VERSION 5.8 ;
BUSBITCHARS "[]" ;
DIVIDERCHAR "/" ;
UNITS
    DATABASE MICRONS 1000 ;
END UNITS

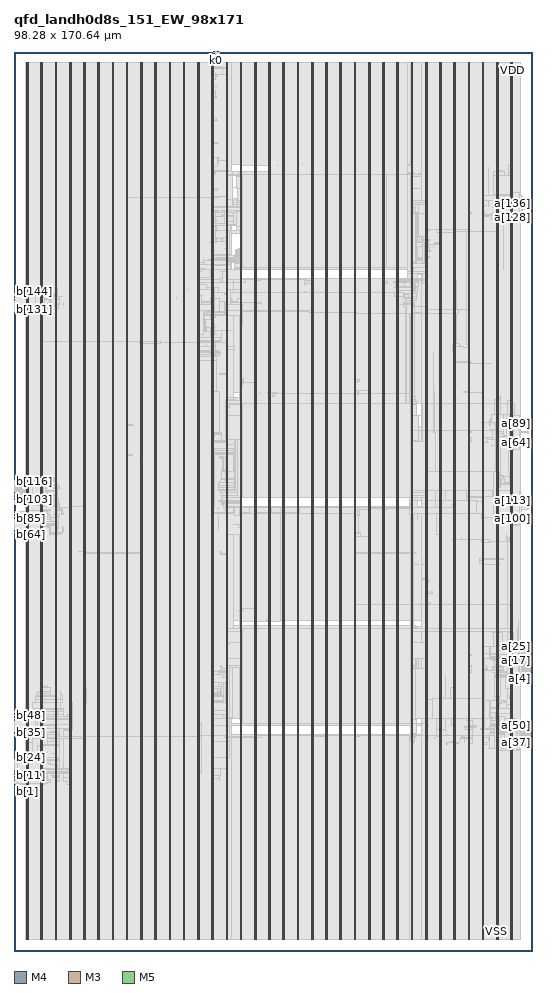
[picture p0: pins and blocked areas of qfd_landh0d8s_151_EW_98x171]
MACRO qfd_landh0d8s_151_EW_98x171
  FOREIGN qfd_landh0d8s_151_EW_98x171 0 0 ;
  CLASS BLOCK ;
  SIZE 98.28 BY 170.64 ;
  PIN a[0]
    DIRECTION INPUT ;
    USE SIGNAL ;
    PORT
      LAYER M4 ;
        RECT  98.196 52.56 98.28 52.584 ;
    END
  END a[0]
  PIN a[100]
    DIRECTION INPUT ;
    USE SIGNAL ;
    PORT
      LAYER M4 ;
        RECT  98.196 81.936 98.28 81.96 ;
    END
  END a[100]
  PIN a[101]
    DIRECTION INPUT ;
    USE SIGNAL ;
    PORT
      LAYER M4 ;
        RECT  98.196 82.08 98.28 82.104 ;
    END
  END a[101]
  PIN a[102]
    DIRECTION INPUT ;
    USE SIGNAL ;
    PORT
      LAYER M4 ;
        RECT  98.196 82.224 98.28 82.248 ;
    END
  END a[102]
  PIN a[103]
    DIRECTION INPUT ;
    USE SIGNAL ;
    PORT
      LAYER M4 ;
        RECT  98.196 82.368 98.28 82.392 ;
    END
  END a[103]
  PIN a[104]
    DIRECTION INPUT ;
    USE SIGNAL ;
    PORT
      LAYER M4 ;
        RECT  98.196 82.512 98.28 82.536 ;
    END
  END a[104]
  PIN a[105]
    DIRECTION INPUT ;
    USE SIGNAL ;
    PORT
      LAYER M4 ;
        RECT  98.196 82.656 98.28 82.68 ;
    END
  END a[105]
  PIN a[106]
    DIRECTION INPUT ;
    USE SIGNAL ;
    PORT
      LAYER M4 ;
        RECT  98.196 82.8 98.28 82.824 ;
    END
  END a[106]
  PIN a[107]
    DIRECTION INPUT ;
    USE SIGNAL ;
    PORT
      LAYER M4 ;
        RECT  98.196 82.944 98.28 82.968 ;
    END
  END a[107]
  PIN a[108]
    DIRECTION INPUT ;
    USE SIGNAL ;
    PORT
      LAYER M4 ;
        RECT  98.196 83.088 98.28 83.112 ;
    END
  END a[108]
  PIN a[109]
    DIRECTION INPUT ;
    USE SIGNAL ;
    PORT
      LAYER M4 ;
        RECT  98.196 83.232 98.28 83.256 ;
    END
  END a[109]
  PIN a[10]
    DIRECTION INPUT ;
    USE SIGNAL ;
    PORT
      LAYER M4 ;
        RECT  98.196 54 98.28 54.024 ;
    END
  END a[10]
  PIN a[110]
    DIRECTION INPUT ;
    USE SIGNAL ;
    PORT
      LAYER M4 ;
        RECT  98.196 83.376 98.28 83.4 ;
    END
  END a[110]
  PIN a[111]
    DIRECTION INPUT ;
    USE SIGNAL ;
    PORT
      LAYER M4 ;
        RECT  98.196 83.52 98.28 83.544 ;
    END
  END a[111]
  PIN a[112]
    DIRECTION INPUT ;
    USE SIGNAL ;
    PORT
      LAYER M4 ;
        RECT  98.196 83.664 98.28 83.688 ;
    END
  END a[112]
  PIN a[113]
    DIRECTION INPUT ;
    USE SIGNAL ;
    PORT
      LAYER M4 ;
        RECT  98.196 83.808 98.28 83.832 ;
    END
  END a[113]
  PIN a[114]
    DIRECTION INPUT ;
    USE SIGNAL ;
    PORT
      LAYER M4 ;
        RECT  98.196 83.952 98.28 83.976 ;
    END
  END a[114]
  PIN a[115]
    DIRECTION INPUT ;
    USE SIGNAL ;
    PORT
      LAYER M4 ;
        RECT  98.196 84.096 98.28 84.12 ;
    END
  END a[115]
  PIN a[116]
    DIRECTION INPUT ;
    USE SIGNAL ;
    PORT
      LAYER M4 ;
        RECT  98.196 84.24 98.28 84.264 ;
    END
  END a[116]
  PIN a[117]
    DIRECTION INPUT ;
    USE SIGNAL ;
    PORT
      LAYER M4 ;
        RECT  98.196 84.384 98.28 84.408 ;
    END
  END a[117]
  PIN a[118]
    DIRECTION INPUT ;
    USE SIGNAL ;
    PORT
      LAYER M4 ;
        RECT  98.196 84.528 98.28 84.552 ;
    END
  END a[118]
  PIN a[119]
    DIRECTION INPUT ;
    USE SIGNAL ;
    PORT
      LAYER M4 ;
        RECT  98.196 84.672 98.28 84.696 ;
    END
  END a[119]
  PIN a[11]
    DIRECTION INPUT ;
    USE SIGNAL ;
    PORT
      LAYER M4 ;
        RECT  98.196 54.144 98.28 54.168 ;
    END
  END a[11]
  PIN a[120]
    DIRECTION INPUT ;
    USE SIGNAL ;
    PORT
      LAYER M4 ;
        RECT  98.196 84.816 98.28 84.84 ;
    END
  END a[120]
  PIN a[121]
    DIRECTION INPUT ;
    USE SIGNAL ;
    PORT
      LAYER M4 ;
        RECT  98.196 84.96 98.28 84.984 ;
    END
  END a[121]
  PIN a[122]
    DIRECTION INPUT ;
    USE SIGNAL ;
    PORT
      LAYER M4 ;
        RECT  98.196 85.104 98.28 85.128 ;
    END
  END a[122]
  PIN a[123]
    DIRECTION INPUT ;
    USE SIGNAL ;
    PORT
      LAYER M4 ;
        RECT  98.196 85.248 98.28 85.272 ;
    END
  END a[123]
  PIN a[124]
    DIRECTION INPUT ;
    USE SIGNAL ;
    PORT
      LAYER M4 ;
        RECT  98.196 85.392 98.28 85.416 ;
    END
  END a[124]
  PIN a[125]
    DIRECTION INPUT ;
    USE SIGNAL ;
    PORT
      LAYER M4 ;
        RECT  98.196 85.536 98.28 85.56 ;
    END
  END a[125]
  PIN a[126]
    DIRECTION INPUT ;
    USE SIGNAL ;
    PORT
      LAYER M4 ;
        RECT  98.196 85.68 98.28 85.704 ;
    END
  END a[126]
  PIN a[127]
    DIRECTION INPUT ;
    USE SIGNAL ;
    PORT
      LAYER M4 ;
        RECT  98.196 85.824 98.28 85.848 ;
    END
  END a[127]
  PIN a[128]
    DIRECTION INPUT ;
    USE SIGNAL ;
    PORT
      LAYER M4 ;
        RECT  98.196 139.104 98.28 139.128 ;
    END
  END a[128]
  PIN a[129]
    DIRECTION INPUT ;
    USE SIGNAL ;
    PORT
      LAYER M4 ;
        RECT  98.196 139.248 98.28 139.272 ;
    END
  END a[129]
  PIN a[12]
    DIRECTION INPUT ;
    USE SIGNAL ;
    PORT
      LAYER M4 ;
        RECT  98.196 54.288 98.28 54.312 ;
    END
  END a[12]
  PIN a[130]
    DIRECTION INPUT ;
    USE SIGNAL ;
    PORT
      LAYER M4 ;
        RECT  98.196 139.392 98.28 139.416 ;
    END
  END a[130]
  PIN a[131]
    DIRECTION INPUT ;
    USE SIGNAL ;
    PORT
      LAYER M4 ;
        RECT  98.196 139.536 98.28 139.56 ;
    END
  END a[131]
  PIN a[132]
    DIRECTION INPUT ;
    USE SIGNAL ;
    PORT
      LAYER M4 ;
        RECT  98.196 139.68 98.28 139.704 ;
    END
  END a[132]
  PIN a[133]
    DIRECTION INPUT ;
    USE SIGNAL ;
    PORT
      LAYER M4 ;
        RECT  98.196 139.824 98.28 139.848 ;
    END
  END a[133]
  PIN a[134]
    DIRECTION INPUT ;
    USE SIGNAL ;
    PORT
      LAYER M4 ;
        RECT  98.196 139.968 98.28 139.992 ;
    END
  END a[134]
  PIN a[135]
    DIRECTION INPUT ;
    USE SIGNAL ;
    PORT
      LAYER M4 ;
        RECT  98.196 140.112 98.28 140.136 ;
    END
  END a[135]
  PIN a[136]
    DIRECTION INPUT ;
    USE SIGNAL ;
    PORT
      LAYER M4 ;
        RECT  98.196 140.256 98.28 140.28 ;
    END
  END a[136]
  PIN a[137]
    DIRECTION INPUT ;
    USE SIGNAL ;
    PORT
      LAYER M4 ;
        RECT  98.196 140.4 98.28 140.424 ;
    END
  END a[137]
  PIN a[138]
    DIRECTION INPUT ;
    USE SIGNAL ;
    PORT
      LAYER M4 ;
        RECT  98.196 140.544 98.28 140.568 ;
    END
  END a[138]
  PIN a[139]
    DIRECTION INPUT ;
    USE SIGNAL ;
    PORT
      LAYER M4 ;
        RECT  98.196 140.688 98.28 140.712 ;
    END
  END a[139]
  PIN a[13]
    DIRECTION INPUT ;
    USE SIGNAL ;
    PORT
      LAYER M4 ;
        RECT  98.196 54.432 98.28 54.456 ;
    END
  END a[13]
  PIN a[140]
    DIRECTION INPUT ;
    USE SIGNAL ;
    PORT
      LAYER M4 ;
        RECT  98.196 140.832 98.28 140.856 ;
    END
  END a[140]
  PIN a[141]
    DIRECTION INPUT ;
    USE SIGNAL ;
    PORT
      LAYER M4 ;
        RECT  98.196 140.976 98.28 141 ;
    END
  END a[141]
  PIN a[142]
    DIRECTION INPUT ;
    USE SIGNAL ;
    PORT
      LAYER M4 ;
        RECT  98.196 141.12 98.28 141.144 ;
    END
  END a[142]
  PIN a[143]
    DIRECTION INPUT ;
    USE SIGNAL ;
    PORT
      LAYER M4 ;
        RECT  98.196 141.264 98.28 141.288 ;
    END
  END a[143]
  PIN a[144]
    DIRECTION INPUT ;
    USE SIGNAL ;
    PORT
      LAYER M4 ;
        RECT  98.196 141.408 98.28 141.432 ;
    END
  END a[144]
  PIN a[145]
    DIRECTION INPUT ;
    USE SIGNAL ;
    PORT
      LAYER M4 ;
        RECT  98.196 141.552 98.28 141.576 ;
    END
  END a[145]
  PIN a[146]
    DIRECTION INPUT ;
    USE SIGNAL ;
    PORT
      LAYER M4 ;
        RECT  98.196 141.696 98.28 141.72 ;
    END
  END a[146]
  PIN a[147]
    DIRECTION INPUT ;
    USE SIGNAL ;
    PORT
      LAYER M4 ;
        RECT  98.196 141.84 98.28 141.864 ;
    END
  END a[147]
  PIN a[148]
    DIRECTION INPUT ;
    USE SIGNAL ;
    PORT
      LAYER M4 ;
        RECT  98.196 141.984 98.28 142.008 ;
    END
  END a[148]
  PIN a[149]
    DIRECTION INPUT ;
    USE SIGNAL ;
    PORT
      LAYER M4 ;
        RECT  98.196 142.128 98.28 142.152 ;
    END
  END a[149]
  PIN a[14]
    DIRECTION INPUT ;
    USE SIGNAL ;
    PORT
      LAYER M4 ;
        RECT  98.196 54.576 98.28 54.6 ;
    END
  END a[14]
  PIN a[150]
    DIRECTION INPUT ;
    USE SIGNAL ;
    PORT
      LAYER M4 ;
        RECT  98.196 142.272 98.28 142.296 ;
    END
  END a[150]
  PIN a[15]
    DIRECTION INPUT ;
    USE SIGNAL ;
    PORT
      LAYER M4 ;
        RECT  98.196 54.72 98.28 54.744 ;
    END
  END a[15]
  PIN a[16]
    DIRECTION INPUT ;
    USE SIGNAL ;
    PORT
      LAYER M4 ;
        RECT  98.196 54.864 98.28 54.888 ;
    END
  END a[16]
  PIN a[17]
    DIRECTION INPUT ;
    USE SIGNAL ;
    PORT
      LAYER M4 ;
        RECT  98.196 55.008 98.28 55.032 ;
    END
  END a[17]
  PIN a[18]
    DIRECTION INPUT ;
    USE SIGNAL ;
    PORT
      LAYER M4 ;
        RECT  98.196 55.152 98.28 55.176 ;
    END
  END a[18]
  PIN a[19]
    DIRECTION INPUT ;
    USE SIGNAL ;
    PORT
      LAYER M4 ;
        RECT  98.196 55.296 98.28 55.32 ;
    END
  END a[19]
  PIN a[1]
    DIRECTION INPUT ;
    USE SIGNAL ;
    PORT
      LAYER M4 ;
        RECT  98.196 52.704 98.28 52.728 ;
    END
  END a[1]
  PIN a[20]
    DIRECTION INPUT ;
    USE SIGNAL ;
    PORT
      LAYER M4 ;
        RECT  98.196 55.44 98.28 55.464 ;
    END
  END a[20]
  PIN a[21]
    DIRECTION INPUT ;
    USE SIGNAL ;
    PORT
      LAYER M4 ;
        RECT  98.196 55.584 98.28 55.608 ;
    END
  END a[21]
  PIN a[22]
    DIRECTION INPUT ;
    USE SIGNAL ;
    PORT
      LAYER M4 ;
        RECT  98.196 55.728 98.28 55.752 ;
    END
  END a[22]
  PIN a[23]
    DIRECTION INPUT ;
    USE SIGNAL ;
    PORT
      LAYER M4 ;
        RECT  98.196 55.872 98.28 55.896 ;
    END
  END a[23]
  PIN a[24]
    DIRECTION INPUT ;
    USE SIGNAL ;
    PORT
      LAYER M4 ;
        RECT  98.196 56.016 98.28 56.04 ;
    END
  END a[24]
  PIN a[25]
    DIRECTION INPUT ;
    USE SIGNAL ;
    PORT
      LAYER M4 ;
        RECT  98.196 56.16 98.28 56.184 ;
    END
  END a[25]
  PIN a[26]
    DIRECTION INPUT ;
    USE SIGNAL ;
    PORT
      LAYER M4 ;
        RECT  98.196 56.304 98.28 56.328 ;
    END
  END a[26]
  PIN a[27]
    DIRECTION INPUT ;
    USE SIGNAL ;
    PORT
      LAYER M4 ;
        RECT  98.196 56.448 98.28 56.472 ;
    END
  END a[27]
  PIN a[28]
    DIRECTION INPUT ;
    USE SIGNAL ;
    PORT
      LAYER M4 ;
        RECT  98.196 56.592 98.28 56.616 ;
    END
  END a[28]
  PIN a[29]
    DIRECTION INPUT ;
    USE SIGNAL ;
    PORT
      LAYER M4 ;
        RECT  98.196 56.736 98.28 56.76 ;
    END
  END a[29]
  PIN a[2]
    DIRECTION INPUT ;
    USE SIGNAL ;
    PORT
      LAYER M4 ;
        RECT  98.196 52.848 98.28 52.872 ;
    END
  END a[2]
  PIN a[30]
    DIRECTION INPUT ;
    USE SIGNAL ;
    PORT
      LAYER M4 ;
        RECT  98.196 56.88 98.28 56.904 ;
    END
  END a[30]
  PIN a[31]
    DIRECTION INPUT ;
    USE SIGNAL ;
    PORT
      LAYER M4 ;
        RECT  98.196 57.024 98.28 57.048 ;
    END
  END a[31]
  PIN a[32]
    DIRECTION INPUT ;
    USE SIGNAL ;
    PORT
      LAYER M4 ;
        RECT  98.196 38.736 98.28 38.76 ;
    END
  END a[32]
  PIN a[33]
    DIRECTION INPUT ;
    USE SIGNAL ;
    PORT
      LAYER M4 ;
        RECT  98.196 38.88 98.28 38.904 ;
    END
  END a[33]
  PIN a[34]
    DIRECTION INPUT ;
    USE SIGNAL ;
    PORT
      LAYER M4 ;
        RECT  98.196 39.024 98.28 39.048 ;
    END
  END a[34]
  PIN a[35]
    DIRECTION INPUT ;
    USE SIGNAL ;
    PORT
      LAYER M4 ;
        RECT  98.196 39.168 98.28 39.192 ;
    END
  END a[35]
  PIN a[36]
    DIRECTION INPUT ;
    USE SIGNAL ;
    PORT
      LAYER M4 ;
        RECT  98.196 39.312 98.28 39.336 ;
    END
  END a[36]
  PIN a[37]
    DIRECTION INPUT ;
    USE SIGNAL ;
    PORT
      LAYER M4 ;
        RECT  98.196 39.456 98.28 39.48 ;
    END
  END a[37]
  PIN a[38]
    DIRECTION INPUT ;
    USE SIGNAL ;
    PORT
      LAYER M4 ;
        RECT  98.196 39.6 98.28 39.624 ;
    END
  END a[38]
  PIN a[39]
    DIRECTION INPUT ;
    USE SIGNAL ;
    PORT
      LAYER M4 ;
        RECT  98.196 39.744 98.28 39.768 ;
    END
  END a[39]
  PIN a[3]
    DIRECTION INPUT ;
    USE SIGNAL ;
    PORT
      LAYER M4 ;
        RECT  98.196 52.992 98.28 53.016 ;
    END
  END a[3]
  PIN a[40]
    DIRECTION INPUT ;
    USE SIGNAL ;
    PORT
      LAYER M4 ;
        RECT  98.196 39.888 98.28 39.912 ;
    END
  END a[40]
  PIN a[41]
    DIRECTION INPUT ;
    USE SIGNAL ;
    PORT
      LAYER M4 ;
        RECT  98.196 40.032 98.28 40.056 ;
    END
  END a[41]
  PIN a[42]
    DIRECTION INPUT ;
    USE SIGNAL ;
    PORT
      LAYER M4 ;
        RECT  98.196 40.176 98.28 40.2 ;
    END
  END a[42]
  PIN a[43]
    DIRECTION INPUT ;
    USE SIGNAL ;
    PORT
      LAYER M4 ;
        RECT  98.196 40.32 98.28 40.344 ;
    END
  END a[43]
  PIN a[44]
    DIRECTION INPUT ;
    USE SIGNAL ;
    PORT
      LAYER M4 ;
        RECT  98.196 40.464 98.28 40.488 ;
    END
  END a[44]
  PIN a[45]
    DIRECTION INPUT ;
    USE SIGNAL ;
    PORT
      LAYER M4 ;
        RECT  98.196 40.608 98.28 40.632 ;
    END
  END a[45]
  PIN a[46]
    DIRECTION INPUT ;
    USE SIGNAL ;
    PORT
      LAYER M4 ;
        RECT  98.196 40.752 98.28 40.776 ;
    END
  END a[46]
  PIN a[47]
    DIRECTION INPUT ;
    USE SIGNAL ;
    PORT
      LAYER M4 ;
        RECT  98.196 40.896 98.28 40.92 ;
    END
  END a[47]
  PIN a[48]
    DIRECTION INPUT ;
    USE SIGNAL ;
    PORT
      LAYER M4 ;
        RECT  98.196 41.04 98.28 41.064 ;
    END
  END a[48]
  PIN a[49]
    DIRECTION INPUT ;
    USE SIGNAL ;
    PORT
      LAYER M4 ;
        RECT  98.196 41.184 98.28 41.208 ;
    END
  END a[49]
  PIN a[4]
    DIRECTION INPUT ;
    USE SIGNAL ;
    PORT
      LAYER M4 ;
        RECT  98.196 53.136 98.28 53.16 ;
    END
  END a[4]
  PIN a[50]
    DIRECTION INPUT ;
    USE SIGNAL ;
    PORT
      LAYER M4 ;
        RECT  98.196 41.328 98.28 41.352 ;
    END
  END a[50]
  PIN a[51]
    DIRECTION INPUT ;
    USE SIGNAL ;
    PORT
      LAYER M4 ;
        RECT  98.196 41.472 98.28 41.496 ;
    END
  END a[51]
  PIN a[52]
    DIRECTION INPUT ;
    USE SIGNAL ;
    PORT
      LAYER M4 ;
        RECT  98.196 41.616 98.28 41.64 ;
    END
  END a[52]
  PIN a[53]
    DIRECTION INPUT ;
    USE SIGNAL ;
    PORT
      LAYER M4 ;
        RECT  98.196 41.76 98.28 41.784 ;
    END
  END a[53]
  PIN a[54]
    DIRECTION INPUT ;
    USE SIGNAL ;
    PORT
      LAYER M4 ;
        RECT  98.196 41.904 98.28 41.928 ;
    END
  END a[54]
  PIN a[55]
    DIRECTION INPUT ;
    USE SIGNAL ;
    PORT
      LAYER M4 ;
        RECT  98.196 42.048 98.28 42.072 ;
    END
  END a[55]
  PIN a[56]
    DIRECTION INPUT ;
    USE SIGNAL ;
    PORT
      LAYER M4 ;
        RECT  98.196 42.192 98.28 42.216 ;
    END
  END a[56]
  PIN a[57]
    DIRECTION INPUT ;
    USE SIGNAL ;
    PORT
      LAYER M4 ;
        RECT  98.196 42.336 98.28 42.36 ;
    END
  END a[57]
  PIN a[58]
    DIRECTION INPUT ;
    USE SIGNAL ;
    PORT
      LAYER M4 ;
        RECT  98.196 42.48 98.28 42.504 ;
    END
  END a[58]
  PIN a[59]
    DIRECTION INPUT ;
    USE SIGNAL ;
    PORT
      LAYER M4 ;
        RECT  98.196 42.624 98.28 42.648 ;
    END
  END a[59]
  PIN a[5]
    DIRECTION INPUT ;
    USE SIGNAL ;
    PORT
      LAYER M4 ;
        RECT  98.196 53.28 98.28 53.304 ;
    END
  END a[5]
  PIN a[60]
    DIRECTION INPUT ;
    USE SIGNAL ;
    PORT
      LAYER M4 ;
        RECT  98.196 42.768 98.28 42.792 ;
    END
  END a[60]
  PIN a[61]
    DIRECTION INPUT ;
    USE SIGNAL ;
    PORT
      LAYER M4 ;
        RECT  98.196 42.912 98.28 42.936 ;
    END
  END a[61]
  PIN a[62]
    DIRECTION INPUT ;
    USE SIGNAL ;
    PORT
      LAYER M4 ;
        RECT  98.196 43.056 98.28 43.08 ;
    END
  END a[62]
  PIN a[63]
    DIRECTION INPUT ;
    USE SIGNAL ;
    PORT
      LAYER M4 ;
        RECT  98.196 43.2 98.28 43.224 ;
    END
  END a[63]
  PIN a[64]
    DIRECTION INPUT ;
    USE SIGNAL ;
    PORT
      LAYER M4 ;
        RECT  98.196 96.336 98.28 96.36 ;
    END
  END a[64]
  PIN a[65]
    DIRECTION INPUT ;
    USE SIGNAL ;
    PORT
      LAYER M4 ;
        RECT  98.196 96.48 98.28 96.504 ;
    END
  END a[65]
  PIN a[66]
    DIRECTION INPUT ;
    USE SIGNAL ;
    PORT
      LAYER M4 ;
        RECT  98.196 96.624 98.28 96.648 ;
    END
  END a[66]
  PIN a[67]
    DIRECTION INPUT ;
    USE SIGNAL ;
    PORT
      LAYER M4 ;
        RECT  98.196 96.768 98.28 96.792 ;
    END
  END a[67]
  PIN a[68]
    DIRECTION INPUT ;
    USE SIGNAL ;
    PORT
      LAYER M4 ;
        RECT  98.196 96.912 98.28 96.936 ;
    END
  END a[68]
  PIN a[69]
    DIRECTION INPUT ;
    USE SIGNAL ;
    PORT
      LAYER M4 ;
        RECT  98.196 97.056 98.28 97.08 ;
    END
  END a[69]
  PIN a[6]
    DIRECTION INPUT ;
    USE SIGNAL ;
    PORT
      LAYER M4 ;
        RECT  98.196 53.424 98.28 53.448 ;
    END
  END a[6]
  PIN a[70]
    DIRECTION INPUT ;
    USE SIGNAL ;
    PORT
      LAYER M4 ;
        RECT  98.196 97.2 98.28 97.224 ;
    END
  END a[70]
  PIN a[71]
    DIRECTION INPUT ;
    USE SIGNAL ;
    PORT
      LAYER M4 ;
        RECT  98.196 97.344 98.28 97.368 ;
    END
  END a[71]
  PIN a[72]
    DIRECTION INPUT ;
    USE SIGNAL ;
    PORT
      LAYER M4 ;
        RECT  98.196 97.488 98.28 97.512 ;
    END
  END a[72]
  PIN a[73]
    DIRECTION INPUT ;
    USE SIGNAL ;
    PORT
      LAYER M4 ;
        RECT  98.196 97.632 98.28 97.656 ;
    END
  END a[73]
  PIN a[74]
    DIRECTION INPUT ;
    USE SIGNAL ;
    PORT
      LAYER M4 ;
        RECT  98.196 97.776 98.28 97.8 ;
    END
  END a[74]
  PIN a[75]
    DIRECTION INPUT ;
    USE SIGNAL ;
    PORT
      LAYER M4 ;
        RECT  98.196 97.92 98.28 97.944 ;
    END
  END a[75]
  PIN a[76]
    DIRECTION INPUT ;
    USE SIGNAL ;
    PORT
      LAYER M4 ;
        RECT  98.196 98.064 98.28 98.088 ;
    END
  END a[76]
  PIN a[77]
    DIRECTION INPUT ;
    USE SIGNAL ;
    PORT
      LAYER M4 ;
        RECT  98.196 98.208 98.28 98.232 ;
    END
  END a[77]
  PIN a[78]
    DIRECTION INPUT ;
    USE SIGNAL ;
    PORT
      LAYER M4 ;
        RECT  98.196 98.352 98.28 98.376 ;
    END
  END a[78]
  PIN a[79]
    DIRECTION INPUT ;
    USE SIGNAL ;
    PORT
      LAYER M4 ;
        RECT  98.196 98.496 98.28 98.52 ;
    END
  END a[79]
  PIN a[7]
    DIRECTION INPUT ;
    USE SIGNAL ;
    PORT
      LAYER M4 ;
        RECT  98.196 53.568 98.28 53.592 ;
    END
  END a[7]
  PIN a[80]
    DIRECTION INPUT ;
    USE SIGNAL ;
    PORT
      LAYER M4 ;
        RECT  98.196 98.64 98.28 98.664 ;
    END
  END a[80]
  PIN a[81]
    DIRECTION INPUT ;
    USE SIGNAL ;
    PORT
      LAYER M4 ;
        RECT  98.196 98.784 98.28 98.808 ;
    END
  END a[81]
  PIN a[82]
    DIRECTION INPUT ;
    USE SIGNAL ;
    PORT
      LAYER M4 ;
        RECT  98.196 98.928 98.28 98.952 ;
    END
  END a[82]
  PIN a[83]
    DIRECTION INPUT ;
    USE SIGNAL ;
    PORT
      LAYER M4 ;
        RECT  98.196 99.072 98.28 99.096 ;
    END
  END a[83]
  PIN a[84]
    DIRECTION INPUT ;
    USE SIGNAL ;
    PORT
      LAYER M4 ;
        RECT  98.196 99.216 98.28 99.24 ;
    END
  END a[84]
  PIN a[85]
    DIRECTION INPUT ;
    USE SIGNAL ;
    PORT
      LAYER M4 ;
        RECT  98.196 99.36 98.28 99.384 ;
    END
  END a[85]
  PIN a[86]
    DIRECTION INPUT ;
    USE SIGNAL ;
    PORT
      LAYER M4 ;
        RECT  98.196 99.504 98.28 99.528 ;
    END
  END a[86]
  PIN a[87]
    DIRECTION INPUT ;
    USE SIGNAL ;
    PORT
      LAYER M4 ;
        RECT  98.196 99.648 98.28 99.672 ;
    END
  END a[87]
  PIN a[88]
    DIRECTION INPUT ;
    USE SIGNAL ;
    PORT
      LAYER M4 ;
        RECT  98.196 99.792 98.28 99.816 ;
    END
  END a[88]
  PIN a[89]
    DIRECTION INPUT ;
    USE SIGNAL ;
    PORT
      LAYER M4 ;
        RECT  98.196 99.936 98.28 99.96 ;
    END
  END a[89]
  PIN a[8]
    DIRECTION INPUT ;
    USE SIGNAL ;
    PORT
      LAYER M4 ;
        RECT  98.196 53.712 98.28 53.736 ;
    END
  END a[8]
  PIN a[90]
    DIRECTION INPUT ;
    USE SIGNAL ;
    PORT
      LAYER M4 ;
        RECT  98.196 100.08 98.28 100.104 ;
    END
  END a[90]
  PIN a[91]
    DIRECTION INPUT ;
    USE SIGNAL ;
    PORT
      LAYER M4 ;
        RECT  98.196 100.224 98.28 100.248 ;
    END
  END a[91]
  PIN a[92]
    DIRECTION INPUT ;
    USE SIGNAL ;
    PORT
      LAYER M4 ;
        RECT  98.196 100.368 98.28 100.392 ;
    END
  END a[92]
  PIN a[93]
    DIRECTION INPUT ;
    USE SIGNAL ;
    PORT
      LAYER M4 ;
        RECT  98.196 100.512 98.28 100.536 ;
    END
  END a[93]
  PIN a[94]
    DIRECTION INPUT ;
    USE SIGNAL ;
    PORT
      LAYER M4 ;
        RECT  98.196 100.656 98.28 100.68 ;
    END
  END a[94]
  PIN a[95]
    DIRECTION INPUT ;
    USE SIGNAL ;
    PORT
      LAYER M4 ;
        RECT  98.196 100.8 98.28 100.824 ;
    END
  END a[95]
  PIN a[96]
    DIRECTION INPUT ;
    USE SIGNAL ;
    PORT
      LAYER M4 ;
        RECT  98.196 81.36 98.28 81.384 ;
    END
  END a[96]
  PIN a[97]
    DIRECTION INPUT ;
    USE SIGNAL ;
    PORT
      LAYER M4 ;
        RECT  98.196 81.504 98.28 81.528 ;
    END
  END a[97]
  PIN a[98]
    DIRECTION INPUT ;
    USE SIGNAL ;
    PORT
      LAYER M4 ;
        RECT  98.196 81.648 98.28 81.672 ;
    END
  END a[98]
  PIN a[99]
    DIRECTION INPUT ;
    USE SIGNAL ;
    PORT
      LAYER M4 ;
        RECT  98.196 81.792 98.28 81.816 ;
    END
  END a[99]
  PIN a[9]
    DIRECTION INPUT ;
    USE SIGNAL ;
    PORT
      LAYER M4 ;
        RECT  98.196 53.856 98.28 53.88 ;
    END
  END a[9]
  PIN b[0]
    DIRECTION OUTPUT ;
    USE SIGNAL ;
    PORT
      LAYER M4 ;
        RECT  0 31.68 0.084 31.704 ;
    END
  END b[0]
  PIN b[100]
    DIRECTION OUTPUT ;
    USE SIGNAL ;
    PORT
      LAYER M4 ;
        RECT  0 85.248 0.084 85.272 ;
    END
  END b[100]
  PIN b[101]
    DIRECTION OUTPUT ;
    USE SIGNAL ;
    PORT
      LAYER M4 ;
        RECT  0 85.392 0.084 85.416 ;
    END
  END b[101]
  PIN b[102]
    DIRECTION OUTPUT ;
    USE SIGNAL ;
    PORT
      LAYER M4 ;
        RECT  0 85.536 0.084 85.56 ;
    END
  END b[102]
  PIN b[103]
    DIRECTION OUTPUT ;
    USE SIGNAL ;
    PORT
      LAYER M4 ;
        RECT  0 85.68 0.084 85.704 ;
    END
  END b[103]
  PIN b[104]
    DIRECTION OUTPUT ;
    USE SIGNAL ;
    PORT
      LAYER M4 ;
        RECT  0 85.824 0.084 85.848 ;
    END
  END b[104]
  PIN b[105]
    DIRECTION OUTPUT ;
    USE SIGNAL ;
    PORT
      LAYER M4 ;
        RECT  0 85.968 0.084 85.992 ;
    END
  END b[105]
  PIN b[106]
    DIRECTION OUTPUT ;
    USE SIGNAL ;
    PORT
      LAYER M4 ;
        RECT  0 86.112 0.084 86.136 ;
    END
  END b[106]
  PIN b[107]
    DIRECTION OUTPUT ;
    USE SIGNAL ;
    PORT
      LAYER M4 ;
        RECT  0 86.256 0.084 86.28 ;
    END
  END b[107]
  PIN b[108]
    DIRECTION OUTPUT ;
    USE SIGNAL ;
    PORT
      LAYER M4 ;
        RECT  0 86.4 0.084 86.424 ;
    END
  END b[108]
  PIN b[109]
    DIRECTION OUTPUT ;
    USE SIGNAL ;
    PORT
      LAYER M4 ;
        RECT  0 86.544 0.084 86.568 ;
    END
  END b[109]
  PIN b[10]
    DIRECTION OUTPUT ;
    USE SIGNAL ;
    PORT
      LAYER M4 ;
        RECT  0 33.12 0.084 33.144 ;
    END
  END b[10]
  PIN b[110]
    DIRECTION OUTPUT ;
    USE SIGNAL ;
    PORT
      LAYER M4 ;
        RECT  0 86.688 0.084 86.712 ;
    END
  END b[110]
  PIN b[111]
    DIRECTION OUTPUT ;
    USE SIGNAL ;
    PORT
      LAYER M4 ;
        RECT  0 86.832 0.084 86.856 ;
    END
  END b[111]
  PIN b[112]
    DIRECTION OUTPUT ;
    USE SIGNAL ;
    PORT
      LAYER M4 ;
        RECT  0 86.976 0.084 87 ;
    END
  END b[112]
  PIN b[113]
    DIRECTION OUTPUT ;
    USE SIGNAL ;
    PORT
      LAYER M4 ;
        RECT  0 87.12 0.084 87.144 ;
    END
  END b[113]
  PIN b[114]
    DIRECTION OUTPUT ;
    USE SIGNAL ;
    PORT
      LAYER M4 ;
        RECT  0 87.264 0.084 87.288 ;
    END
  END b[114]
  PIN b[115]
    DIRECTION OUTPUT ;
    USE SIGNAL ;
    PORT
      LAYER M4 ;
        RECT  0 87.408 0.084 87.432 ;
    END
  END b[115]
  PIN b[116]
    DIRECTION OUTPUT ;
    USE SIGNAL ;
    PORT
      LAYER M4 ;
        RECT  0 87.552 0.084 87.576 ;
    END
  END b[116]
  PIN b[117]
    DIRECTION OUTPUT ;
    USE SIGNAL ;
    PORT
      LAYER M4 ;
        RECT  0 87.696 0.084 87.72 ;
    END
  END b[117]
  PIN b[118]
    DIRECTION OUTPUT ;
    USE SIGNAL ;
    PORT
      LAYER M4 ;
        RECT  0 87.84 0.084 87.864 ;
    END
  END b[118]
  PIN b[119]
    DIRECTION OUTPUT ;
    USE SIGNAL ;
    PORT
      LAYER M4 ;
        RECT  0 87.984 0.084 88.008 ;
    END
  END b[119]
  PIN b[11]
    DIRECTION OUTPUT ;
    USE SIGNAL ;
    PORT
      LAYER M4 ;
        RECT  0 33.264 0.084 33.288 ;
    END
  END b[11]
  PIN b[120]
    DIRECTION OUTPUT ;
    USE SIGNAL ;
    PORT
      LAYER M4 ;
        RECT  0 88.128 0.084 88.152 ;
    END
  END b[120]
  PIN b[121]
    DIRECTION OUTPUT ;
    USE SIGNAL ;
    PORT
      LAYER M4 ;
        RECT  0 88.272 0.084 88.296 ;
    END
  END b[121]
  PIN b[122]
    DIRECTION OUTPUT ;
    USE SIGNAL ;
    PORT
      LAYER M4 ;
        RECT  0 88.416 0.084 88.44 ;
    END
  END b[122]
  PIN b[123]
    DIRECTION OUTPUT ;
    USE SIGNAL ;
    PORT
      LAYER M4 ;
        RECT  0 88.56 0.084 88.584 ;
    END
  END b[123]
  PIN b[124]
    DIRECTION OUTPUT ;
    USE SIGNAL ;
    PORT
      LAYER M4 ;
        RECT  0 88.704 0.084 88.728 ;
    END
  END b[124]
  PIN b[125]
    DIRECTION OUTPUT ;
    USE SIGNAL ;
    PORT
      LAYER M4 ;
        RECT  0 88.848 0.084 88.872 ;
    END
  END b[125]
  PIN b[126]
    DIRECTION OUTPUT ;
    USE SIGNAL ;
    PORT
      LAYER M4 ;
        RECT  0 88.992 0.084 89.016 ;
    END
  END b[126]
  PIN b[127]
    DIRECTION OUTPUT ;
    USE SIGNAL ;
    PORT
      LAYER M4 ;
        RECT  0 89.136 0.084 89.16 ;
    END
  END b[127]
  PIN b[128]
    DIRECTION OUTPUT ;
    USE SIGNAL ;
    PORT
      LAYER M4 ;
        RECT  0 121.248 0.084 121.272 ;
    END
  END b[128]
  PIN b[129]
    DIRECTION OUTPUT ;
    USE SIGNAL ;
    PORT
      LAYER M4 ;
        RECT  0 121.392 0.084 121.416 ;
    END
  END b[129]
  PIN b[12]
    DIRECTION OUTPUT ;
    USE SIGNAL ;
    PORT
      LAYER M4 ;
        RECT  0 33.408 0.084 33.432 ;
    END
  END b[12]
  PIN b[130]
    DIRECTION OUTPUT ;
    USE SIGNAL ;
    PORT
      LAYER M4 ;
        RECT  0 121.536 0.084 121.56 ;
    END
  END b[130]
  PIN b[131]
    DIRECTION OUTPUT ;
    USE SIGNAL ;
    PORT
      LAYER M4 ;
        RECT  0 121.68 0.084 121.704 ;
    END
  END b[131]
  PIN b[132]
    DIRECTION OUTPUT ;
    USE SIGNAL ;
    PORT
      LAYER M4 ;
        RECT  0 121.824 0.084 121.848 ;
    END
  END b[132]
  PIN b[133]
    DIRECTION OUTPUT ;
    USE SIGNAL ;
    PORT
      LAYER M4 ;
        RECT  0 121.968 0.084 121.992 ;
    END
  END b[133]
  PIN b[134]
    DIRECTION OUTPUT ;
    USE SIGNAL ;
    PORT
      LAYER M4 ;
        RECT  0 122.112 0.084 122.136 ;
    END
  END b[134]
  PIN b[135]
    DIRECTION OUTPUT ;
    USE SIGNAL ;
    PORT
      LAYER M4 ;
        RECT  0 122.256 0.084 122.28 ;
    END
  END b[135]
  PIN b[136]
    DIRECTION OUTPUT ;
    USE SIGNAL ;
    PORT
      LAYER M4 ;
        RECT  0 122.4 0.084 122.424 ;
    END
  END b[136]
  PIN b[137]
    DIRECTION OUTPUT ;
    USE SIGNAL ;
    PORT
      LAYER M4 ;
        RECT  0 122.544 0.084 122.568 ;
    END
  END b[137]
  PIN b[138]
    DIRECTION OUTPUT ;
    USE SIGNAL ;
    PORT
      LAYER M4 ;
        RECT  0 122.688 0.084 122.712 ;
    END
  END b[138]
  PIN b[139]
    DIRECTION OUTPUT ;
    USE SIGNAL ;
    PORT
      LAYER M4 ;
        RECT  0 122.832 0.084 122.856 ;
    END
  END b[139]
  PIN b[13]
    DIRECTION OUTPUT ;
    USE SIGNAL ;
    PORT
      LAYER M4 ;
        RECT  0 33.552 0.084 33.576 ;
    END
  END b[13]
  PIN b[140]
    DIRECTION OUTPUT ;
    USE SIGNAL ;
    PORT
      LAYER M4 ;
        RECT  0 122.976 0.084 123 ;
    END
  END b[140]
  PIN b[141]
    DIRECTION OUTPUT ;
    USE SIGNAL ;
    PORT
      LAYER M4 ;
        RECT  0 123.12 0.084 123.144 ;
    END
  END b[141]
  PIN b[142]
    DIRECTION OUTPUT ;
    USE SIGNAL ;
    PORT
      LAYER M4 ;
        RECT  0 123.264 0.084 123.288 ;
    END
  END b[142]
  PIN b[143]
    DIRECTION OUTPUT ;
    USE SIGNAL ;
    PORT
      LAYER M4 ;
        RECT  0 123.408 0.084 123.432 ;
    END
  END b[143]
  PIN b[144]
    DIRECTION OUTPUT ;
    USE SIGNAL ;
    PORT
      LAYER M4 ;
        RECT  0 123.552 0.084 123.576 ;
    END
  END b[144]
  PIN b[145]
    DIRECTION OUTPUT ;
    USE SIGNAL ;
    PORT
      LAYER M4 ;
        RECT  0 123.696 0.084 123.72 ;
    END
  END b[145]
  PIN b[146]
    DIRECTION OUTPUT ;
    USE SIGNAL ;
    PORT
      LAYER M4 ;
        RECT  0 123.84 0.084 123.864 ;
    END
  END b[146]
  PIN b[147]
    DIRECTION OUTPUT ;
    USE SIGNAL ;
    PORT
      LAYER M4 ;
        RECT  0 123.984 0.084 124.008 ;
    END
  END b[147]
  PIN b[148]
    DIRECTION OUTPUT ;
    USE SIGNAL ;
    PORT
      LAYER M4 ;
        RECT  0 124.128 0.084 124.152 ;
    END
  END b[148]
  PIN b[149]
    DIRECTION OUTPUT ;
    USE SIGNAL ;
    PORT
      LAYER M4 ;
        RECT  0 124.272 0.084 124.296 ;
    END
  END b[149]
  PIN b[14]
    DIRECTION OUTPUT ;
    USE SIGNAL ;
    PORT
      LAYER M4 ;
        RECT  0 33.696 0.084 33.72 ;
    END
  END b[14]
  PIN b[150]
    DIRECTION OUTPUT ;
    USE SIGNAL ;
    PORT
      LAYER M4 ;
        RECT  0 124.416 0.084 124.44 ;
    END
  END b[150]
  PIN b[15]
    DIRECTION OUTPUT ;
    USE SIGNAL ;
    PORT
      LAYER M4 ;
        RECT  0 33.84 0.084 33.864 ;
    END
  END b[15]
  PIN b[16]
    DIRECTION OUTPUT ;
    USE SIGNAL ;
    PORT
      LAYER M4 ;
        RECT  0 33.984 0.084 34.008 ;
    END
  END b[16]
  PIN b[17]
    DIRECTION OUTPUT ;
    USE SIGNAL ;
    PORT
      LAYER M4 ;
        RECT  0 34.128 0.084 34.152 ;
    END
  END b[17]
  PIN b[18]
    DIRECTION OUTPUT ;
    USE SIGNAL ;
    PORT
      LAYER M4 ;
        RECT  0 34.272 0.084 34.296 ;
    END
  END b[18]
  PIN b[19]
    DIRECTION OUTPUT ;
    USE SIGNAL ;
    PORT
      LAYER M4 ;
        RECT  0 34.416 0.084 34.44 ;
    END
  END b[19]
  PIN b[1]
    DIRECTION OUTPUT ;
    USE SIGNAL ;
    PORT
      LAYER M4 ;
        RECT  0 31.824 0.084 31.848 ;
    END
  END b[1]
  PIN b[20]
    DIRECTION OUTPUT ;
    USE SIGNAL ;
    PORT
      LAYER M4 ;
        RECT  0 34.56 0.084 34.584 ;
    END
  END b[20]
  PIN b[21]
    DIRECTION OUTPUT ;
    USE SIGNAL ;
    PORT
      LAYER M4 ;
        RECT  0 34.704 0.084 34.728 ;
    END
  END b[21]
  PIN b[22]
    DIRECTION OUTPUT ;
    USE SIGNAL ;
    PORT
      LAYER M4 ;
        RECT  0 34.848 0.084 34.872 ;
    END
  END b[22]
  PIN b[23]
    DIRECTION OUTPUT ;
    USE SIGNAL ;
    PORT
      LAYER M4 ;
        RECT  0 34.992 0.084 35.016 ;
    END
  END b[23]
  PIN b[24]
    DIRECTION OUTPUT ;
    USE SIGNAL ;
    PORT
      LAYER M4 ;
        RECT  0 35.136 0.084 35.16 ;
    END
  END b[24]
  PIN b[25]
    DIRECTION OUTPUT ;
    USE SIGNAL ;
    PORT
      LAYER M4 ;
        RECT  0 35.28 0.084 35.304 ;
    END
  END b[25]
  PIN b[26]
    DIRECTION OUTPUT ;
    USE SIGNAL ;
    PORT
      LAYER M4 ;
        RECT  0 35.424 0.084 35.448 ;
    END
  END b[26]
  PIN b[27]
    DIRECTION OUTPUT ;
    USE SIGNAL ;
    PORT
      LAYER M4 ;
        RECT  0 35.568 0.084 35.592 ;
    END
  END b[27]
  PIN b[28]
    DIRECTION OUTPUT ;
    USE SIGNAL ;
    PORT
      LAYER M4 ;
        RECT  0 35.712 0.084 35.736 ;
    END
  END b[28]
  PIN b[29]
    DIRECTION OUTPUT ;
    USE SIGNAL ;
    PORT
      LAYER M4 ;
        RECT  0 35.856 0.084 35.88 ;
    END
  END b[29]
  PIN b[2]
    DIRECTION OUTPUT ;
    USE SIGNAL ;
    PORT
      LAYER M4 ;
        RECT  0 31.968 0.084 31.992 ;
    END
  END b[2]
  PIN b[30]
    DIRECTION OUTPUT ;
    USE SIGNAL ;
    PORT
      LAYER M4 ;
        RECT  0 36 0.084 36.024 ;
    END
  END b[30]
  PIN b[31]
    DIRECTION OUTPUT ;
    USE SIGNAL ;
    PORT
      LAYER M4 ;
        RECT  0 36.144 0.084 36.168 ;
    END
  END b[31]
  PIN b[32]
    DIRECTION OUTPUT ;
    USE SIGNAL ;
    PORT
      LAYER M4 ;
        RECT  0 40.896 0.084 40.92 ;
    END
  END b[32]
  PIN b[33]
    DIRECTION OUTPUT ;
    USE SIGNAL ;
    PORT
      LAYER M4 ;
        RECT  0 41.04 0.084 41.064 ;
    END
  END b[33]
  PIN b[34]
    DIRECTION OUTPUT ;
    USE SIGNAL ;
    PORT
      LAYER M4 ;
        RECT  0 41.184 0.084 41.208 ;
    END
  END b[34]
  PIN b[35]
    DIRECTION OUTPUT ;
    USE SIGNAL ;
    PORT
      LAYER M4 ;
        RECT  0 41.328 0.084 41.352 ;
    END
  END b[35]
  PIN b[36]
    DIRECTION OUTPUT ;
    USE SIGNAL ;
    PORT
      LAYER M4 ;
        RECT  0 41.472 0.084 41.496 ;
    END
  END b[36]
  PIN b[37]
    DIRECTION OUTPUT ;
    USE SIGNAL ;
    PORT
      LAYER M4 ;
        RECT  0 41.616 0.084 41.64 ;
    END
  END b[37]
  PIN b[38]
    DIRECTION OUTPUT ;
    USE SIGNAL ;
    PORT
      LAYER M4 ;
        RECT  0 41.76 0.084 41.784 ;
    END
  END b[38]
  PIN b[39]
    DIRECTION OUTPUT ;
    USE SIGNAL ;
    PORT
      LAYER M4 ;
        RECT  0 41.904 0.084 41.928 ;
    END
  END b[39]
  PIN b[3]
    DIRECTION OUTPUT ;
    USE SIGNAL ;
    PORT
      LAYER M4 ;
        RECT  0 32.112 0.084 32.136 ;
    END
  END b[3]
  PIN b[40]
    DIRECTION OUTPUT ;
    USE SIGNAL ;
    PORT
      LAYER M4 ;
        RECT  0 42.048 0.084 42.072 ;
    END
  END b[40]
  PIN b[41]
    DIRECTION OUTPUT ;
    USE SIGNAL ;
    PORT
      LAYER M4 ;
        RECT  0 42.192 0.084 42.216 ;
    END
  END b[41]
  PIN b[42]
    DIRECTION OUTPUT ;
    USE SIGNAL ;
    PORT
      LAYER M4 ;
        RECT  0 42.336 0.084 42.36 ;
    END
  END b[42]
  PIN b[43]
    DIRECTION OUTPUT ;
    USE SIGNAL ;
    PORT
      LAYER M4 ;
        RECT  0 42.48 0.084 42.504 ;
    END
  END b[43]
  PIN b[44]
    DIRECTION OUTPUT ;
    USE SIGNAL ;
    PORT
      LAYER M4 ;
        RECT  0 42.624 0.084 42.648 ;
    END
  END b[44]
  PIN b[45]
    DIRECTION OUTPUT ;
    USE SIGNAL ;
    PORT
      LAYER M4 ;
        RECT  0 42.768 0.084 42.792 ;
    END
  END b[45]
  PIN b[46]
    DIRECTION OUTPUT ;
    USE SIGNAL ;
    PORT
      LAYER M4 ;
        RECT  0 42.912 0.084 42.936 ;
    END
  END b[46]
  PIN b[47]
    DIRECTION OUTPUT ;
    USE SIGNAL ;
    PORT
      LAYER M4 ;
        RECT  0 43.056 0.084 43.08 ;
    END
  END b[47]
  PIN b[48]
    DIRECTION OUTPUT ;
    USE SIGNAL ;
    PORT
      LAYER M4 ;
        RECT  0 43.2 0.084 43.224 ;
    END
  END b[48]
  PIN b[49]
    DIRECTION OUTPUT ;
    USE SIGNAL ;
    PORT
      LAYER M4 ;
        RECT  0 43.344 0.084 43.368 ;
    END
  END b[49]
  PIN b[4]
    DIRECTION OUTPUT ;
    USE SIGNAL ;
    PORT
      LAYER M4 ;
        RECT  0 32.256 0.084 32.28 ;
    END
  END b[4]
  PIN b[50]
    DIRECTION OUTPUT ;
    USE SIGNAL ;
    PORT
      LAYER M4 ;
        RECT  0 43.488 0.084 43.512 ;
    END
  END b[50]
  PIN b[51]
    DIRECTION OUTPUT ;
    USE SIGNAL ;
    PORT
      LAYER M4 ;
        RECT  0 43.632 0.084 43.656 ;
    END
  END b[51]
  PIN b[52]
    DIRECTION OUTPUT ;
    USE SIGNAL ;
    PORT
      LAYER M4 ;
        RECT  0 43.776 0.084 43.8 ;
    END
  END b[52]
  PIN b[53]
    DIRECTION OUTPUT ;
    USE SIGNAL ;
    PORT
      LAYER M4 ;
        RECT  0 43.92 0.084 43.944 ;
    END
  END b[53]
  PIN b[54]
    DIRECTION OUTPUT ;
    USE SIGNAL ;
    PORT
      LAYER M4 ;
        RECT  0 44.064 0.084 44.088 ;
    END
  END b[54]
  PIN b[55]
    DIRECTION OUTPUT ;
    USE SIGNAL ;
    PORT
      LAYER M4 ;
        RECT  0 44.208 0.084 44.232 ;
    END
  END b[55]
  PIN b[56]
    DIRECTION OUTPUT ;
    USE SIGNAL ;
    PORT
      LAYER M4 ;
        RECT  0 44.352 0.084 44.376 ;
    END
  END b[56]
  PIN b[57]
    DIRECTION OUTPUT ;
    USE SIGNAL ;
    PORT
      LAYER M4 ;
        RECT  0 44.496 0.084 44.52 ;
    END
  END b[57]
  PIN b[58]
    DIRECTION OUTPUT ;
    USE SIGNAL ;
    PORT
      LAYER M4 ;
        RECT  0 44.64 0.084 44.664 ;
    END
  END b[58]
  PIN b[59]
    DIRECTION OUTPUT ;
    USE SIGNAL ;
    PORT
      LAYER M4 ;
        RECT  0 44.784 0.084 44.808 ;
    END
  END b[59]
  PIN b[5]
    DIRECTION OUTPUT ;
    USE SIGNAL ;
    PORT
      LAYER M4 ;
        RECT  0 32.4 0.084 32.424 ;
    END
  END b[5]
  PIN b[60]
    DIRECTION OUTPUT ;
    USE SIGNAL ;
    PORT
      LAYER M4 ;
        RECT  0 44.928 0.084 44.952 ;
    END
  END b[60]
  PIN b[61]
    DIRECTION OUTPUT ;
    USE SIGNAL ;
    PORT
      LAYER M4 ;
        RECT  0 45.072 0.084 45.096 ;
    END
  END b[61]
  PIN b[62]
    DIRECTION OUTPUT ;
    USE SIGNAL ;
    PORT
      LAYER M4 ;
        RECT  0 45.216 0.084 45.24 ;
    END
  END b[62]
  PIN b[63]
    DIRECTION OUTPUT ;
    USE SIGNAL ;
    PORT
      LAYER M4 ;
        RECT  0 45.36 0.084 45.384 ;
    END
  END b[63]
  PIN b[64]
    DIRECTION OUTPUT ;
    USE SIGNAL ;
    PORT
      LAYER M4 ;
        RECT  0 78.912 0.084 78.936 ;
    END
  END b[64]
  PIN b[65]
    DIRECTION OUTPUT ;
    USE SIGNAL ;
    PORT
      LAYER M4 ;
        RECT  0 79.056 0.084 79.08 ;
    END
  END b[65]
  PIN b[66]
    DIRECTION OUTPUT ;
    USE SIGNAL ;
    PORT
      LAYER M4 ;
        RECT  0 79.2 0.084 79.224 ;
    END
  END b[66]
  PIN b[67]
    DIRECTION OUTPUT ;
    USE SIGNAL ;
    PORT
      LAYER M4 ;
        RECT  0 79.344 0.084 79.368 ;
    END
  END b[67]
  PIN b[68]
    DIRECTION OUTPUT ;
    USE SIGNAL ;
    PORT
      LAYER M4 ;
        RECT  0 79.488 0.084 79.512 ;
    END
  END b[68]
  PIN b[69]
    DIRECTION OUTPUT ;
    USE SIGNAL ;
    PORT
      LAYER M4 ;
        RECT  0 79.632 0.084 79.656 ;
    END
  END b[69]
  PIN b[6]
    DIRECTION OUTPUT ;
    USE SIGNAL ;
    PORT
      LAYER M4 ;
        RECT  0 32.544 0.084 32.568 ;
    END
  END b[6]
  PIN b[70]
    DIRECTION OUTPUT ;
    USE SIGNAL ;
    PORT
      LAYER M4 ;
        RECT  0 79.776 0.084 79.8 ;
    END
  END b[70]
  PIN b[71]
    DIRECTION OUTPUT ;
    USE SIGNAL ;
    PORT
      LAYER M4 ;
        RECT  0 79.92 0.084 79.944 ;
    END
  END b[71]
  PIN b[72]
    DIRECTION OUTPUT ;
    USE SIGNAL ;
    PORT
      LAYER M4 ;
        RECT  0 80.064 0.084 80.088 ;
    END
  END b[72]
  PIN b[73]
    DIRECTION OUTPUT ;
    USE SIGNAL ;
    PORT
      LAYER M4 ;
        RECT  0 80.208 0.084 80.232 ;
    END
  END b[73]
  PIN b[74]
    DIRECTION OUTPUT ;
    USE SIGNAL ;
    PORT
      LAYER M4 ;
        RECT  0 80.352 0.084 80.376 ;
    END
  END b[74]
  PIN b[75]
    DIRECTION OUTPUT ;
    USE SIGNAL ;
    PORT
      LAYER M4 ;
        RECT  0 80.496 0.084 80.52 ;
    END
  END b[75]
  PIN b[76]
    DIRECTION OUTPUT ;
    USE SIGNAL ;
    PORT
      LAYER M4 ;
        RECT  0 80.64 0.084 80.664 ;
    END
  END b[76]
  PIN b[77]
    DIRECTION OUTPUT ;
    USE SIGNAL ;
    PORT
      LAYER M4 ;
        RECT  0 80.784 0.084 80.808 ;
    END
  END b[77]
  PIN b[78]
    DIRECTION OUTPUT ;
    USE SIGNAL ;
    PORT
      LAYER M4 ;
        RECT  0 80.928 0.084 80.952 ;
    END
  END b[78]
  PIN b[79]
    DIRECTION OUTPUT ;
    USE SIGNAL ;
    PORT
      LAYER M4 ;
        RECT  0 81.072 0.084 81.096 ;
    END
  END b[79]
  PIN b[7]
    DIRECTION OUTPUT ;
    USE SIGNAL ;
    PORT
      LAYER M4 ;
        RECT  0 32.688 0.084 32.712 ;
    END
  END b[7]
  PIN b[80]
    DIRECTION OUTPUT ;
    USE SIGNAL ;
    PORT
      LAYER M4 ;
        RECT  0 81.216 0.084 81.24 ;
    END
  END b[80]
  PIN b[81]
    DIRECTION OUTPUT ;
    USE SIGNAL ;
    PORT
      LAYER M4 ;
        RECT  0 81.36 0.084 81.384 ;
    END
  END b[81]
  PIN b[82]
    DIRECTION OUTPUT ;
    USE SIGNAL ;
    PORT
      LAYER M4 ;
        RECT  0 81.504 0.084 81.528 ;
    END
  END b[82]
  PIN b[83]
    DIRECTION OUTPUT ;
    USE SIGNAL ;
    PORT
      LAYER M4 ;
        RECT  0 81.648 0.084 81.672 ;
    END
  END b[83]
  PIN b[84]
    DIRECTION OUTPUT ;
    USE SIGNAL ;
    PORT
      LAYER M4 ;
        RECT  0 81.792 0.084 81.816 ;
    END
  END b[84]
  PIN b[85]
    DIRECTION OUTPUT ;
    USE SIGNAL ;
    PORT
      LAYER M4 ;
        RECT  0 81.936 0.084 81.96 ;
    END
  END b[85]
  PIN b[86]
    DIRECTION OUTPUT ;
    USE SIGNAL ;
    PORT
      LAYER M4 ;
        RECT  0 82.08 0.084 82.104 ;
    END
  END b[86]
  PIN b[87]
    DIRECTION OUTPUT ;
    USE SIGNAL ;
    PORT
      LAYER M4 ;
        RECT  0 82.224 0.084 82.248 ;
    END
  END b[87]
  PIN b[88]
    DIRECTION OUTPUT ;
    USE SIGNAL ;
    PORT
      LAYER M4 ;
        RECT  0 82.368 0.084 82.392 ;
    END
  END b[88]
  PIN b[89]
    DIRECTION OUTPUT ;
    USE SIGNAL ;
    PORT
      LAYER M4 ;
        RECT  0 82.512 0.084 82.536 ;
    END
  END b[89]
  PIN b[8]
    DIRECTION OUTPUT ;
    USE SIGNAL ;
    PORT
      LAYER M4 ;
        RECT  0 32.832 0.084 32.856 ;
    END
  END b[8]
  PIN b[90]
    DIRECTION OUTPUT ;
    USE SIGNAL ;
    PORT
      LAYER M4 ;
        RECT  0 82.656 0.084 82.68 ;
    END
  END b[90]
  PIN b[91]
    DIRECTION OUTPUT ;
    USE SIGNAL ;
    PORT
      LAYER M4 ;
        RECT  0 82.8 0.084 82.824 ;
    END
  END b[91]
  PIN b[92]
    DIRECTION OUTPUT ;
    USE SIGNAL ;
    PORT
      LAYER M4 ;
        RECT  0 82.944 0.084 82.968 ;
    END
  END b[92]
  PIN b[93]
    DIRECTION OUTPUT ;
    USE SIGNAL ;
    PORT
      LAYER M4 ;
        RECT  0 83.088 0.084 83.112 ;
    END
  END b[93]
  PIN b[94]
    DIRECTION OUTPUT ;
    USE SIGNAL ;
    PORT
      LAYER M4 ;
        RECT  0 83.232 0.084 83.256 ;
    END
  END b[94]
  PIN b[95]
    DIRECTION OUTPUT ;
    USE SIGNAL ;
    PORT
      LAYER M4 ;
        RECT  0 83.376 0.084 83.4 ;
    END
  END b[95]
  PIN b[96]
    DIRECTION OUTPUT ;
    USE SIGNAL ;
    PORT
      LAYER M4 ;
        RECT  0 84.672 0.084 84.696 ;
    END
  END b[96]
  PIN b[97]
    DIRECTION OUTPUT ;
    USE SIGNAL ;
    PORT
      LAYER M4 ;
        RECT  0 84.816 0.084 84.84 ;
    END
  END b[97]
  PIN b[98]
    DIRECTION OUTPUT ;
    USE SIGNAL ;
    PORT
      LAYER M4 ;
        RECT  0 84.96 0.084 84.984 ;
    END
  END b[98]
  PIN b[99]
    DIRECTION OUTPUT ;
    USE SIGNAL ;
    PORT
      LAYER M4 ;
        RECT  0 85.104 0.084 85.128 ;
    END
  END b[99]
  PIN b[9]
    DIRECTION OUTPUT ;
    USE SIGNAL ;
    PORT
      LAYER M4 ;
        RECT  0 32.976 0.084 33 ;
    END
  END b[9]
  PIN ck
    DIRECTION INPUT ;
    USE SIGNAL ;
    PORT
      LAYER M3 ;
        RECT  37.908 170.603 37.926 170.64 ;
    END
  END ck
  PIN ck_s
    DIRECTION INPUT ;
    USE SIGNAL ;
    PORT
      LAYER M3 ;
        RECT  38.016 170.603 38.034 170.64 ;
    END
  END ck_s
  PIN en
    DIRECTION INPUT ;
    USE SIGNAL ;
    PORT
      LAYER M3 ;
        RECT  38.124 170.603 38.142 170.64 ;
    END
  END en
  PIN fault
    DIRECTION OUTPUT ;
    USE SIGNAL ;
    PORT
      LAYER M3 ;
        RECT  38.232 170.603 38.25 170.64 ;
    END
  END fault
  PIN k0
    DIRECTION INPUT ;
    USE SIGNAL ;
    PORT
      LAYER M3 ;
        RECT  38.34 170.603 38.358 170.64 ;
    END
  END k0
  PIN k1
    DIRECTION INPUT ;
    USE SIGNAL ;
    PORT
      LAYER M3 ;
        RECT  38.448 170.603 38.466 170.64 ;
    END
  END k1
  PIN k2
    DIRECTION INPUT ;
    USE SIGNAL ;
    PORT
      LAYER M3 ;
        RECT  38.556 170.603 38.574 170.64 ;
    END
  END k2
  PIN k3
    DIRECTION INPUT ;
    USE SIGNAL ;
    PORT
      LAYER M3 ;
        RECT  38.664 170.603 38.682 170.64 ;
    END
  END k3
  PIN rs
    DIRECTION INPUT ;
    USE SIGNAL ;
    PORT
      LAYER M3 ;
        RECT  38.772 170.603 38.79 170.64 ;
    END
  END rs
  PIN tie_hi
    DIRECTION OUTPUT ;
    USE SIGNAL ;
    PORT
      LAYER M3 ;
        RECT  38.88 170.603 38.898 170.64 ;
    END
  END tie_hi
  PIN tie_lo
    DIRECTION OUTPUT ;
    USE SIGNAL ;
    PORT
      LAYER M3 ;
        RECT  38.988 170.603 39.006 170.64 ;
    END
  END tie_lo
  PIN VDD
    DIRECTION INOUT ;
    USE POWER ;
    PORT
      LAYER M5 ;
        RECT  94.392 2.151 94.512 168.489 ;
        RECT  91.692 2.151 91.812 168.489 ;
        RECT  88.992 2.151 89.112 168.489 ;
        RECT  86.292 2.151 86.412 168.489 ;
        RECT  83.592 2.151 83.712 168.489 ;
        RECT  80.892 2.151 81.012 168.489 ;
        RECT  78.192 2.151 78.312 168.489 ;
        RECT  75.492 2.151 75.612 168.489 ;
        RECT  72.792 2.151 72.912 168.489 ;
        RECT  70.092 2.151 70.212 168.489 ;
        RECT  67.392 2.151 67.512 168.489 ;
        RECT  64.692 2.151 64.812 168.489 ;
        RECT  61.992 2.151 62.112 168.489 ;
        RECT  59.292 2.151 59.412 168.489 ;
        RECT  56.592 2.151 56.712 168.489 ;
        RECT  53.892 2.151 54.012 168.489 ;
        RECT  51.192 2.151 51.312 168.489 ;
        RECT  48.492 2.151 48.612 168.489 ;
        RECT  45.792 2.151 45.912 168.489 ;
        RECT  43.092 2.151 43.212 168.489 ;
        RECT  40.392 2.151 40.512 168.489 ;
        RECT  37.692 2.151 37.812 168.489 ;
        RECT  34.992 2.151 35.112 168.489 ;
        RECT  32.292 2.151 32.412 168.489 ;
        RECT  29.592 2.151 29.712 168.489 ;
        RECT  26.892 2.151 27.012 168.489 ;
        RECT  24.192 2.151 24.312 168.489 ;
        RECT  21.492 2.151 21.612 168.489 ;
        RECT  18.792 2.151 18.912 168.489 ;
        RECT  16.092 2.151 16.212 168.489 ;
        RECT  13.392 2.151 13.512 168.489 ;
        RECT  10.692 2.151 10.812 168.489 ;
        RECT  7.992 2.151 8.112 168.489 ;
        RECT  5.292 2.151 5.412 168.489 ;
        RECT  2.592 2.151 2.712 168.489 ;
    END
  END VDD
  PIN VSS
    DIRECTION INOUT ;
    USE GROUND ;
    PORT
      LAYER M5 ;
        RECT  94.2 2.137 94.32 168.503 ;
        RECT  91.5 2.137 91.62 168.503 ;
        RECT  88.8 2.137 88.92 168.503 ;
        RECT  86.1 2.137 86.22 168.503 ;
        RECT  83.4 2.137 83.52 168.503 ;
        RECT  80.7 2.137 80.82 168.503 ;
        RECT  78 2.137 78.12 168.503 ;
        RECT  75.3 2.137 75.42 168.503 ;
        RECT  72.6 2.137 72.72 168.503 ;
        RECT  69.9 2.137 70.02 168.503 ;
        RECT  67.2 2.137 67.32 168.503 ;
        RECT  64.5 2.137 64.62 168.503 ;
        RECT  61.8 2.137 61.92 168.503 ;
        RECT  59.1 2.137 59.22 168.503 ;
        RECT  56.4 2.137 56.52 168.503 ;
        RECT  53.7 2.137 53.82 168.503 ;
        RECT  51 2.137 51.12 168.503 ;
        RECT  48.3 2.137 48.42 168.503 ;
        RECT  45.6 2.137 45.72 168.503 ;
        RECT  42.9 2.137 43.02 168.503 ;
        RECT  40.2 2.137 40.32 168.503 ;
        RECT  37.5 2.137 37.62 168.503 ;
        RECT  34.8 2.137 34.92 168.503 ;
        RECT  32.1 2.137 32.22 168.503 ;
        RECT  29.4 2.137 29.52 168.503 ;
        RECT  26.7 2.137 26.82 168.503 ;
        RECT  24 2.137 24.12 168.503 ;
        RECT  21.3 2.137 21.42 168.503 ;
        RECT  18.6 2.137 18.72 168.503 ;
        RECT  15.9 2.137 16.02 168.503 ;
        RECT  13.2 2.137 13.32 168.503 ;
        RECT  10.5 2.137 10.62 168.503 ;
        RECT  7.8 2.137 7.92 168.503 ;
        RECT  5.1 2.137 5.22 168.503 ;
        RECT  2.4 2.137 2.52 168.503 ;
    END
  END VSS
  # OT_OBS_CLOSED layer=M5 d_um=1.536 added=114
  OBS
    LAYER RVTN ;
     RECT  2.16 2.16 96.12 2.295 ;
     RECT  2.16 2.565 96.12 2.835 ;
     RECT  2.16 3.105 96.12 3.375 ;
     RECT  2.16 3.645 96.12 3.915 ;
     RECT  2.16 4.185 96.12 4.455 ;
     RECT  2.16 4.725 96.12 4.995 ;
     RECT  2.16 5.265 96.12 5.535 ;
     RECT  2.16 5.805 96.12 6.075 ;
     RECT  2.16 6.345 96.12 6.615 ;
     RECT  2.16 6.885 96.12 7.155 ;
     RECT  2.16 7.425 96.12 7.695 ;
     RECT  2.16 7.965 96.12 8.235 ;
     RECT  2.16 8.505 96.12 8.775 ;
     RECT  2.16 9.045 96.12 9.315 ;
     RECT  2.16 9.585 96.12 9.855 ;
     RECT  2.16 10.125 96.12 10.395 ;
     RECT  2.16 10.665 96.12 10.935 ;
     RECT  2.16 11.205 96.12 11.475 ;
     RECT  2.16 11.745 96.12 12.015 ;
     RECT  2.16 12.285 96.12 12.555 ;
     RECT  2.16 12.825 96.12 13.095 ;
     RECT  2.16 13.365 96.12 13.635 ;
     RECT  2.16 13.905 96.12 14.175 ;
     RECT  2.16 14.445 96.12 14.715 ;
     RECT  2.16 14.985 96.12 15.255 ;
     RECT  2.16 15.525 96.12 15.795 ;
     RECT  2.16 16.065 96.12 16.335 ;
     RECT  2.16 16.605 96.12 16.875 ;
     RECT  2.16 17.145 96.12 17.415 ;
     RECT  2.16 17.685 96.12 17.955 ;
     RECT  2.16 18.225 96.12 18.495 ;
     RECT  2.16 18.765 96.12 19.035 ;
     RECT  2.16 19.305 96.12 19.575 ;
     RECT  2.16 19.845 96.12 20.115 ;
     RECT  2.16 20.385 96.12 20.655 ;
     RECT  2.16 20.925 96.12 21.195 ;
     RECT  2.16 21.465 96.12 21.735 ;
     RECT  2.16 22.005 96.12 22.275 ;
     RECT  2.16 22.545 96.12 22.815 ;
     RECT  2.16 23.085 96.12 23.355 ;
     RECT  2.16 23.625 96.12 23.895 ;
     RECT  2.16 24.165 96.12 24.435 ;
     RECT  2.16 24.705 96.12 24.975 ;
     RECT  2.16 25.245 96.12 25.515 ;
     RECT  2.16 25.785 96.12 26.055 ;
     RECT  2.16 26.325 96.12 26.595 ;
     RECT  2.16 26.865 96.12 27.135 ;
     RECT  2.16 27.405 96.12 27.675 ;
     RECT  2.16 27.945 96.12 28.215 ;
     RECT  2.16 28.485 96.12 28.755 ;
     RECT  2.16 29.025 96.12 29.295 ;
     RECT  2.16 29.565 96.12 29.835 ;
     RECT  2.16 30.105 96.12 30.375 ;
     RECT  2.16 30.645 96.12 30.915 ;
     RECT  2.16 31.185 96.12 31.455 ;
     RECT  2.16 31.725 96.12 31.995 ;
     RECT  2.16 32.265 96.12 32.535 ;
     RECT  2.16 32.805 96.12 33.075 ;
     RECT  2.16 33.345 96.12 33.615 ;
     RECT  2.16 33.885 96.12 34.155 ;
     RECT  2.16 34.425 96.12 34.695 ;
     RECT  2.16 34.965 96.12 35.235 ;
     RECT  2.16 35.505 96.12 35.775 ;
     RECT  2.16 36.045 96.12 36.315 ;
     RECT  2.16 36.585 96.12 36.855 ;
     RECT  2.16 37.125 96.12 37.395 ;
     RECT  2.16 37.665 96.12 37.935 ;
     RECT  2.16 38.205 96.12 38.475 ;
     RECT  2.16 38.745 96.12 39.015 ;
     RECT  2.16 39.285 96.12 39.555 ;
     RECT  2.16 39.825 96.12 40.095 ;
     RECT  2.16 40.365 96.12 40.635 ;
     RECT  2.16 40.905 96.12 41.04 ;
     RECT  2.16 41.04 41.148 41.175 ;
     RECT  77.22 41.04 96.12 41.175 ;
     RECT  2.16 41.445 41.148 41.715 ;
     RECT  77.22 41.445 96.12 41.715 ;
     RECT  2.16 41.985 41.148 42.255 ;
     RECT  77.22 41.985 96.12 42.255 ;
     RECT  2.16 42.525 41.148 42.795 ;
     RECT  77.22 42.525 96.12 42.795 ;
     RECT  2.16 43.065 41.148 43.335 ;
     RECT  77.22 43.065 96.12 43.335 ;
     RECT  2.16 43.605 41.148 43.875 ;
     RECT  77.22 43.605 96.12 43.875 ;
     RECT  2.16 44.145 41.148 44.415 ;
     RECT  77.22 44.145 96.12 44.415 ;
     RECT  2.16 44.685 41.148 44.955 ;
     RECT  77.22 44.685 96.12 44.955 ;
     RECT  2.16 45.225 41.148 45.495 ;
     RECT  77.22 45.225 96.12 45.495 ;
     RECT  2.16 45.765 41.148 46.035 ;
     RECT  77.22 45.765 96.12 46.035 ;
     RECT  2.16 46.305 41.148 46.575 ;
     RECT  77.22 46.305 96.12 46.575 ;
     RECT  2.16 46.845 41.148 47.115 ;
     RECT  77.22 46.845 96.12 47.115 ;
     RECT  2.16 47.385 41.148 47.655 ;
     RECT  77.22 47.385 96.12 47.655 ;
     RECT  2.16 47.925 41.148 48.195 ;
     RECT  77.22 47.925 96.12 48.195 ;
     RECT  2.16 48.465 41.148 48.735 ;
     RECT  77.22 48.465 96.12 48.735 ;
     RECT  2.16 49.005 41.148 49.275 ;
     RECT  77.22 49.005 96.12 49.275 ;
     RECT  2.16 49.545 41.148 49.815 ;
     RECT  77.22 49.545 96.12 49.815 ;
     RECT  2.16 50.085 41.148 50.355 ;
     RECT  77.22 50.085 96.12 50.355 ;
     RECT  2.16 50.625 41.148 50.895 ;
     RECT  77.22 50.625 96.12 50.895 ;
     RECT  2.16 51.165 41.148 51.435 ;
     RECT  77.22 51.165 96.12 51.435 ;
     RECT  2.16 51.705 41.148 51.975 ;
     RECT  77.22 51.705 96.12 51.975 ;
     RECT  2.16 52.245 41.148 52.515 ;
     RECT  77.22 52.245 96.12 52.515 ;
     RECT  2.16 52.785 41.148 53.055 ;
     RECT  77.22 52.785 96.12 53.055 ;
     RECT  2.16 53.325 41.148 53.595 ;
     RECT  77.22 53.325 96.12 53.595 ;
     RECT  2.16 53.865 41.148 54.135 ;
     RECT  77.22 53.865 96.12 54.135 ;
     RECT  2.16 54.405 41.148 54.675 ;
     RECT  77.22 54.405 96.12 54.675 ;
     RECT  2.16 54.945 41.148 55.215 ;
     RECT  77.22 54.945 96.12 55.215 ;
     RECT  2.16 55.485 41.148 55.755 ;
     RECT  77.22 55.485 96.12 55.755 ;
     RECT  2.16 56.025 41.148 56.295 ;
     RECT  77.22 56.025 96.12 56.295 ;
     RECT  2.16 56.565 41.148 56.835 ;
     RECT  77.22 56.565 96.12 56.835 ;
     RECT  2.16 57.105 41.148 57.375 ;
     RECT  77.22 57.105 96.12 57.375 ;
     RECT  2.16 57.645 41.148 57.915 ;
     RECT  77.22 57.645 96.12 57.915 ;
     RECT  2.16 58.185 41.148 58.455 ;
     RECT  77.22 58.185 96.12 58.455 ;
     RECT  2.16 58.725 41.148 58.995 ;
     RECT  77.22 58.725 96.12 58.995 ;
     RECT  2.16 59.265 41.148 59.535 ;
     RECT  77.22 59.265 96.12 59.535 ;
     RECT  2.16 59.805 41.148 60.075 ;
     RECT  77.22 59.805 96.12 60.075 ;
     RECT  2.16 60.345 41.148 60.615 ;
     RECT  77.22 60.345 96.12 60.615 ;
     RECT  2.16 60.885 41.148 61.155 ;
     RECT  77.22 60.885 96.12 61.155 ;
     RECT  2.16 61.425 41.148 61.695 ;
     RECT  77.22 61.425 96.12 61.695 ;
     RECT  2.16 61.965 41.148 62.235 ;
     RECT  77.22 61.965 96.12 62.235 ;
     RECT  2.16 62.505 41.148 62.64 ;
     RECT  77.22 62.505 96.12 62.64 ;
     RECT  2.16 62.64 96.12 62.775 ;
     RECT  2.16 63.045 96.12 63.315 ;
     RECT  2.16 63.585 96.12 63.855 ;
     RECT  2.16 64.125 96.12 64.395 ;
     RECT  2.16 64.665 96.12 64.935 ;
     RECT  2.16 65.205 96.12 65.475 ;
     RECT  2.16 65.745 96.12 66.015 ;
     RECT  2.16 66.285 96.12 66.555 ;
     RECT  2.16 66.825 96.12 67.095 ;
     RECT  2.16 67.365 96.12 67.635 ;
     RECT  2.16 67.905 96.12 68.175 ;
     RECT  2.16 68.445 96.12 68.715 ;
     RECT  2.16 68.985 96.12 69.255 ;
     RECT  2.16 69.525 96.12 69.795 ;
     RECT  2.16 70.065 96.12 70.335 ;
     RECT  2.16 70.605 96.12 70.875 ;
     RECT  2.16 71.145 96.12 71.415 ;
     RECT  2.16 71.685 96.12 71.955 ;
     RECT  2.16 72.225 96.12 72.495 ;
     RECT  2.16 72.765 96.12 73.035 ;
     RECT  2.16 73.305 96.12 73.575 ;
     RECT  2.16 73.845 96.12 74.115 ;
     RECT  2.16 74.385 96.12 74.655 ;
     RECT  2.16 74.925 96.12 75.195 ;
     RECT  2.16 75.465 96.12 75.735 ;
     RECT  2.16 76.005 96.12 76.275 ;
     RECT  2.16 76.545 96.12 76.815 ;
     RECT  2.16 77.085 96.12 77.355 ;
     RECT  2.16 77.625 96.12 77.895 ;
     RECT  2.16 78.165 96.12 78.435 ;
     RECT  2.16 78.705 96.12 78.975 ;
     RECT  2.16 79.245 96.12 79.515 ;
     RECT  2.16 79.785 96.12 80.055 ;
     RECT  2.16 80.325 96.12 80.595 ;
     RECT  2.16 80.865 96.12 81.135 ;
     RECT  2.16 81.405 96.12 81.675 ;
     RECT  2.16 81.945 96.12 82.215 ;
     RECT  2.16 82.485 96.12 82.755 ;
     RECT  2.16 83.025 96.12 83.295 ;
     RECT  2.16 83.565 96.12 83.835 ;
     RECT  2.16 84.105 96.12 84.24 ;
     RECT  2.16 84.24 41.148 84.375 ;
     RECT  77.22 84.24 96.12 84.375 ;
     RECT  2.16 84.645 41.148 84.915 ;
     RECT  77.22 84.645 96.12 84.915 ;
     RECT  2.16 85.185 41.148 85.455 ;
     RECT  77.22 85.185 96.12 85.455 ;
     RECT  2.16 85.725 41.148 85.995 ;
     RECT  77.22 85.725 96.12 85.995 ;
     RECT  2.16 86.265 41.148 86.535 ;
     RECT  77.22 86.265 96.12 86.535 ;
     RECT  2.16 86.805 41.148 87.075 ;
     RECT  77.22 86.805 96.12 87.075 ;
     RECT  2.16 87.345 41.148 87.615 ;
     RECT  77.22 87.345 96.12 87.615 ;
     RECT  2.16 87.885 41.148 88.155 ;
     RECT  77.22 87.885 96.12 88.155 ;
     RECT  2.16 88.425 41.148 88.695 ;
     RECT  77.22 88.425 96.12 88.695 ;
     RECT  2.16 88.965 41.148 89.235 ;
     RECT  77.22 88.965 96.12 89.235 ;
     RECT  2.16 89.505 41.148 89.775 ;
     RECT  77.22 89.505 96.12 89.775 ;
     RECT  2.16 90.045 41.148 90.315 ;
     RECT  77.22 90.045 96.12 90.315 ;
     RECT  2.16 90.585 41.148 90.855 ;
     RECT  77.22 90.585 96.12 90.855 ;
     RECT  2.16 91.125 41.148 91.395 ;
     RECT  77.22 91.125 96.12 91.395 ;
     RECT  2.16 91.665 41.148 91.935 ;
     RECT  77.22 91.665 96.12 91.935 ;
     RECT  2.16 92.205 41.148 92.475 ;
     RECT  77.22 92.205 96.12 92.475 ;
     RECT  2.16 92.745 41.148 93.015 ;
     RECT  77.22 92.745 96.12 93.015 ;
     RECT  2.16 93.285 41.148 93.555 ;
     RECT  77.22 93.285 96.12 93.555 ;
     RECT  2.16 93.825 41.148 94.095 ;
     RECT  77.22 93.825 96.12 94.095 ;
     RECT  2.16 94.365 41.148 94.635 ;
     RECT  77.22 94.365 96.12 94.635 ;
     RECT  2.16 94.905 41.148 95.175 ;
     RECT  77.22 94.905 96.12 95.175 ;
     RECT  2.16 95.445 41.148 95.715 ;
     RECT  77.22 95.445 96.12 95.715 ;
     RECT  2.16 95.985 41.148 96.255 ;
     RECT  77.22 95.985 96.12 96.255 ;
     RECT  2.16 96.525 41.148 96.795 ;
     RECT  77.22 96.525 96.12 96.795 ;
     RECT  2.16 97.065 41.148 97.335 ;
     RECT  77.22 97.065 96.12 97.335 ;
     RECT  2.16 97.605 41.148 97.875 ;
     RECT  77.22 97.605 96.12 97.875 ;
     RECT  2.16 98.145 41.148 98.415 ;
     RECT  77.22 98.145 96.12 98.415 ;
     RECT  2.16 98.685 41.148 98.955 ;
     RECT  77.22 98.685 96.12 98.955 ;
     RECT  2.16 99.225 41.148 99.495 ;
     RECT  77.22 99.225 96.12 99.495 ;
     RECT  2.16 99.765 41.148 100.035 ;
     RECT  77.22 99.765 96.12 100.035 ;
     RECT  2.16 100.305 41.148 100.575 ;
     RECT  77.22 100.305 96.12 100.575 ;
     RECT  2.16 100.845 41.148 101.115 ;
     RECT  77.22 100.845 96.12 101.115 ;
     RECT  2.16 101.385 41.148 101.655 ;
     RECT  77.22 101.385 96.12 101.655 ;
     RECT  2.16 101.925 41.148 102.195 ;
     RECT  77.22 101.925 96.12 102.195 ;
     RECT  2.16 102.465 41.148 102.735 ;
     RECT  77.22 102.465 96.12 102.735 ;
     RECT  2.16 103.005 41.148 103.275 ;
     RECT  77.22 103.005 96.12 103.275 ;
     RECT  2.16 103.545 41.148 103.815 ;
     RECT  77.22 103.545 96.12 103.815 ;
     RECT  2.16 104.085 41.148 104.355 ;
     RECT  77.22 104.085 96.12 104.355 ;
     RECT  2.16 104.625 41.148 104.895 ;
     RECT  77.22 104.625 96.12 104.895 ;
     RECT  2.16 105.165 41.148 105.435 ;
     RECT  77.22 105.165 96.12 105.435 ;
     RECT  2.16 105.705 41.148 105.84 ;
     RECT  77.22 105.705 96.12 105.84 ;
     RECT  2.16 105.84 96.12 105.975 ;
     RECT  2.16 106.245 96.12 106.515 ;
     RECT  2.16 106.785 96.12 107.055 ;
     RECT  2.16 107.325 96.12 107.595 ;
     RECT  2.16 107.865 96.12 108.135 ;
     RECT  2.16 108.405 96.12 108.675 ;
     RECT  2.16 108.945 96.12 109.215 ;
     RECT  2.16 109.485 96.12 109.755 ;
     RECT  2.16 110.025 96.12 110.295 ;
     RECT  2.16 110.565 96.12 110.835 ;
     RECT  2.16 111.105 96.12 111.375 ;
     RECT  2.16 111.645 96.12 111.915 ;
     RECT  2.16 112.185 96.12 112.455 ;
     RECT  2.16 112.725 96.12 112.995 ;
     RECT  2.16 113.265 96.12 113.535 ;
     RECT  2.16 113.805 96.12 114.075 ;
     RECT  2.16 114.345 96.12 114.615 ;
     RECT  2.16 114.885 96.12 115.155 ;
     RECT  2.16 115.425 96.12 115.695 ;
     RECT  2.16 115.965 96.12 116.235 ;
     RECT  2.16 116.505 96.12 116.775 ;
     RECT  2.16 117.045 96.12 117.315 ;
     RECT  2.16 117.585 96.12 117.855 ;
     RECT  2.16 118.125 96.12 118.395 ;
     RECT  2.16 118.665 96.12 118.935 ;
     RECT  2.16 119.205 96.12 119.475 ;
     RECT  2.16 119.745 96.12 120.015 ;
     RECT  2.16 120.285 96.12 120.555 ;
     RECT  2.16 120.825 96.12 121.095 ;
     RECT  2.16 121.365 96.12 121.635 ;
     RECT  2.16 121.905 96.12 122.175 ;
     RECT  2.16 122.445 96.12 122.715 ;
     RECT  2.16 122.985 96.12 123.255 ;
     RECT  2.16 123.525 96.12 123.795 ;
     RECT  2.16 124.065 96.12 124.335 ;
     RECT  2.16 124.605 96.12 124.875 ;
     RECT  2.16 125.145 96.12 125.415 ;
     RECT  2.16 125.685 96.12 125.955 ;
     RECT  2.16 126.225 96.12 126.495 ;
     RECT  2.16 126.765 96.12 127.035 ;
     RECT  2.16 127.305 96.12 127.44 ;
     RECT  2.16 127.44 41.148 127.575 ;
     RECT  77.22 127.44 96.12 127.575 ;
     RECT  2.16 127.845 41.148 128.115 ;
     RECT  77.22 127.845 96.12 128.115 ;
     RECT  2.16 128.385 41.148 128.655 ;
     RECT  77.22 128.385 96.12 128.655 ;
     RECT  2.16 128.925 41.148 129.195 ;
     RECT  77.22 128.925 96.12 129.195 ;
     RECT  2.16 129.465 41.148 129.735 ;
     RECT  77.22 129.465 96.12 129.735 ;
     RECT  2.16 130.005 41.148 130.275 ;
     RECT  77.22 130.005 96.12 130.275 ;
     RECT  2.16 130.545 41.148 130.815 ;
     RECT  77.22 130.545 96.12 130.815 ;
     RECT  2.16 131.085 41.148 131.355 ;
     RECT  77.22 131.085 96.12 131.355 ;
     RECT  2.16 131.625 41.148 131.895 ;
     RECT  77.22 131.625 96.12 131.895 ;
     RECT  2.16 132.165 41.148 132.435 ;
     RECT  77.22 132.165 96.12 132.435 ;
     RECT  2.16 132.705 41.148 132.975 ;
     RECT  77.22 132.705 96.12 132.975 ;
     RECT  2.16 133.245 41.148 133.515 ;
     RECT  77.22 133.245 96.12 133.515 ;
     RECT  2.16 133.785 41.148 134.055 ;
     RECT  77.22 133.785 96.12 134.055 ;
     RECT  2.16 134.325 41.148 134.595 ;
     RECT  77.22 134.325 96.12 134.595 ;
     RECT  2.16 134.865 41.148 135.135 ;
     RECT  77.22 134.865 96.12 135.135 ;
     RECT  2.16 135.405 41.148 135.675 ;
     RECT  77.22 135.405 96.12 135.675 ;
     RECT  2.16 135.945 41.148 136.215 ;
     RECT  77.22 135.945 96.12 136.215 ;
     RECT  2.16 136.485 41.148 136.755 ;
     RECT  77.22 136.485 96.12 136.755 ;
     RECT  2.16 137.025 41.148 137.295 ;
     RECT  77.22 137.025 96.12 137.295 ;
     RECT  2.16 137.565 41.148 137.835 ;
     RECT  77.22 137.565 96.12 137.835 ;
     RECT  2.16 138.105 41.148 138.375 ;
     RECT  77.22 138.105 96.12 138.375 ;
     RECT  2.16 138.645 41.148 138.915 ;
     RECT  77.22 138.645 96.12 138.915 ;
     RECT  2.16 139.185 41.148 139.455 ;
     RECT  77.22 139.185 96.12 139.455 ;
     RECT  2.16 139.725 41.148 139.995 ;
     RECT  77.22 139.725 96.12 139.995 ;
     RECT  2.16 140.265 41.148 140.535 ;
     RECT  77.22 140.265 96.12 140.535 ;
     RECT  2.16 140.805 41.148 141.075 ;
     RECT  77.22 140.805 96.12 141.075 ;
     RECT  2.16 141.345 41.148 141.615 ;
     RECT  77.22 141.345 96.12 141.615 ;
     RECT  2.16 141.885 41.148 142.155 ;
     RECT  77.22 141.885 96.12 142.155 ;
     RECT  2.16 142.425 41.148 142.695 ;
     RECT  77.22 142.425 96.12 142.695 ;
     RECT  2.16 142.965 41.148 143.235 ;
     RECT  77.22 142.965 96.12 143.235 ;
     RECT  2.16 143.505 41.148 143.775 ;
     RECT  77.22 143.505 96.12 143.775 ;
     RECT  2.16 144.045 41.148 144.315 ;
     RECT  77.22 144.045 96.12 144.315 ;
     RECT  2.16 144.585 41.148 144.855 ;
     RECT  77.22 144.585 96.12 144.855 ;
     RECT  2.16 145.125 41.148 145.395 ;
     RECT  77.22 145.125 96.12 145.395 ;
     RECT  2.16 145.665 41.148 145.935 ;
     RECT  77.22 145.665 96.12 145.935 ;
     RECT  2.16 146.205 41.148 146.475 ;
     RECT  77.22 146.205 96.12 146.475 ;
     RECT  2.16 146.745 41.148 147.015 ;
     RECT  77.22 146.745 96.12 147.015 ;
     RECT  2.16 147.285 41.148 147.555 ;
     RECT  77.22 147.285 96.12 147.555 ;
     RECT  2.16 147.825 41.148 148.095 ;
     RECT  77.22 147.825 96.12 148.095 ;
     RECT  2.16 148.365 41.148 148.635 ;
     RECT  77.22 148.365 96.12 148.635 ;
     RECT  2.16 148.905 41.148 149.04 ;
     RECT  77.22 148.905 96.12 149.04 ;
     RECT  2.16 149.04 96.12 149.175 ;
     RECT  2.16 149.445 96.12 149.715 ;
     RECT  2.16 149.985 96.12 150.255 ;
     RECT  2.16 150.525 96.12 150.795 ;
     RECT  2.16 151.065 96.12 151.335 ;
     RECT  2.16 151.605 96.12 151.875 ;
     RECT  2.16 152.145 96.12 152.415 ;
     RECT  2.16 152.685 96.12 152.955 ;
     RECT  2.16 153.225 96.12 153.495 ;
     RECT  2.16 153.765 96.12 154.035 ;
     RECT  2.16 154.305 96.12 154.575 ;
     RECT  2.16 154.845 96.12 155.115 ;
     RECT  2.16 155.385 96.12 155.655 ;
     RECT  2.16 155.925 96.12 156.195 ;
     RECT  2.16 156.465 96.12 156.735 ;
     RECT  2.16 157.005 96.12 157.275 ;
     RECT  2.16 157.545 96.12 157.815 ;
     RECT  2.16 158.085 96.12 158.355 ;
     RECT  2.16 158.625 96.12 158.895 ;
     RECT  2.16 159.165 96.12 159.435 ;
     RECT  2.16 159.705 96.12 159.975 ;
     RECT  2.16 160.245 96.12 160.515 ;
     RECT  2.16 160.785 96.12 161.055 ;
     RECT  2.16 161.325 96.12 161.595 ;
     RECT  2.16 161.865 96.12 162.135 ;
     RECT  2.16 162.405 96.12 162.675 ;
     RECT  2.16 162.945 96.12 163.215 ;
     RECT  2.16 163.485 96.12 163.755 ;
     RECT  2.16 164.025 96.12 164.295 ;
     RECT  2.16 164.565 96.12 164.835 ;
     RECT  2.16 165.105 96.12 165.375 ;
     RECT  2.16 165.645 96.12 165.915 ;
     RECT  2.16 166.185 96.12 166.455 ;
     RECT  2.16 166.725 96.12 166.995 ;
     RECT  2.16 167.265 96.12 167.535 ;
     RECT  2.16 167.805 96.12 168.075 ;
     RECT  2.16 168.345 96.12 168.48 ;
    LAYER RVTP ;
     RECT  2.16 2.295 96.12 2.565 ;
     RECT  2.16 2.835 96.12 3.105 ;
     RECT  2.16 3.375 96.12 3.645 ;
     RECT  2.16 3.915 96.12 4.185 ;
     RECT  2.16 4.455 96.12 4.725 ;
     RECT  2.16 4.995 96.12 5.265 ;
     RECT  2.16 5.535 96.12 5.805 ;
     RECT  2.16 6.075 96.12 6.345 ;
     RECT  2.16 6.615 96.12 6.885 ;
     RECT  2.16 7.155 96.12 7.425 ;
     RECT  2.16 7.695 96.12 7.965 ;
     RECT  2.16 8.235 96.12 8.505 ;
     RECT  2.16 8.775 96.12 9.045 ;
     RECT  2.16 9.315 96.12 9.585 ;
     RECT  2.16 9.855 96.12 10.125 ;
     RECT  2.16 10.395 96.12 10.665 ;
     RECT  2.16 10.935 96.12 11.205 ;
     RECT  2.16 11.475 96.12 11.745 ;
     RECT  2.16 12.015 96.12 12.285 ;
     RECT  2.16 12.555 96.12 12.825 ;
     RECT  2.16 13.095 96.12 13.365 ;
     RECT  2.16 13.635 96.12 13.905 ;
     RECT  2.16 14.175 96.12 14.445 ;
     RECT  2.16 14.715 96.12 14.985 ;
     RECT  2.16 15.255 96.12 15.525 ;
     RECT  2.16 15.795 96.12 16.065 ;
     RECT  2.16 16.335 96.12 16.605 ;
     RECT  2.16 16.875 96.12 17.145 ;
     RECT  2.16 17.415 96.12 17.685 ;
     RECT  2.16 17.955 96.12 18.225 ;
     RECT  2.16 18.495 96.12 18.765 ;
     RECT  2.16 19.035 96.12 19.305 ;
     RECT  2.16 19.575 96.12 19.845 ;
     RECT  2.16 20.115 96.12 20.385 ;
     RECT  2.16 20.655 96.12 20.925 ;
     RECT  2.16 21.195 96.12 21.465 ;
     RECT  2.16 21.735 96.12 22.005 ;
     RECT  2.16 22.275 96.12 22.545 ;
     RECT  2.16 22.815 96.12 23.085 ;
     RECT  2.16 23.355 96.12 23.625 ;
     RECT  2.16 23.895 96.12 24.165 ;
     RECT  2.16 24.435 96.12 24.705 ;
     RECT  2.16 24.975 96.12 25.245 ;
     RECT  2.16 25.515 96.12 25.785 ;
     RECT  2.16 26.055 96.12 26.325 ;
     RECT  2.16 26.595 96.12 26.865 ;
     RECT  2.16 27.135 96.12 27.405 ;
     RECT  2.16 27.675 96.12 27.945 ;
     RECT  2.16 28.215 96.12 28.485 ;
     RECT  2.16 28.755 96.12 29.025 ;
     RECT  2.16 29.295 96.12 29.565 ;
     RECT  2.16 29.835 96.12 30.105 ;
     RECT  2.16 30.375 96.12 30.645 ;
     RECT  2.16 30.915 96.12 31.185 ;
     RECT  2.16 31.455 96.12 31.725 ;
     RECT  2.16 31.995 96.12 32.265 ;
     RECT  2.16 32.535 96.12 32.805 ;
     RECT  2.16 33.075 96.12 33.345 ;
     RECT  2.16 33.615 96.12 33.885 ;
     RECT  2.16 34.155 96.12 34.425 ;
     RECT  2.16 34.695 96.12 34.965 ;
     RECT  2.16 35.235 96.12 35.505 ;
     RECT  2.16 35.775 96.12 36.045 ;
     RECT  2.16 36.315 96.12 36.585 ;
     RECT  2.16 36.855 96.12 37.125 ;
     RECT  2.16 37.395 96.12 37.665 ;
     RECT  2.16 37.935 96.12 38.205 ;
     RECT  2.16 38.475 96.12 38.745 ;
     RECT  2.16 39.015 96.12 39.285 ;
     RECT  2.16 39.555 96.12 39.825 ;
     RECT  2.16 40.095 96.12 40.365 ;
     RECT  2.16 40.635 96.12 40.905 ;
     RECT  2.16 41.175 41.148 41.445 ;
     RECT  77.22 41.175 96.12 41.445 ;
     RECT  2.16 41.715 41.148 41.985 ;
     RECT  77.22 41.715 96.12 41.985 ;
     RECT  2.16 42.255 41.148 42.525 ;
     RECT  77.22 42.255 96.12 42.525 ;
     RECT  2.16 42.795 41.148 43.065 ;
     RECT  77.22 42.795 96.12 43.065 ;
     RECT  2.16 43.335 41.148 43.605 ;
     RECT  77.22 43.335 96.12 43.605 ;
     RECT  2.16 43.875 41.148 44.145 ;
     RECT  77.22 43.875 96.12 44.145 ;
     RECT  2.16 44.415 41.148 44.685 ;
     RECT  77.22 44.415 96.12 44.685 ;
     RECT  2.16 44.955 41.148 45.225 ;
     RECT  77.22 44.955 96.12 45.225 ;
     RECT  2.16 45.495 41.148 45.765 ;
     RECT  77.22 45.495 96.12 45.765 ;
     RECT  2.16 46.035 41.148 46.305 ;
     RECT  77.22 46.035 96.12 46.305 ;
     RECT  2.16 46.575 41.148 46.845 ;
     RECT  77.22 46.575 96.12 46.845 ;
     RECT  2.16 47.115 41.148 47.385 ;
     RECT  77.22 47.115 96.12 47.385 ;
     RECT  2.16 47.655 41.148 47.925 ;
     RECT  77.22 47.655 96.12 47.925 ;
     RECT  2.16 48.195 41.148 48.465 ;
     RECT  77.22 48.195 96.12 48.465 ;
     RECT  2.16 48.735 41.148 49.005 ;
     RECT  77.22 48.735 96.12 49.005 ;
     RECT  2.16 49.275 41.148 49.545 ;
     RECT  77.22 49.275 96.12 49.545 ;
     RECT  2.16 49.815 41.148 50.085 ;
     RECT  77.22 49.815 96.12 50.085 ;
     RECT  2.16 50.355 41.148 50.625 ;
     RECT  77.22 50.355 96.12 50.625 ;
     RECT  2.16 50.895 41.148 51.165 ;
     RECT  77.22 50.895 96.12 51.165 ;
     RECT  2.16 51.435 41.148 51.705 ;
     RECT  77.22 51.435 96.12 51.705 ;
     RECT  2.16 51.975 41.148 52.245 ;
     RECT  77.22 51.975 96.12 52.245 ;
     RECT  2.16 52.515 41.148 52.785 ;
     RECT  77.22 52.515 96.12 52.785 ;
     RECT  2.16 53.055 41.148 53.325 ;
     RECT  77.22 53.055 96.12 53.325 ;
     RECT  2.16 53.595 41.148 53.865 ;
     RECT  77.22 53.595 96.12 53.865 ;
     RECT  2.16 54.135 41.148 54.405 ;
     RECT  77.22 54.135 96.12 54.405 ;
     RECT  2.16 54.675 41.148 54.945 ;
     RECT  77.22 54.675 96.12 54.945 ;
     RECT  2.16 55.215 41.148 55.485 ;
     RECT  77.22 55.215 96.12 55.485 ;
     RECT  2.16 55.755 41.148 56.025 ;
     RECT  77.22 55.755 96.12 56.025 ;
     RECT  2.16 56.295 41.148 56.565 ;
     RECT  77.22 56.295 96.12 56.565 ;
     RECT  2.16 56.835 41.148 57.105 ;
     RECT  77.22 56.835 96.12 57.105 ;
     RECT  2.16 57.375 41.148 57.645 ;
     RECT  77.22 57.375 96.12 57.645 ;
     RECT  2.16 57.915 41.148 58.185 ;
     RECT  77.22 57.915 96.12 58.185 ;
     RECT  2.16 58.455 41.148 58.725 ;
     RECT  77.22 58.455 96.12 58.725 ;
     RECT  2.16 58.995 41.148 59.265 ;
     RECT  77.22 58.995 96.12 59.265 ;
     RECT  2.16 59.535 41.148 59.805 ;
     RECT  77.22 59.535 96.12 59.805 ;
     RECT  2.16 60.075 41.148 60.345 ;
     RECT  77.22 60.075 96.12 60.345 ;
     RECT  2.16 60.615 41.148 60.885 ;
     RECT  77.22 60.615 96.12 60.885 ;
     RECT  2.16 61.155 41.148 61.425 ;
     RECT  77.22 61.155 96.12 61.425 ;
     RECT  2.16 61.695 41.148 61.965 ;
     RECT  77.22 61.695 96.12 61.965 ;
     RECT  2.16 62.235 41.148 62.505 ;
     RECT  77.22 62.235 96.12 62.505 ;
     RECT  2.16 62.775 96.12 63.045 ;
     RECT  2.16 63.315 96.12 63.585 ;
     RECT  2.16 63.855 96.12 64.125 ;
     RECT  2.16 64.395 96.12 64.665 ;
     RECT  2.16 64.935 96.12 65.205 ;
     RECT  2.16 65.475 96.12 65.745 ;
     RECT  2.16 66.015 96.12 66.285 ;
     RECT  2.16 66.555 96.12 66.825 ;
     RECT  2.16 67.095 96.12 67.365 ;
     RECT  2.16 67.635 96.12 67.905 ;
     RECT  2.16 68.175 96.12 68.445 ;
     RECT  2.16 68.715 96.12 68.985 ;
     RECT  2.16 69.255 96.12 69.525 ;
     RECT  2.16 69.795 96.12 70.065 ;
     RECT  2.16 70.335 96.12 70.605 ;
     RECT  2.16 70.875 96.12 71.145 ;
     RECT  2.16 71.415 96.12 71.685 ;
     RECT  2.16 71.955 96.12 72.225 ;
     RECT  2.16 72.495 96.12 72.765 ;
     RECT  2.16 73.035 96.12 73.305 ;
     RECT  2.16 73.575 96.12 73.845 ;
     RECT  2.16 74.115 96.12 74.385 ;
     RECT  2.16 74.655 96.12 74.925 ;
     RECT  2.16 75.195 96.12 75.465 ;
     RECT  2.16 75.735 96.12 76.005 ;
     RECT  2.16 76.275 96.12 76.545 ;
     RECT  2.16 76.815 96.12 77.085 ;
     RECT  2.16 77.355 96.12 77.625 ;
     RECT  2.16 77.895 96.12 78.165 ;
     RECT  2.16 78.435 96.12 78.705 ;
     RECT  2.16 78.975 96.12 79.245 ;
     RECT  2.16 79.515 96.12 79.785 ;
     RECT  2.16 80.055 96.12 80.325 ;
     RECT  2.16 80.595 96.12 80.865 ;
     RECT  2.16 81.135 96.12 81.405 ;
     RECT  2.16 81.675 96.12 81.945 ;
     RECT  2.16 82.215 96.12 82.485 ;
     RECT  2.16 82.755 96.12 83.025 ;
     RECT  2.16 83.295 96.12 83.565 ;
     RECT  2.16 83.835 96.12 84.105 ;
     RECT  2.16 84.375 41.148 84.645 ;
     RECT  77.22 84.375 96.12 84.645 ;
     RECT  2.16 84.915 41.148 85.185 ;
     RECT  77.22 84.915 96.12 85.185 ;
     RECT  2.16 85.455 41.148 85.725 ;
     RECT  77.22 85.455 96.12 85.725 ;
     RECT  2.16 85.995 41.148 86.265 ;
     RECT  77.22 85.995 96.12 86.265 ;
     RECT  2.16 86.535 41.148 86.805 ;
     RECT  77.22 86.535 96.12 86.805 ;
     RECT  2.16 87.075 41.148 87.345 ;
     RECT  77.22 87.075 96.12 87.345 ;
     RECT  2.16 87.615 41.148 87.885 ;
     RECT  77.22 87.615 96.12 87.885 ;
     RECT  2.16 88.155 41.148 88.425 ;
     RECT  77.22 88.155 96.12 88.425 ;
     RECT  2.16 88.695 41.148 88.965 ;
     RECT  77.22 88.695 96.12 88.965 ;
     RECT  2.16 89.235 41.148 89.505 ;
     RECT  77.22 89.235 96.12 89.505 ;
     RECT  2.16 89.775 41.148 90.045 ;
     RECT  77.22 89.775 96.12 90.045 ;
     RECT  2.16 90.315 41.148 90.585 ;
     RECT  77.22 90.315 96.12 90.585 ;
     RECT  2.16 90.855 41.148 91.125 ;
     RECT  77.22 90.855 96.12 91.125 ;
     RECT  2.16 91.395 41.148 91.665 ;
     RECT  77.22 91.395 96.12 91.665 ;
     RECT  2.16 91.935 41.148 92.205 ;
     RECT  77.22 91.935 96.12 92.205 ;
     RECT  2.16 92.475 41.148 92.745 ;
     RECT  77.22 92.475 96.12 92.745 ;
     RECT  2.16 93.015 41.148 93.285 ;
     RECT  77.22 93.015 96.12 93.285 ;
     RECT  2.16 93.555 41.148 93.825 ;
     RECT  77.22 93.555 96.12 93.825 ;
     RECT  2.16 94.095 41.148 94.365 ;
     RECT  77.22 94.095 96.12 94.365 ;
     RECT  2.16 94.635 41.148 94.905 ;
     RECT  77.22 94.635 96.12 94.905 ;
     RECT  2.16 95.175 41.148 95.445 ;
     RECT  77.22 95.175 96.12 95.445 ;
     RECT  2.16 95.715 41.148 95.985 ;
     RECT  77.22 95.715 96.12 95.985 ;
     RECT  2.16 96.255 41.148 96.525 ;
     RECT  77.22 96.255 96.12 96.525 ;
     RECT  2.16 96.795 41.148 97.065 ;
     RECT  77.22 96.795 96.12 97.065 ;
     RECT  2.16 97.335 41.148 97.605 ;
     RECT  77.22 97.335 96.12 97.605 ;
     RECT  2.16 97.875 41.148 98.145 ;
     RECT  77.22 97.875 96.12 98.145 ;
     RECT  2.16 98.415 41.148 98.685 ;
     RECT  77.22 98.415 96.12 98.685 ;
     RECT  2.16 98.955 41.148 99.225 ;
     RECT  77.22 98.955 96.12 99.225 ;
     RECT  2.16 99.495 41.148 99.765 ;
     RECT  77.22 99.495 96.12 99.765 ;
     RECT  2.16 100.035 41.148 100.305 ;
     RECT  77.22 100.035 96.12 100.305 ;
     RECT  2.16 100.575 41.148 100.845 ;
     RECT  77.22 100.575 96.12 100.845 ;
     RECT  2.16 101.115 41.148 101.385 ;
     RECT  77.22 101.115 96.12 101.385 ;
     RECT  2.16 101.655 41.148 101.925 ;
     RECT  77.22 101.655 96.12 101.925 ;
     RECT  2.16 102.195 41.148 102.465 ;
     RECT  77.22 102.195 96.12 102.465 ;
     RECT  2.16 102.735 41.148 103.005 ;
     RECT  77.22 102.735 96.12 103.005 ;
     RECT  2.16 103.275 41.148 103.545 ;
     RECT  77.22 103.275 96.12 103.545 ;
     RECT  2.16 103.815 41.148 104.085 ;
     RECT  77.22 103.815 96.12 104.085 ;
     RECT  2.16 104.355 41.148 104.625 ;
     RECT  77.22 104.355 96.12 104.625 ;
     RECT  2.16 104.895 41.148 105.165 ;
     RECT  77.22 104.895 96.12 105.165 ;
     RECT  2.16 105.435 41.148 105.705 ;
     RECT  77.22 105.435 96.12 105.705 ;
     RECT  2.16 105.975 96.12 106.245 ;
     RECT  2.16 106.515 96.12 106.785 ;
     RECT  2.16 107.055 96.12 107.325 ;
     RECT  2.16 107.595 96.12 107.865 ;
     RECT  2.16 108.135 96.12 108.405 ;
     RECT  2.16 108.675 96.12 108.945 ;
     RECT  2.16 109.215 96.12 109.485 ;
     RECT  2.16 109.755 96.12 110.025 ;
     RECT  2.16 110.295 96.12 110.565 ;
     RECT  2.16 110.835 96.12 111.105 ;
     RECT  2.16 111.375 96.12 111.645 ;
     RECT  2.16 111.915 96.12 112.185 ;
     RECT  2.16 112.455 96.12 112.725 ;
     RECT  2.16 112.995 96.12 113.265 ;
     RECT  2.16 113.535 96.12 113.805 ;
     RECT  2.16 114.075 96.12 114.345 ;
     RECT  2.16 114.615 96.12 114.885 ;
     RECT  2.16 115.155 96.12 115.425 ;
     RECT  2.16 115.695 96.12 115.965 ;
     RECT  2.16 116.235 96.12 116.505 ;
     RECT  2.16 116.775 96.12 117.045 ;
     RECT  2.16 117.315 96.12 117.585 ;
     RECT  2.16 117.855 96.12 118.125 ;
     RECT  2.16 118.395 96.12 118.665 ;
     RECT  2.16 118.935 96.12 119.205 ;
     RECT  2.16 119.475 96.12 119.745 ;
     RECT  2.16 120.015 96.12 120.285 ;
     RECT  2.16 120.555 96.12 120.825 ;
     RECT  2.16 121.095 96.12 121.365 ;
     RECT  2.16 121.635 96.12 121.905 ;
     RECT  2.16 122.175 96.12 122.445 ;
     RECT  2.16 122.715 96.12 122.985 ;
     RECT  2.16 123.255 96.12 123.525 ;
     RECT  2.16 123.795 96.12 124.065 ;
     RECT  2.16 124.335 96.12 124.605 ;
     RECT  2.16 124.875 96.12 125.145 ;
     RECT  2.16 125.415 96.12 125.685 ;
     RECT  2.16 125.955 96.12 126.225 ;
     RECT  2.16 126.495 96.12 126.765 ;
     RECT  2.16 127.035 96.12 127.305 ;
     RECT  2.16 127.575 41.148 127.845 ;
     RECT  77.22 127.575 96.12 127.845 ;
     RECT  2.16 128.115 41.148 128.385 ;
     RECT  77.22 128.115 96.12 128.385 ;
     RECT  2.16 128.655 41.148 128.925 ;
     RECT  77.22 128.655 96.12 128.925 ;
     RECT  2.16 129.195 41.148 129.465 ;
     RECT  77.22 129.195 96.12 129.465 ;
     RECT  2.16 129.735 41.148 130.005 ;
     RECT  77.22 129.735 96.12 130.005 ;
     RECT  2.16 130.275 41.148 130.545 ;
     RECT  77.22 130.275 96.12 130.545 ;
     RECT  2.16 130.815 41.148 131.085 ;
     RECT  77.22 130.815 96.12 131.085 ;
     RECT  2.16 131.355 41.148 131.625 ;
     RECT  77.22 131.355 96.12 131.625 ;
     RECT  2.16 131.895 41.148 132.165 ;
     RECT  77.22 131.895 96.12 132.165 ;
     RECT  2.16 132.435 41.148 132.705 ;
     RECT  77.22 132.435 96.12 132.705 ;
     RECT  2.16 132.975 41.148 133.245 ;
     RECT  77.22 132.975 96.12 133.245 ;
     RECT  2.16 133.515 41.148 133.785 ;
     RECT  77.22 133.515 96.12 133.785 ;
     RECT  2.16 134.055 41.148 134.325 ;
     RECT  77.22 134.055 96.12 134.325 ;
     RECT  2.16 134.595 41.148 134.865 ;
     RECT  77.22 134.595 96.12 134.865 ;
     RECT  2.16 135.135 41.148 135.405 ;
     RECT  77.22 135.135 96.12 135.405 ;
     RECT  2.16 135.675 41.148 135.945 ;
     RECT  77.22 135.675 96.12 135.945 ;
     RECT  2.16 136.215 41.148 136.485 ;
     RECT  77.22 136.215 96.12 136.485 ;
     RECT  2.16 136.755 41.148 137.025 ;
     RECT  77.22 136.755 96.12 137.025 ;
     RECT  2.16 137.295 41.148 137.565 ;
     RECT  77.22 137.295 96.12 137.565 ;
     RECT  2.16 137.835 41.148 138.105 ;
     RECT  77.22 137.835 96.12 138.105 ;
     RECT  2.16 138.375 41.148 138.645 ;
     RECT  77.22 138.375 96.12 138.645 ;
     RECT  2.16 138.915 41.148 139.185 ;
     RECT  77.22 138.915 96.12 139.185 ;
     RECT  2.16 139.455 41.148 139.725 ;
     RECT  77.22 139.455 96.12 139.725 ;
     RECT  2.16 139.995 41.148 140.265 ;
     RECT  77.22 139.995 96.12 140.265 ;
     RECT  2.16 140.535 41.148 140.805 ;
     RECT  77.22 140.535 96.12 140.805 ;
     RECT  2.16 141.075 41.148 141.345 ;
     RECT  77.22 141.075 96.12 141.345 ;
     RECT  2.16 141.615 41.148 141.885 ;
     RECT  77.22 141.615 96.12 141.885 ;
     RECT  2.16 142.155 41.148 142.425 ;
     RECT  77.22 142.155 96.12 142.425 ;
     RECT  2.16 142.695 41.148 142.965 ;
     RECT  77.22 142.695 96.12 142.965 ;
     RECT  2.16 143.235 41.148 143.505 ;
     RECT  77.22 143.235 96.12 143.505 ;
     RECT  2.16 143.775 41.148 144.045 ;
     RECT  77.22 143.775 96.12 144.045 ;
     RECT  2.16 144.315 41.148 144.585 ;
     RECT  77.22 144.315 96.12 144.585 ;
     RECT  2.16 144.855 41.148 145.125 ;
     RECT  77.22 144.855 96.12 145.125 ;
     RECT  2.16 145.395 41.148 145.665 ;
     RECT  77.22 145.395 96.12 145.665 ;
     RECT  2.16 145.935 41.148 146.205 ;
     RECT  77.22 145.935 96.12 146.205 ;
     RECT  2.16 146.475 41.148 146.745 ;
     RECT  77.22 146.475 96.12 146.745 ;
     RECT  2.16 147.015 41.148 147.285 ;
     RECT  77.22 147.015 96.12 147.285 ;
     RECT  2.16 147.555 41.148 147.825 ;
     RECT  77.22 147.555 96.12 147.825 ;
     RECT  2.16 148.095 41.148 148.365 ;
     RECT  77.22 148.095 96.12 148.365 ;
     RECT  2.16 148.635 41.148 148.905 ;
     RECT  77.22 148.635 96.12 148.905 ;
     RECT  2.16 149.175 96.12 149.445 ;
     RECT  2.16 149.715 96.12 149.985 ;
     RECT  2.16 150.255 96.12 150.525 ;
     RECT  2.16 150.795 96.12 151.065 ;
     RECT  2.16 151.335 96.12 151.605 ;
     RECT  2.16 151.875 96.12 152.145 ;
     RECT  2.16 152.415 96.12 152.685 ;
     RECT  2.16 152.955 96.12 153.225 ;
     RECT  2.16 153.495 96.12 153.765 ;
     RECT  2.16 154.035 96.12 154.305 ;
     RECT  2.16 154.575 96.12 154.845 ;
     RECT  2.16 155.115 96.12 155.385 ;
     RECT  2.16 155.655 96.12 155.925 ;
     RECT  2.16 156.195 96.12 156.465 ;
     RECT  2.16 156.735 96.12 157.005 ;
     RECT  2.16 157.275 96.12 157.545 ;
     RECT  2.16 157.815 96.12 158.085 ;
     RECT  2.16 158.355 96.12 158.625 ;
     RECT  2.16 158.895 96.12 159.165 ;
     RECT  2.16 159.435 96.12 159.705 ;
     RECT  2.16 159.975 96.12 160.245 ;
     RECT  2.16 160.515 96.12 160.785 ;
     RECT  2.16 161.055 96.12 161.325 ;
     RECT  2.16 161.595 96.12 161.865 ;
     RECT  2.16 162.135 96.12 162.405 ;
     RECT  2.16 162.675 96.12 162.945 ;
     RECT  2.16 163.215 96.12 163.485 ;
     RECT  2.16 163.755 96.12 164.025 ;
     RECT  2.16 164.295 96.12 164.565 ;
     RECT  2.16 164.835 96.12 165.105 ;
     RECT  2.16 165.375 96.12 165.645 ;
     RECT  2.16 165.915 96.12 166.185 ;
     RECT  2.16 166.455 96.12 166.725 ;
     RECT  2.16 166.995 96.12 167.265 ;
     RECT  2.16 167.535 96.12 167.805 ;
     RECT  2.16 168.075 96.12 168.345 ;
    LAYER M1 ;
     RECT  2.16 2.151 96.12 41.049 ;
     RECT  43.2 43.2 75.192 60.504 ;
     RECT  2.16 41.049 41.148 62.631 ;
     RECT  77.22 41.049 96.12 62.631 ;
     RECT  2.16 62.631 96.12 84.249 ;
     RECT  43.2 86.4 75.192 103.704 ;
     RECT  2.16 84.249 41.148 105.831 ;
     RECT  77.22 84.249 96.12 105.831 ;
     RECT  2.16 105.831 96.12 127.449 ;
     RECT  43.2 129.6 75.192 146.904 ;
     RECT  2.16 127.449 41.148 149.031 ;
     RECT  77.22 127.449 96.12 149.031 ;
     RECT  2.16 149.031 96.12 168.489 ;
    LAYER M2 ;
     RECT  0.103 83.106 0.203 83.394 ;
     RECT  0.103 121.338 0.203 122.274 ;
     RECT  0.203 83.106 0.275 83.286 ;
     RECT  0.203 121.338 0.275 122.166 ;
     RECT  0.103 32.85 0.535 33.678 ;
     RECT  0.103 44.388 0.535 44.406 ;
     RECT  0.103 82.026 0.535 82.044 ;
     RECT  0.275 83.106 0.535 83.124 ;
     RECT  0.103 85.428 0.535 85.446 ;
     RECT  0.103 35.316 2.155 35.874 ;
     RECT  0.535 31.626 2.16 33.678 ;
     RECT  0.535 34.506 2.16 34.524 ;
     RECT  2.155 35.316 2.16 36.036 ;
     RECT  0.103 40.986 2.16 42.084 ;
     RECT  0.535 43.146 2.16 44.406 ;
     RECT  0.103 80.298 2.16 80.694 ;
     RECT  0.535 81.486 2.16 83.124 ;
     RECT  0.535 85.266 2.16 85.446 ;
     RECT  0.103 86.616 2.16 88.794 ;
     RECT  0.275 121.338 2.16 121.896 ;
     RECT  37.831 170.586 37.903 170.604 ;
     RECT  37.903 170.514 38.003 170.604 ;
     RECT  38.003 170.586 38.651 170.604 ;
     RECT  2.16 2.151 41.148 168.489 ;
     RECT  41.148 85.158 41.315 85.176 ;
     RECT  41.148 102.906 41.351 102.924 ;
     RECT  41.148 90.63 41.387 90.648 ;
     RECT  41.148 58.086 41.423 58.374 ;
     RECT  41.148 86.04 41.423 89.496 ;
     RECT  41.423 88.668 41.459 89.496 ;
     RECT  41.148 94.338 41.495 100.494 ;
     RECT  41.148 44.046 41.531 54.054 ;
     RECT  41.148 137.646 41.531 142.722 ;
     RECT  41.531 44.046 41.567 52.974 ;
     RECT  41.531 53.838 41.567 54.054 ;
     RECT  41.567 54.036 41.603 54.054 ;
     RECT  41.148 131.796 41.603 131.814 ;
     RECT  41.531 140.076 41.603 142.722 ;
     RECT  41.567 44.046 41.639 50.454 ;
     RECT  41.148 105.831 41.639 128.034 ;
     RECT  41.531 137.646 41.639 139.212 ;
     RECT  41.639 44.046 41.675 47.142 ;
     RECT  41.675 47.088 41.711 47.142 ;
     RECT  41.148 129.132 41.711 129.294 ;
     RECT  41.675 45.54 41.747 46.26 ;
     RECT  41.495 94.338 41.783 98.514 ;
     RECT  41.148 55.116 41.891 56.394 ;
     RECT  41.148 130.518 41.891 130.77 ;
     RECT  41.148 103.788 41.899 104.616 ;
     RECT  41.891 55.116 41.963 56.214 ;
     RECT  41.495 99.396 41.963 100.494 ;
     RECT  41.963 99.396 41.999 100.134 ;
     RECT  41.423 86.04 42.035 87.876 ;
     RECT  41.999 99.396 42.071 99.954 ;
     RECT  42.071 99.396 42.107 99.684 ;
     RECT  42.107 99.396 42.143 99.522 ;
     RECT  41.639 48.204 42.179 50.454 ;
     RECT  41.783 94.338 42.179 94.86 ;
     RECT  41.783 95.616 42.179 98.514 ;
     RECT  41.891 130.554 42.179 130.77 ;
     RECT  41.603 140.076 42.179 140.634 ;
     RECT  41.711 47.124 42.215 47.142 ;
     RECT  42.179 48.438 42.215 50.454 ;
     RECT  42.179 94.338 42.215 94.626 ;
     RECT  41.148 136.026 42.215 136.674 ;
     RECT  41.639 137.808 42.215 139.212 ;
     RECT  41.603 141.516 42.215 142.722 ;
     RECT  41.148 144.666 42.215 144.684 ;
     RECT  41.675 44.046 42.251 44.784 ;
     RECT  42.215 48.708 42.251 50.454 ;
     RECT  42.215 94.608 42.251 94.626 ;
     RECT  42.251 44.766 42.287 44.784 ;
     RECT  42.251 48.906 42.287 50.454 ;
     RECT  41.567 51.246 42.467 52.974 ;
     RECT  42.035 87.66 42.475 87.876 ;
     RECT  41.459 88.668 42.475 89.262 ;
     RECT  42.179 98.496 42.583 98.514 ;
     RECT  41.899 103.788 42.691 104.922 ;
     RECT  41.639 105.831 42.691 127.449 ;
     RECT  41.148 62.631 42.727 84.249 ;
     RECT  42.287 49.248 42.835 50.454 ;
     RECT  42.179 95.724 42.979 97.524 ;
     RECT  41.963 55.116 43.051 55.674 ;
     RECT  43.015 92.826 43.051 92.844 ;
     RECT  42.215 138.114 43.051 139.212 ;
     RECT  41.148 149.031 43.051 168.489 ;
     RECT  41.148 147.06 43.123 147.888 ;
     RECT  43.051 148.761 43.151 168.489 ;
     RECT  41.148 42.732 43.2 43.164 ;
     RECT  41.747 45.54 43.2 45.558 ;
     RECT  42.835 49.248 43.2 50.814 ;
     RECT  42.467 51.984 43.2 52.974 ;
     RECT  43.051 54.72 43.2 55.674 ;
     RECT  41.423 58.356 43.2 58.374 ;
     RECT  41.148 60.552 43.2 61.65 ;
     RECT  42.035 86.04 43.2 86.724 ;
     RECT  42.475 87.66 43.2 89.262 ;
     RECT  43.051 92.826 43.2 93.51 ;
     RECT  42.979 95.652 43.2 97.524 ;
     RECT  42.583 98.496 43.2 98.604 ;
     RECT  42.143 99.504 43.2 99.522 ;
     RECT  42.691 103.788 43.2 127.449 ;
     RECT  41.711 129.24 43.2 129.294 ;
     RECT  42.215 136.026 43.2 136.044 ;
     RECT  43.051 138.114 43.2 139.248 ;
     RECT  42.179 140.616 43.2 140.634 ;
     RECT  42.215 141.516 43.2 141.714 ;
     RECT  42.215 142.47 43.2 142.722 ;
     RECT  43.123 146.952 43.2 147.888 ;
     RECT  43.2 129.24 48.451 147.888 ;
     RECT  43.151 148.878 48.451 168.489 ;
     RECT  42.727 62.55 50.459 84.249 ;
     RECT  43.2 86.04 72.967 127.449 ;
     RECT  72.967 85.968 74.155 127.449 ;
     RECT  74.155 85.968 74.407 127.494 ;
     RECT  48.451 129.24 74.659 168.489 ;
     RECT  41.148 2.151 74.947 41.049 ;
     RECT  74.407 85.968 74.947 127.566 ;
     RECT  43.2 42.732 75.192 61.65 ;
     RECT  74.947 85.968 75.192 127.719 ;
     RECT  74.659 128.781 75.192 168.489 ;
     RECT  50.459 62.586 75.271 84.249 ;
     RECT  75.192 128.781 75.271 129.339 ;
     RECT  74.947 2.151 75.335 41.13 ;
     RECT  75.192 47.898 75.335 47.988 ;
     RECT  75.192 96.876 75.335 98.91 ;
     RECT  75.192 142.506 75.335 142.524 ;
     RECT  75.335 47.898 75.407 47.916 ;
     RECT  75.192 58.698 75.407 58.986 ;
     RECT  75.192 91.17 75.407 91.188 ;
     RECT  75.271 128.7 75.407 129.339 ;
     RECT  75.192 42.732 75.443 43.164 ;
     RECT  75.271 62.586 75.443 84.33 ;
     RECT  75.192 146.448 75.479 168.489 ;
     RECT  75.192 85.968 75.587 86.364 ;
     RECT  75.192 103.788 75.623 127.719 ;
     RECT  75.407 129.132 75.695 129.339 ;
     RECT  75.192 88.506 75.803 88.794 ;
     RECT  75.443 62.586 75.839 84.249 ;
     RECT  75.623 103.788 75.875 127.566 ;
     RECT  75.192 134.532 75.911 134.784 ;
     RECT  75.192 130.356 75.983 131.994 ;
     RECT  75.192 52.794 76.063 54.63 ;
     RECT  75.335 97.272 76.063 98.91 ;
     RECT  75.192 139.968 76.063 140.994 ;
     RECT  75.192 60.552 76.091 61.65 ;
     RECT  75.983 130.446 76.091 131.994 ;
     RECT  75.192 48.906 76.135 50.454 ;
     RECT  76.063 52.794 76.135 55.278 ;
     RECT  76.063 96.534 76.171 98.91 ;
     RECT  76.171 96.534 76.207 99.054 ;
     RECT  76.135 89.856 76.235 89.874 ;
     RECT  76.091 130.518 76.271 131.994 ;
     RECT  76.135 48.168 76.279 50.454 ;
     RECT  76.063 90.9 76.279 90.918 ;
     RECT  75.587 85.968 76.315 85.986 ;
     RECT  76.279 90.9 76.315 91.584 ;
     RECT  75.192 92.412 76.315 92.43 ;
     RECT  75.192 94.032 76.315 95.166 ;
     RECT  75.911 134.604 76.315 134.784 ;
     RECT  75.192 135.612 76.315 137.358 ;
     RECT  75.192 87.156 76.351 87.174 ;
     RECT  76.279 47.736 76.387 50.454 ;
     RECT  76.135 52.794 76.387 55.512 ;
     RECT  76.315 90.9 76.387 92.43 ;
     RECT  76.315 93.906 76.387 95.166 ;
     RECT  76.207 96.534 76.387 99.486 ;
     RECT  75.695 129.132 76.387 129.294 ;
     RECT  76.271 130.986 76.387 131.994 ;
     RECT  76.315 134.604 76.387 137.358 ;
     RECT  76.387 128.862 76.423 129.294 ;
     RECT  76.387 51.75 76.639 55.512 ;
     RECT  76.063 139.968 76.639 141.57 ;
     RECT  76.243 133.83 76.963 133.848 ;
     RECT  76.387 134.604 76.963 138.87 ;
     RECT  76.963 133.83 77.215 138.87 ;
     RECT  76.639 139.968 77.215 141.606 ;
     RECT  75.335 2.151 77.22 41.049 ;
     RECT  77.215 41.796 77.22 41.814 ;
     RECT  75.443 42.732 77.22 43.092 ;
     RECT  75.192 45.306 77.22 45.324 ;
     RECT  75.192 46.656 77.22 46.944 ;
     RECT  76.387 47.736 77.22 50.85 ;
     RECT  76.639 51.75 77.22 55.548 ;
     RECT  76.207 56.34 77.22 56.358 ;
     RECT  75.407 58.968 77.22 58.986 ;
     RECT  76.091 60.552 77.22 61.614 ;
     RECT  75.839 62.631 77.22 84.249 ;
     RECT  76.315 85.77 77.22 85.986 ;
     RECT  76.351 86.886 77.22 87.174 ;
     RECT  76.243 89.478 77.22 89.496 ;
     RECT  76.387 90.9 77.22 99.486 ;
     RECT  76.639 101.592 77.22 101.61 ;
     RECT  75.875 103.788 77.22 127.449 ;
     RECT  76.423 128.322 77.22 129.294 ;
     RECT  76.387 130.986 77.22 132.354 ;
     RECT  77.215 133.83 77.22 141.606 ;
     RECT  76.099 142.47 77.22 142.488 ;
     RECT  76.675 144.486 77.22 144.504 ;
     RECT  75.479 146.952 77.22 168.489 ;
     RECT  77.22 2.151 96.12 168.489 ;
     RECT  96.12 39.636 96.323 43.596 ;
     RECT  96.12 38.718 96.359 38.736 ;
     RECT  96.323 39.636 96.359 40.734 ;
     RECT  96.12 52.794 96.359 54.972 ;
     RECT  96.359 52.794 96.395 53.586 ;
     RECT  96.323 41.49 96.935 43.596 ;
     RECT  96.395 52.794 96.935 53.01 ;
     RECT  96.12 99.738 97.331 100.566 ;
     RECT  96.359 39.636 97.475 39.816 ;
     RECT  96.12 81.918 97.475 81.936 ;
     RECT  96.12 83.646 97.475 85.446 ;
     RECT  96.12 97.308 97.475 97.326 ;
     RECT  96.12 98.388 97.475 98.406 ;
     RECT  97.331 99.738 97.475 99.756 ;
     RECT  97.331 100.548 97.475 100.566 ;
     RECT  96.12 140.508 97.475 141.606 ;
     RECT  97.475 39.636 97.511 39.654 ;
     RECT  96.359 40.716 97.511 40.734 ;
     RECT  96.935 41.49 97.511 43.326 ;
     RECT  96.935 52.992 97.511 53.01 ;
     RECT  96.359 54.486 97.511 54.972 ;
     RECT  96.12 56.268 97.511 56.286 ;
     RECT  97.511 43.038 97.547 43.326 ;
     RECT  97.511 54.486 97.547 54.504 ;
     RECT  97.547 43.308 97.583 43.326 ;
     RECT  98.167 53.604 98.267 53.622 ;
    LAYER M3 ;
     RECT  2.415 2.143 2.505 2.413 ;
     RECT  5.115 2.143 5.205 2.413 ;
     RECT  7.815 2.143 7.905 2.413 ;
     RECT  10.515 2.143 10.605 2.413 ;
     RECT  13.215 2.143 13.305 2.413 ;
     RECT  15.915 2.143 16.005 2.413 ;
     RECT  18.615 2.143 18.705 2.413 ;
     RECT  21.315 2.143 21.405 2.413 ;
     RECT  24.015 2.143 24.105 2.413 ;
     RECT  26.715 2.143 26.805 2.413 ;
     RECT  29.415 2.143 29.505 2.413 ;
     RECT  32.115 2.143 32.205 2.413 ;
     RECT  34.815 2.143 34.905 2.413 ;
     RECT  37.515 2.143 37.605 2.413 ;
     RECT  40.215 2.143 40.305 2.413 ;
     RECT  42.915 2.143 43.005 2.413 ;
     RECT  45.615 2.143 45.705 2.413 ;
     RECT  48.315 2.143 48.405 2.413 ;
     RECT  51.015 2.143 51.105 2.413 ;
     RECT  53.715 2.143 53.805 2.413 ;
     RECT  56.415 2.143 56.505 2.413 ;
     RECT  59.115 2.143 59.205 2.413 ;
     RECT  61.815 2.143 61.905 2.413 ;
     RECT  64.515 2.143 64.605 2.413 ;
     RECT  67.215 2.143 67.305 2.413 ;
     RECT  69.915 2.143 70.005 2.413 ;
     RECT  72.615 2.143 72.705 2.413 ;
     RECT  75.315 2.143 75.405 2.413 ;
     RECT  78.015 2.143 78.105 2.413 ;
     RECT  80.715 2.143 80.805 2.413 ;
     RECT  83.415 2.143 83.505 2.413 ;
     RECT  86.115 2.143 86.205 2.413 ;
     RECT  88.815 2.143 88.905 2.413 ;
     RECT  91.515 2.143 91.605 2.413 ;
     RECT  94.215 2.143 94.305 2.413 ;
     RECT  5.115 2.413 5.397 31.621 ;
     RECT  10.515 2.413 10.797 31.621 ;
     RECT  5.115 31.621 5.706 31.801 ;
     RECT  2.415 2.413 2.697 31.867 ;
     RECT  3.636 31.801 3.654 31.867 ;
     RECT  4.536 31.801 6.282 31.891 ;
     RECT  9.936 31.621 10.797 32.071 ;
     RECT  2.415 31.867 3.654 32.099 ;
     RECT  7.815 2.413 8.097 32.161 ;
     RECT  3.42 32.099 3.654 32.305 ;
     RECT  4.536 31.891 6.93 32.305 ;
     RECT  7.815 32.161 8.37 32.341 ;
     RECT  0.54 31.621 0.558 32.429 ;
     RECT  3.42 32.305 6.93 32.495 ;
     RECT  37.515 2.413 37.797 32.773 ;
     RECT  39.024 32.341 39.042 32.773 ;
     RECT  7.815 32.341 8.55 32.881 ;
     RECT  9.468 32.071 10.797 32.881 ;
     RECT  2.415 32.099 2.697 32.971 ;
     RECT  2.304 32.971 2.697 33.008 ;
     RECT  7.308 32.881 8.55 33.043 ;
     RECT  2.415 33.008 2.697 33.151 ;
     RECT  3.42 32.495 6.318 33.151 ;
     RECT  37.515 32.773 39.042 33.313 ;
     RECT  7.308 33.043 8.622 33.349 ;
     RECT  2.415 33.151 6.318 33.385 ;
     RECT  7.164 33.349 8.622 33.583 ;
     RECT  9.396 32.881 10.797 33.583 ;
     RECT  2.415 33.385 6.39 33.691 ;
     RECT  7.164 33.583 10.797 33.691 ;
     RECT  0.108 32.683 0.162 33.725 ;
     RECT  2.415 33.691 10.797 33.781 ;
     RECT  34.815 2.413 35.097 33.781 ;
     RECT  2.415 33.781 10.926 33.953 ;
     RECT  0.144 33.725 0.162 34.109 ;
     RECT  2.415 33.953 10.797 34.421 ;
     RECT  0.54 34.501 0.558 34.589 ;
     RECT  37.515 33.313 39.114 34.663 ;
     RECT  40.215 2.413 40.497 34.663 ;
     RECT  4.356 34.421 10.797 34.691 ;
     RECT  0.144 34.843 0.162 34.973 ;
     RECT  2.415 34.421 3.582 35.231 ;
     RECT  2.415 35.231 3.51 35.563 ;
     RECT  2.304 35.563 3.51 35.851 ;
     RECT  2.16 35.851 3.51 36.041 ;
     RECT  2.415 36.041 3.51 36.121 ;
     RECT  4.356 34.691 8.622 36.121 ;
     RECT  2.415 36.121 8.622 36.239 ;
     RECT  0.108 35.131 0.126 36.269 ;
     RECT  37.515 34.663 40.497 36.751 ;
     RECT  4.392 36.239 8.622 36.779 ;
     RECT  95.364 37.963 95.382 38.101 ;
     RECT  95.364 38.101 95.922 38.155 ;
     RECT  94.215 2.413 94.497 38.371 ;
     RECT  95.22 38.155 95.922 38.371 ;
     RECT  94.215 38.371 95.922 38.713 ;
     RECT  91.515 2.413 91.797 38.779 ;
     RECT  94.215 38.713 96.354 38.821 ;
     RECT  4.464 36.779 8.622 39.047 ;
     RECT  91.515 38.779 92.214 39.055 ;
     RECT  5.115 39.047 8.622 39.083 ;
     RECT  90.648 38.983 90.666 39.091 ;
     RECT  91.515 39.055 92.61 39.091 ;
     RECT  94.032 38.821 96.354 39.091 ;
     RECT  75.315 2.413 75.597 39.181 ;
     RECT  91.512 39.091 92.61 39.181 ;
     RECT  93.924 39.091 96.354 39.209 ;
     RECT  88.815 2.413 89.097 39.217 ;
     RECT  86.115 2.413 86.397 39.289 ;
     RECT  90.432 39.091 90.666 39.289 ;
     RECT  91.512 39.181 93.078 39.289 ;
     RECT  94.068 39.209 96.354 39.341 ;
     RECT  83.415 2.413 83.697 39.361 ;
     RECT  82.08 39.181 82.098 39.451 ;
     RECT  82.08 39.451 82.674 39.479 ;
     RECT  88.815 39.217 89.514 39.479 ;
     RECT  82.656 39.479 82.674 39.487 ;
     RECT  83.415 39.361 84.222 39.487 ;
     RECT  82.656 39.487 84.222 39.515 ;
     RECT  82.656 39.515 83.697 39.587 ;
     RECT  2.415 36.239 3.51 39.623 ;
     RECT  75.315 39.181 75.834 39.631 ;
     RECT  6.3 39.083 8.622 39.659 ;
     RECT  97.488 39.451 97.506 39.659 ;
     RECT  37.515 36.751 40.77 39.721 ;
     RECT  82.728 39.587 83.697 39.749 ;
     RECT  97.452 39.739 97.47 39.821 ;
     RECT  75.315 39.631 76.014 39.865 ;
     RECT  90.252 39.289 93.078 39.883 ;
     RECT  84.6 39.901 84.618 40.019 ;
     RECT  94.068 39.341 95.922 40.027 ;
     RECT  5.115 39.083 5.397 40.219 ;
     RECT  78.015 2.413 78.297 40.261 ;
     RECT  85.356 39.595 85.374 40.297 ;
     RECT  3.42 39.623 3.51 40.36 ;
     RECT  4.5 40.219 5.397 40.36 ;
     RECT  84.708 40.297 85.374 40.369 ;
     RECT  86.115 39.289 86.922 40.369 ;
     RECT  3.42 40.36 5.397 40.397 ;
     RECT  78.015 40.261 78.642 40.397 ;
     RECT  12.24 40.267 12.258 40.441 ;
     RECT  13.215 2.413 13.497 40.441 ;
     RECT  75.168 39.865 76.014 40.441 ;
     RECT  93.888 40.027 95.922 40.441 ;
     RECT  89.928 39.883 93.078 40.445 ;
     RECT  84.708 40.369 86.922 40.469 ;
     RECT  93.888 40.441 96.354 40.469 ;
     RECT  93.996 40.469 96.354 40.493 ;
     RECT  45.615 2.413 45.897 40.531 ;
     RECT  45.615 40.531 46.602 40.555 ;
     RECT  79.812 40.333 79.83 40.559 ;
     RECT  84.852 40.469 86.922 40.559 ;
     RECT  6.3 39.659 6.318 40.567 ;
     RECT  7.056 39.659 8.622 40.567 ;
     RECT  12.24 40.441 13.497 40.589 ;
     RECT  21.315 2.413 21.597 40.603 ;
     RECT  29.415 2.413 29.697 40.603 ;
     RECT  34.815 33.781 35.622 40.603 ;
     RECT  12.528 40.589 13.497 40.637 ;
     RECT  80.715 2.413 80.997 40.639 ;
     RECT  64.515 2.413 64.797 40.711 ;
     RECT  75.168 40.441 76.086 40.711 ;
     RECT  14.832 40.603 14.85 40.733 ;
     RECT  21.315 40.603 21.69 40.733 ;
     RECT  22.824 40.603 22.842 40.733 ;
     RECT  29.415 40.603 29.79 40.733 ;
     RECT  30.78 40.603 30.798 40.733 ;
     RECT  84.852 40.559 85.338 40.739 ;
     RECT  59.115 2.413 59.397 40.747 ;
     RECT  64.515 40.711 65.538 40.781 ;
     RECT  42.915 2.413 43.197 40.787 ;
     RECT  45.615 40.555 46.89 40.787 ;
     RECT  48.315 2.413 48.597 40.787 ;
     RECT  51.015 2.413 51.297 40.787 ;
     RECT  53.715 2.413 53.997 40.787 ;
     RECT  56.415 2.413 56.697 40.787 ;
     RECT  58.68 40.747 59.397 40.787 ;
     RECT  61.815 2.413 62.097 40.787 ;
     RECT  64.515 40.781 64.797 40.787 ;
     RECT  67.215 2.413 67.497 40.787 ;
     RECT  69.915 2.413 70.197 40.787 ;
     RECT  72.615 2.413 72.897 40.787 ;
     RECT  57.42 40.711 57.438 40.801 ;
     RECT  46.584 40.787 46.89 40.829 ;
     RECT  65.52 40.781 65.538 40.829 ;
     RECT  82.656 40.801 82.674 40.837 ;
     RECT  34.776 40.603 35.622 40.877 ;
     RECT  46.584 40.829 46.602 40.877 ;
     RECT  57.384 40.801 57.546 40.877 ;
     RECT  58.68 40.787 59.205 40.877 ;
     RECT  67.215 40.787 67.305 40.891 ;
     RECT  2.415 39.623 2.697 40.909 ;
     RECT  3.42 40.397 3.51 40.909 ;
     RECT  57.528 40.877 57.546 40.925 ;
     RECT  82.08 40.837 82.674 40.937 ;
     RECT  85.14 40.739 85.338 40.937 ;
     RECT  75.168 40.711 76.23 40.945 ;
     RECT  4.5 40.397 5.397 40.981 ;
     RECT  6.3 40.567 8.622 40.981 ;
     RECT  66.744 40.891 67.305 41.009 ;
     RECT  85.14 40.937 85.158 41.009 ;
     RECT  2.415 40.909 3.51 41.035 ;
     RECT  42.915 40.787 43.11 41.057 ;
     RECT  45.615 40.787 45.705 41.057 ;
     RECT  48.315 40.787 48.405 41.057 ;
     RECT  51.015 40.787 51.105 41.057 ;
     RECT  53.715 40.787 53.805 41.057 ;
     RECT  56.415 40.787 56.505 41.057 ;
     RECT  59.115 40.877 59.205 41.057 ;
     RECT  61.815 40.787 61.905 41.057 ;
     RECT  64.515 40.787 64.605 41.057 ;
     RECT  67.215 41.009 67.305 41.057 ;
     RECT  69.915 40.787 70.005 41.057 ;
     RECT  72.615 40.787 72.705 41.057 ;
     RECT  2.304 41.035 3.51 41.099 ;
     RECT  82.08 40.937 82.098 41.099 ;
     RECT  74.952 40.945 76.23 41.135 ;
     RECT  75.168 41.135 76.23 41.165 ;
     RECT  90.072 40.445 93.078 41.279 ;
     RECT  97.488 40.711 97.506 41.323 ;
     RECT  90.396 41.279 93.078 41.341 ;
     RECT  93.996 40.493 96.318 41.341 ;
     RECT  4.5 40.981 8.622 41.449 ;
     RECT  97.488 41.323 97.542 41.467 ;
     RECT  2.415 41.099 3.51 41.521 ;
     RECT  4.248 41.449 8.622 41.521 ;
     RECT  0.108 40.891 0.126 41.611 ;
     RECT  90.396 41.341 96.318 41.711 ;
     RECT  9.396 34.691 10.797 41.881 ;
     RECT  80.064 40.639 80.997 41.989 ;
     RECT  81.792 41.611 81.81 41.989 ;
     RECT  88.815 39.479 89.097 41.989 ;
     RECT  90.396 41.711 95.922 42.025 ;
     RECT  9.36 41.881 10.797 42.061 ;
     RECT  86.115 40.559 86.922 42.061 ;
     RECT  88.488 41.989 89.097 42.061 ;
     RECT  90.072 42.025 95.922 42.061 ;
     RECT  0.108 41.611 0.162 42.089 ;
     RECT  2.415 41.521 8.622 42.151 ;
     RECT  9.36 42.061 11.106 42.151 ;
     RECT  2.415 42.151 11.106 42.179 ;
     RECT  88.488 42.061 95.922 42.179 ;
     RECT  88.815 42.179 95.922 42.221 ;
     RECT  85.644 42.061 86.922 42.295 ;
     RECT  85.5 42.295 87.318 42.421 ;
     RECT  97.488 41.467 97.578 42.475 ;
     RECT  90.072 42.221 95.922 42.485 ;
     RECT  85.5 42.421 87.426 42.557 ;
     RECT  86.115 42.557 87.426 42.565 ;
     RECT  90.252 42.485 95.922 42.565 ;
     RECT  78.015 40.397 78.297 42.601 ;
     RECT  83.415 39.749 83.697 42.601 ;
     RECT  90.252 42.565 96.174 42.605 ;
     RECT  0.144 42.089 0.162 42.653 ;
     RECT  90.324 42.605 96.174 42.674 ;
     RECT  86.115 42.565 87.75 42.719 ;
     RECT  90.324 42.674 95.922 42.719 ;
     RECT  37.515 39.721 40.842 42.727 ;
     RECT  83.34 42.601 83.697 42.727 ;
     RECT  78.015 42.601 78.678 42.755 ;
     RECT  86.115 42.719 87.642 42.755 ;
     RECT  90.324 42.719 95.814 42.755 ;
     RECT  90.396 42.755 95.814 42.797 ;
     RECT  2.415 42.179 3.582 42.899 ;
     RECT  3.456 42.899 3.582 42.955 ;
     RECT  4.32 42.179 11.106 42.955 ;
     RECT  90.396 42.797 95.382 42.989 ;
     RECT  77.22 41.791 77.238 43.069 ;
     RECT  78.015 42.755 78.297 43.069 ;
     RECT  34.815 40.877 35.622 43.133 ;
     RECT  90.396 42.989 95.202 43.133 ;
     RECT  43.056 41.057 43.11 43.2 ;
     RECT  70.704 43.069 70.722 43.2 ;
     RECT  75.204 41.165 76.23 43.2 ;
     RECT  96.912 42.475 97.578 43.331 ;
     RECT  0.54 43.141 0.558 43.387 ;
     RECT  0.144 43.387 0.558 43.517 ;
     RECT  96.912 43.331 96.93 43.601 ;
     RECT  86.115 42.755 86.922 43.681 ;
     RECT  90.396 43.133 94.986 43.709 ;
     RECT  88.815 42.221 89.262 43.771 ;
     RECT  0.54 43.517 0.558 43.805 ;
     RECT  88.596 43.771 89.262 43.871 ;
     RECT  3.456 42.955 11.106 43.915 ;
     RECT  34.815 43.133 35.097 43.915 ;
     RECT  91.404 43.709 94.986 43.915 ;
     RECT  91.404 43.915 95.094 44.041 ;
     RECT  90.396 43.709 90.666 44.059 ;
     RECT  3.42 43.915 11.106 44.069 ;
     RECT  34.776 43.915 35.097 44.069 ;
     RECT  91.404 44.041 95.202 44.093 ;
     RECT  91.404 44.093 95.094 44.105 ;
     RECT  77.22 43.069 78.297 44.107 ;
     RECT  42.228 44.041 42.246 44.113 ;
     RECT  37.515 42.727 40.914 44.155 ;
     RECT  42.192 44.113 42.246 44.155 ;
     RECT  83.016 42.727 83.697 44.155 ;
     RECT  2.415 42.899 2.697 44.203 ;
     RECT  77.22 44.107 78.678 44.203 ;
     RECT  83.016 44.155 83.826 44.339 ;
     RECT  80.064 41.989 81.81 44.347 ;
     RECT  80.064 44.347 82.098 44.384 ;
     RECT  0.108 44.347 0.342 44.411 ;
     RECT  83.016 44.339 83.697 44.419 ;
     RECT  3.456 44.069 11.106 44.483 ;
     RECT  90.072 44.059 90.666 44.519 ;
     RECT  88.815 43.871 89.262 44.609 ;
     RECT  90.108 44.519 90.666 44.609 ;
     RECT  0.324 44.411 0.342 44.669 ;
     RECT  43.056 43.2 76.23 44.669 ;
     RECT  77.22 44.203 78.786 44.717 ;
     RECT  10.224 44.483 11.106 44.753 ;
     RECT  37.515 44.155 42.246 44.761 ;
     RECT  85.752 43.681 86.922 44.761 ;
     RECT  77.22 44.717 78.678 44.909 ;
     RECT  2.304 44.203 2.697 44.923 ;
     RECT  3.456 44.483 9.45 44.923 ;
     RECT  90.396 44.609 90.666 44.959 ;
     RECT  91.404 44.105 94.497 44.959 ;
     RECT  85.752 44.761 87.246 44.987 ;
     RECT  2.304 44.923 9.45 45.329 ;
     RECT  87.228 44.987 87.246 45.329 ;
     RECT  2.304 45.329 2.697 45.419 ;
     RECT  37.515 44.761 42.282 45.533 ;
     RECT  43.2 44.669 76.23 45.535 ;
     RECT  80.064 44.384 81.81 45.725 ;
     RECT  3.456 45.329 9.45 45.869 ;
     RECT  42.768 45.535 76.23 45.917 ;
     RECT  90.396 44.959 94.497 45.959 ;
     RECT  90.396 45.959 92.034 46.013 ;
     RECT  3.492 45.869 9.45 46.031 ;
     RECT  80.1 45.725 81.81 46.219 ;
     RECT  82.692 44.419 83.697 46.219 ;
     RECT  80.1 46.219 83.697 46.265 ;
     RECT  77.22 44.909 78.39 46.267 ;
     RECT  85.752 44.987 86.397 46.267 ;
     RECT  77.22 46.267 78.678 46.301 ;
     RECT  91.008 46.013 92.034 46.301 ;
     RECT  42.768 45.917 76.158 46.397 ;
     RECT  80.1 46.265 81.774 46.493 ;
     RECT  77.796 46.301 78.678 46.747 ;
     RECT  93.312 45.959 94.497 46.769 ;
     RECT  91.116 46.301 92.034 46.921 ;
     RECT  77.796 46.747 78.894 47.047 ;
     RECT  82.692 46.265 83.697 47.047 ;
     RECT  84.78 43.951 84.798 47.047 ;
     RECT  91.116 46.921 92.358 47.069 ;
     RECT  3.492 46.031 8.838 47.075 ;
     RECT  4.104 47.075 8.838 47.083 ;
     RECT  34.815 44.069 35.097 47.083 ;
     RECT  10.515 44.753 11.106 47.111 ;
     RECT  85.752 46.267 86.67 47.117 ;
     RECT  37.515 45.533 41.742 47.119 ;
     RECT  91.116 47.069 91.998 47.119 ;
     RECT  90.792 47.119 91.998 47.165 ;
     RECT  13.215 40.637 13.497 47.191 ;
     RECT  93.312 46.769 93.33 47.191 ;
     RECT  86.115 47.117 86.67 47.219 ;
     RECT  92.736 47.191 93.33 47.309 ;
     RECT  77.796 47.047 78.93 47.323 ;
     RECT  82.692 47.047 84.798 47.405 ;
     RECT  37.515 47.119 42.21 47.453 ;
     RECT  77.796 47.323 79.47 47.453 ;
     RECT  92.844 47.309 93.33 47.453 ;
     RECT  84.78 47.405 84.798 47.645 ;
     RECT  34.776 47.083 35.097 47.687 ;
     RECT  43.2 46.397 76.158 47.731 ;
     RECT  4.104 47.083 9.162 47.759 ;
     RECT  94.176 46.769 94.497 47.803 ;
     RECT  93.456 47.803 94.497 47.849 ;
     RECT  43.2 47.731 76.302 47.857 ;
     RECT  80.715 46.493 81.774 47.885 ;
     RECT  79.452 47.453 79.47 47.891 ;
     RECT  91.116 47.165 91.998 48.163 ;
     RECT  37.515 47.453 41.706 48.187 ;
     RECT  4.104 47.759 8.097 48.191 ;
     RECT  77.796 47.453 78.297 48.271 ;
     RECT  43.2 47.857 76.338 48.361 ;
     RECT  4.212 48.191 8.097 48.389 ;
     RECT  37.515 48.187 42.174 48.433 ;
     RECT  8.82 47.759 9.162 48.569 ;
     RECT  34.815 47.687 35.097 48.703 ;
     RECT  37.515 48.433 42.21 48.703 ;
     RECT  4.212 48.389 7.002 48.731 ;
     RECT  43.2 48.361 76.374 48.811 ;
     RECT  77.436 48.271 78.297 48.811 ;
     RECT  43.2 48.811 78.297 48.893 ;
     RECT  37.515 48.703 42.246 48.901 ;
     RECT  34.776 48.703 35.097 48.929 ;
     RECT  76.932 48.893 78.297 48.989 ;
     RECT  37.515 48.901 42.282 49.001 ;
     RECT  4.5 48.731 7.002 49.109 ;
     RECT  77.544 48.989 78.297 49.181 ;
     RECT  38.556 49.001 42.282 49.243 ;
     RECT  43.2 48.893 75.87 49.243 ;
     RECT  8.82 48.569 8.838 49.379 ;
     RECT  38.556 49.243 75.87 49.747 ;
     RECT  37.515 49.001 37.797 49.783 ;
     RECT  38.556 49.747 76.41 49.783 ;
     RECT  34.815 48.929 35.097 49.819 ;
     RECT  93.492 47.849 94.497 49.855 ;
     RECT  13.215 47.191 13.698 49.883 ;
     RECT  82.692 47.405 83.697 49.883 ;
     RECT  5.115 49.109 7.002 50.009 ;
     RECT  5.115 50.009 6.354 50.189 ;
     RECT  37.515 49.783 76.41 50.189 ;
     RECT  6.336 50.189 6.354 50.351 ;
     RECT  34.776 49.819 35.097 50.423 ;
     RECT  88.815 44.609 89.19 50.791 ;
     RECT  38.808 50.189 76.41 50.813 ;
     RECT  76.392 50.813 76.41 50.909 ;
     RECT  37.515 50.189 37.797 50.935 ;
     RECT  38.808 50.813 75.192 50.935 ;
     RECT  77.616 49.181 78.297 51.163 ;
     RECT  77.544 51.163 78.297 51.259 ;
     RECT  91.116 48.163 92.322 51.871 ;
     RECT  93.168 49.855 94.497 51.871 ;
     RECT  91.116 51.871 94.497 52.051 ;
     RECT  91.116 52.051 94.662 52.249 ;
     RECT  81.756 47.885 81.774 52.313 ;
     RECT  91.116 52.249 94.698 52.321 ;
     RECT  91.116 52.321 94.77 52.439 ;
     RECT  76.392 51.736 76.41 52.603 ;
     RECT  77.4 51.259 78.297 52.603 ;
     RECT  37.515 50.935 75.192 52.789 ;
     RECT  86.115 47.219 86.397 52.789 ;
     RECT  96.912 52.789 96.93 52.843 ;
     RECT  91.116 52.439 94.662 52.861 ;
     RECT  76.392 52.603 78.297 53.015 ;
     RECT  96.912 52.843 97.506 53.015 ;
     RECT  37.515 52.789 75.51 53.021 ;
     RECT  96.912 53.015 96.93 53.021 ;
     RECT  38.772 53.021 75.51 53.179 ;
     RECT  88.815 50.791 89.262 53.227 ;
     RECT  38.772 53.179 75.834 53.249 ;
     RECT  76.968 53.015 78.297 53.249 ;
     RECT  90.648 52.861 94.662 53.275 ;
     RECT  95.76 52.249 95.778 53.275 ;
     RECT  88.815 53.227 89.586 53.329 ;
     RECT  90.648 53.275 95.778 53.419 ;
     RECT  88.815 53.329 89.802 53.429 ;
     RECT  88.815 53.429 89.73 53.519 ;
     RECT  98.172 53.563 98.19 53.599 ;
     RECT  39.312 53.249 75.834 53.627 ;
     RECT  98.172 53.599 98.262 53.627 ;
     RECT  98.244 53.627 98.262 53.645 ;
     RECT  90.648 53.419 96.39 53.741 ;
     RECT  90.648 53.741 96.354 53.897 ;
     RECT  86.115 52.789 86.67 53.941 ;
     RECT  39.312 53.627 39.33 54.031 ;
     RECT  39.132 54.031 39.33 54.059 ;
     RECT  88.815 53.519 89.586 54.059 ;
     RECT  40.215 53.627 75.834 54.067 ;
     RECT  39.132 54.059 39.15 54.125 ;
     RECT  86.115 53.941 86.706 54.131 ;
     RECT  91.116 53.897 96.354 54.239 ;
     RECT  97.488 53.995 97.506 54.427 ;
     RECT  97.488 54.427 97.542 54.509 ;
     RECT  91.116 54.239 95.85 55.021 ;
     RECT  97.488 54.509 97.506 55.037 ;
     RECT  90.648 55.021 95.85 55.111 ;
     RECT  90.648 55.111 95.922 55.243 ;
     RECT  90.504 55.243 95.922 55.291 ;
     RECT  90.324 55.291 95.922 55.381 ;
     RECT  40.215 54.067 76.122 55.489 ;
     RECT  40.215 55.489 76.158 55.525 ;
     RECT  77.22 53.249 78.297 55.525 ;
     RECT  88.815 54.059 89.19 55.525 ;
     RECT  90.18 55.381 95.922 55.525 ;
     RECT  88.815 55.525 95.922 55.565 ;
     RECT  90.324 55.565 95.922 55.805 ;
     RECT  86.115 54.131 86.397 56.029 ;
     RECT  90.324 55.805 95.778 56.255 ;
     RECT  86.115 56.029 86.67 56.291 ;
     RECT  97.488 56.155 97.506 56.291 ;
     RECT  88.815 55.565 89.19 56.335 ;
     RECT  88.815 56.335 89.262 56.371 ;
     RECT  88.815 56.371 89.406 56.429 ;
     RECT  90.324 56.255 95.742 56.911 ;
     RECT  90.18 56.911 95.742 56.957 ;
     RECT  90.9 56.957 95.742 57.407 ;
     RECT  93.528 57.407 95.742 57.595 ;
     RECT  93.528 57.595 95.778 57.643 ;
     RECT  93.528 57.643 95.85 57.691 ;
     RECT  40.215 55.525 78.297 58.415 ;
     RECT  93.528 57.691 95.922 58.621 ;
     RECT  93.492 58.621 95.922 58.649 ;
     RECT  93.492 58.649 95.778 58.691 ;
     RECT  93.492 58.691 95.67 58.721 ;
     RECT  93.492 58.721 94.698 58.991 ;
     RECT  90.9 57.407 92.538 60.421 ;
     RECT  93.492 58.991 94.626 60.449 ;
     RECT  40.215 58.415 77.238 60.504 ;
     RECT  40.215 60.504 43.146 60.575 ;
     RECT  90.648 60.421 92.538 60.611 ;
     RECT  70.704 60.504 70.794 60.647 ;
     RECT  74.736 60.504 77.238 60.647 ;
     RECT  90.9 60.611 92.538 60.647 ;
     RECT  70.704 60.647 70.722 60.881 ;
     RECT  74.808 60.647 77.238 60.881 ;
     RECT  75.204 60.881 77.238 61.051 ;
     RECT  78.015 58.415 78.297 61.051 ;
     RECT  86.115 56.291 86.397 61.051 ;
     RECT  95.436 58.721 95.67 61.079 ;
     RECT  75.204 61.051 78.678 61.088 ;
     RECT  90.9 60.647 91.854 61.151 ;
     RECT  78.015 61.088 78.678 61.181 ;
     RECT  86.115 61.051 86.67 61.181 ;
     RECT  42.444 60.575 43.146 61.187 ;
     RECT  91.515 61.151 91.854 61.187 ;
     RECT  75.204 61.088 77.238 61.223 ;
     RECT  75.204 61.223 76.23 61.259 ;
     RECT  78.015 61.181 78.354 61.349 ;
     RECT  75.204 61.259 76.158 61.421 ;
     RECT  77.22 61.223 77.238 61.457 ;
     RECT  75.204 61.421 76.086 61.655 ;
     RECT  42.732 61.187 43.146 62.573 ;
     RECT  50.436 62.545 50.454 62.581 ;
     RECT  75.204 61.655 75.834 62.609 ;
     RECT  47.916 62.581 47.934 62.623 ;
     RECT  50.436 62.581 50.526 62.623 ;
     RECT  95.652 61.079 95.67 62.699 ;
     RECT  75.204 62.609 75.597 62.735 ;
     RECT  47.916 62.623 48.405 62.879 ;
     RECT  50.436 62.623 51.105 62.879 ;
     RECT  42.915 62.573 43.146 62.893 ;
     RECT  45.615 62.623 45.705 62.893 ;
     RECT  48.315 62.879 48.405 62.893 ;
     RECT  51.015 62.879 51.105 62.893 ;
     RECT  53.715 62.623 53.805 62.893 ;
     RECT  56.415 62.623 56.505 62.893 ;
     RECT  59.115 62.623 59.205 62.893 ;
     RECT  61.815 62.623 61.905 62.893 ;
     RECT  64.515 62.623 64.605 62.893 ;
     RECT  67.215 62.623 67.305 62.893 ;
     RECT  69.915 62.623 70.005 62.893 ;
     RECT  72.615 62.623 72.705 62.893 ;
     RECT  75.24 62.735 75.597 63.509 ;
     RECT  42.915 62.893 43.197 64.561 ;
     RECT  42.915 64.561 43.542 64.859 ;
     RECT  42.915 64.859 43.254 64.973 ;
     RECT  80.715 47.885 80.997 65.707 ;
     RECT  80.532 65.707 80.997 65.747 ;
     RECT  78.015 61.349 78.297 65.821 ;
     RECT  78.015 65.821 79.002 66.125 ;
     RECT  79.236 67.819 79.254 68.099 ;
     RECT  78.015 66.125 78.297 70.123 ;
     RECT  78.015 70.123 78.678 70.501 ;
     RECT  77.472 70.501 78.678 70.529 ;
     RECT  77.472 70.529 78.297 70.685 ;
     RECT  78.015 70.685 78.297 73.192 ;
     RECT  88.815 56.429 89.097 73.201 ;
     RECT  77.472 73.192 78.297 73.229 ;
     RECT  76.68 73.273 76.698 73.325 ;
     RECT  88.776 73.201 89.097 73.381 ;
     RECT  88.308 73.381 89.097 74.191 ;
     RECT  88.236 74.191 89.097 74.333 ;
     RECT  75.315 63.509 75.597 75.451 ;
     RECT  13.215 49.883 13.497 75.541 ;
     RECT  75.315 75.451 75.906 75.541 ;
     RECT  75.315 75.541 76.23 75.581 ;
     RECT  39.348 75.259 39.366 75.659 ;
     RECT  13.215 75.541 13.806 75.725 ;
     RECT  39.168 75.775 39.186 75.821 ;
     RECT  93.492 60.449 94.497 77.995 ;
     RECT  84.492 77.947 84.798 78.089 ;
     RECT  93.348 77.995 94.497 78.089 ;
     RECT  84.78 78.089 84.798 78.359 ;
     RECT  93.384 78.089 94.497 78.467 ;
     RECT  64.515 62.893 64.797 78.511 ;
     RECT  65.952 78.331 65.97 78.511 ;
     RECT  67.215 62.893 67.497 78.511 ;
     RECT  65.952 78.511 67.497 78.629 ;
     RECT  93.384 78.467 93.474 78.629 ;
     RECT  2.415 45.419 2.697 78.637 ;
     RECT  66.6 78.629 67.497 78.653 ;
     RECT  64.515 78.511 65.178 78.673 ;
     RECT  5.115 50.189 5.397 78.709 ;
     RECT  2.415 78.637 2.862 78.781 ;
     RECT  3.744 78.673 3.762 78.781 ;
     RECT  42.915 64.973 43.197 78.907 ;
     RECT  2.268 78.781 3.762 78.941 ;
     RECT  40.215 60.575 41.562 78.943 ;
     RECT  42.768 78.907 43.197 78.943 ;
     RECT  80.715 65.747 80.997 78.943 ;
     RECT  93.384 78.629 93.402 78.971 ;
     RECT  6.804 78.673 6.822 78.979 ;
     RECT  7.815 48.389 8.097 78.979 ;
     RECT  4.968 78.709 5.397 79.015 ;
     RECT  4.968 79.015 5.454 79.036 ;
     RECT  4.5 79.036 5.454 79.051 ;
     RECT  2.304 78.941 3.762 79.079 ;
     RECT  6.804 78.979 8.586 79.249 ;
     RECT  6.804 79.249 9.198 79.277 ;
     RECT  64.515 78.673 65.718 79.277 ;
     RECT  3.42 79.079 3.762 79.321 ;
     RECT  4.5 79.051 5.526 79.321 ;
     RECT  2.304 79.079 2.697 79.373 ;
     RECT  3.42 79.321 5.526 79.483 ;
     RECT  9.108 79.277 9.198 79.511 ;
     RECT  38.772 79.483 38.79 79.583 ;
     RECT  3.42 79.483 5.598 79.709 ;
     RECT  6.804 79.277 8.262 79.819 ;
     RECT  0.144 79.627 0.162 79.949 ;
     RECT  2.415 79.373 2.697 79.963 ;
     RECT  3.42 79.709 5.454 79.963 ;
     RECT  6.768 79.819 8.262 79.987 ;
     RECT  6.732 79.987 8.262 80.131 ;
     RECT  2.415 79.963 5.454 80.159 ;
     RECT  9.288 79.591 9.306 80.249 ;
     RECT  6.732 80.131 8.514 80.329 ;
     RECT  6.264 80.329 8.514 80.393 ;
     RECT  2.415 80.159 3.438 80.491 ;
     RECT  4.248 80.159 5.454 80.491 ;
     RECT  6.264 80.393 8.442 80.491 ;
     RECT  9.216 80.491 9.234 80.591 ;
     RECT  0.108 80.059 0.126 80.699 ;
     RECT  94.215 78.467 94.497 80.761 ;
     RECT  2.304 80.491 3.438 80.905 ;
     RECT  4.248 80.491 8.442 80.905 ;
     RECT  94.215 80.761 95.742 80.905 ;
     RECT  10.515 47.111 10.797 80.941 ;
     RECT  2.304 80.905 8.442 80.969 ;
     RECT  10.515 80.941 10.818 81.059 ;
     RECT  94.215 80.905 95.778 81.211 ;
     RECT  2.415 80.969 8.442 81.473 ;
     RECT  91.515 61.187 91.797 81.481 ;
     RECT  92.628 81.451 92.646 81.481 ;
     RECT  0.54 81.211 0.558 81.499 ;
     RECT  0.144 81.499 0.558 81.509 ;
     RECT  91.404 81.481 91.854 81.607 ;
     RECT  92.628 81.481 92.898 81.607 ;
     RECT  91.404 81.607 92.898 81.751 ;
     RECT  2.415 81.473 7.074 81.779 ;
     RECT  0.144 81.509 0.162 81.787 ;
     RECT  91.368 81.751 92.898 81.841 ;
     RECT  94.215 81.211 95.922 81.917 ;
     RECT  97.452 81.499 97.47 81.941 ;
     RECT  10.515 81.059 10.797 81.949 ;
     RECT  88.815 74.333 89.097 81.949 ;
     RECT  91.368 81.841 93.294 82.021 ;
     RECT  94.215 81.917 95.742 82.021 ;
     RECT  0.108 81.787 0.162 82.049 ;
     RECT  10.515 81.949 10.854 82.049 ;
     RECT  2.415 81.779 6.93 82.139 ;
     RECT  2.415 82.139 5.397 82.175 ;
     RECT  91.368 82.021 95.742 82.183 ;
     RECT  75.315 75.581 75.597 82.291 ;
     RECT  90 82.255 90.018 82.291 ;
     RECT  90.972 82.183 95.742 82.291 ;
     RECT  0.144 82.049 0.162 82.363 ;
     RECT  7.815 81.473 8.442 82.381 ;
     RECT  3.42 82.175 5.397 82.409 ;
     RECT  2.415 82.175 2.697 82.507 ;
     RECT  38.808 79.825 38.826 82.517 ;
     RECT  3.42 82.409 4.374 82.553 ;
     RECT  6.192 82.139 6.93 82.553 ;
     RECT  88.596 81.949 89.097 82.561 ;
     RECT  90 82.291 95.742 82.561 ;
     RECT  0.144 82.363 0.558 82.589 ;
     RECT  2.304 82.507 2.697 82.651 ;
     RECT  64.515 79.277 65.286 82.651 ;
     RECT  75.132 82.291 75.597 82.651 ;
     RECT  78.015 73.229 78.297 82.687 ;
     RECT  2.268 82.651 2.697 82.688 ;
     RECT  6.192 82.553 6.822 82.715 ;
     RECT  7.815 82.381 8.586 82.715 ;
     RECT  7.815 82.715 8.226 82.759 ;
     RECT  88.596 82.561 95.742 82.795 ;
     RECT  7.776 82.759 8.226 82.831 ;
     RECT  75.132 82.651 75.798 82.831 ;
     RECT  88.596 82.795 95.778 82.831 ;
     RECT  0.144 82.589 0.27 82.939 ;
     RECT  8.964 82.723 9.45 82.949 ;
     RECT  86.115 61.181 86.397 82.957 ;
     RECT  78.015 82.687 78.642 82.987 ;
     RECT  85.752 82.957 86.67 82.987 ;
     RECT  7.704 82.831 8.226 83.021 ;
     RECT  85.536 82.987 86.67 83.035 ;
     RECT  2.304 82.688 2.697 83.101 ;
     RECT  2.304 83.101 2.934 83.117 ;
     RECT  3.996 82.553 4.374 83.191 ;
     RECT  5.115 82.409 5.397 83.191 ;
     RECT  2.415 83.117 2.934 83.219 ;
     RECT  0.108 82.939 0.27 83.309 ;
     RECT  3.996 83.191 5.397 83.335 ;
     RECT  0.108 83.309 0.198 83.399 ;
     RECT  0.108 83.399 0.126 83.408 ;
     RECT  3.492 83.335 5.397 83.489 ;
     RECT  88.596 82.831 95.922 83.489 ;
     RECT  4.788 83.489 5.397 83.497 ;
     RECT  6.3 82.715 6.822 83.497 ;
     RECT  3.492 83.489 3.654 83.501 ;
     RECT  4.788 83.497 6.822 83.525 ;
     RECT  7.815 83.021 8.226 83.533 ;
     RECT  8.964 82.949 9.162 83.533 ;
     RECT  85.392 83.035 86.67 83.563 ;
     RECT  78.015 82.987 78.678 83.597 ;
     RECT  5.115 83.525 6.822 83.605 ;
     RECT  85.032 83.563 86.67 83.611 ;
     RECT  64.515 82.651 65.43 83.641 ;
     RECT  84.924 83.611 86.67 83.641 ;
     RECT  5.115 83.605 6.93 83.669 ;
     RECT  67.215 78.653 67.497 83.707 ;
     RECT  69.915 62.893 70.197 83.707 ;
     RECT  48.315 62.893 48.597 83.731 ;
     RECT  3.636 83.501 3.654 83.759 ;
     RECT  5.115 83.669 6.03 83.759 ;
     RECT  6.912 83.669 6.93 83.759 ;
     RECT  7.815 83.533 9.162 83.759 ;
     RECT  90.072 83.489 95.922 83.759 ;
     RECT  44.784 83.755 44.802 83.795 ;
     RECT  90.216 83.759 95.778 83.795 ;
     RECT  61.815 62.893 62.097 83.803 ;
     RECT  64.515 83.641 65.466 83.803 ;
     RECT  80.064 78.943 80.997 83.803 ;
     RECT  7.815 83.759 9.018 83.831 ;
     RECT  66.708 83.707 67.497 83.831 ;
     RECT  79.956 83.803 80.997 83.831 ;
     RECT  53.715 62.893 53.997 83.899 ;
     RECT  54.72 83.803 54.738 83.899 ;
     RECT  53.715 83.899 54.738 83.933 ;
     RECT  61.815 83.803 62.19 83.933 ;
     RECT  45.615 62.893 45.897 83.987 ;
     RECT  51.015 62.893 51.297 83.987 ;
     RECT  56.415 62.893 56.697 83.987 ;
     RECT  59.115 62.893 59.397 83.987 ;
     RECT  61.815 83.933 62.097 83.987 ;
     RECT  67.215 83.831 67.497 83.987 ;
     RECT  72.615 62.893 72.897 83.987 ;
     RECT  40.215 78.943 43.197 84.001 ;
     RECT  69.915 83.707 70.47 84.001 ;
     RECT  38.772 83.803 38.79 84.029 ;
     RECT  37.515 53.021 37.797 84.037 ;
     RECT  72.615 83.987 72.705 84.037 ;
     RECT  64.515 83.803 65.934 84.043 ;
     RECT  64.512 84.043 65.934 84.065 ;
     RECT  90.216 83.795 95.634 84.065 ;
     RECT  69.915 84.001 70.578 84.073 ;
     RECT  48.315 83.731 48.87 84.077 ;
     RECT  72 84.037 72.705 84.077 ;
     RECT  83.415 49.883 83.697 84.091 ;
     RECT  69.915 84.073 70.686 84.125 ;
     RECT  78.015 83.597 78.642 84.137 ;
     RECT  74.952 82.831 75.798 84.139 ;
     RECT  76.572 81.751 76.59 84.139 ;
     RECT  97.452 83.641 97.47 84.145 ;
     RECT  46.764 84.043 46.782 84.173 ;
     RECT  53.715 83.933 54.198 84.173 ;
     RECT  64.512 84.065 65.286 84.173 ;
     RECT  40.215 84.001 43.254 84.181 ;
     RECT  88.596 83.489 89.097 84.181 ;
     RECT  49.14 84.091 49.158 84.209 ;
     RECT  66.096 84.139 66.114 84.209 ;
     RECT  45.615 83.987 45.705 84.257 ;
     RECT  48.315 84.077 48.405 84.257 ;
     RECT  51.015 83.987 51.105 84.257 ;
     RECT  53.715 84.173 53.805 84.257 ;
     RECT  56.415 83.987 56.505 84.257 ;
     RECT  59.115 83.987 59.205 84.257 ;
     RECT  61.815 83.987 61.905 84.257 ;
     RECT  64.515 84.173 64.605 84.257 ;
     RECT  67.215 83.987 67.305 84.257 ;
     RECT  69.915 84.125 70.005 84.257 ;
     RECT  72.615 84.077 72.705 84.257 ;
     RECT  96.912 84.145 97.47 84.269 ;
     RECT  7.815 83.831 8.586 84.271 ;
     RECT  90.288 84.065 95.634 84.299 ;
     RECT  84.924 83.641 86.922 84.335 ;
     RECT  40.215 84.181 43.542 84.365 ;
     RECT  5.115 83.759 5.397 84.451 ;
     RECT  7.704 84.271 8.586 84.451 ;
     RECT  90.36 84.299 95.634 84.479 ;
     RECT  4.464 84.451 5.397 84.541 ;
     RECT  90.54 84.479 95.634 84.541 ;
     RECT  83.124 84.091 83.697 84.569 ;
     RECT  84.672 84.541 84.69 84.605 ;
     RECT  7.056 84.451 8.586 84.613 ;
     RECT  97.416 84.269 97.47 84.641 ;
     RECT  6.804 84.613 8.586 84.649 ;
     RECT  4.212 84.541 5.49 84.721 ;
     RECT  85.752 84.335 86.922 84.721 ;
     RECT  88.056 84.181 89.097 84.721 ;
     RECT  6.552 84.649 8.586 84.797 ;
     RECT  3.42 84.667 3.438 84.811 ;
     RECT  4.212 84.721 5.742 84.811 ;
     RECT  39.42 84.613 39.438 84.847 ;
     RECT  40.215 84.365 43.074 84.847 ;
     RECT  3.42 84.811 5.742 84.919 ;
     RECT  6.552 84.797 8.262 84.919 ;
     RECT  39.42 84.847 43.074 84.991 ;
     RECT  90.54 84.541 95.922 85.109 ;
     RECT  39.348 84.991 43.074 85.189 ;
     RECT  0.144 84.811 0.162 85.243 ;
     RECT  0.108 85.243 0.162 85.261 ;
     RECT  2.415 83.219 2.697 85.261 ;
     RECT  3.42 84.919 8.262 85.261 ;
     RECT  39.276 85.189 43.074 85.261 ;
     RECT  2.415 85.261 8.262 85.379 ;
     RECT  0.108 85.261 0.558 85.421 ;
     RECT  79.092 85.351 79.11 85.421 ;
     RECT  0.108 85.421 0.126 85.451 ;
     RECT  97.452 84.641 97.47 85.451 ;
     RECT  74.952 84.139 76.59 85.459 ;
     RECT  38.808 85.261 43.074 85.487 ;
     RECT  3.672 85.379 8.262 85.517 ;
     RECT  91.296 85.109 95.922 85.531 ;
     RECT  98.1 85.531 98.118 85.661 ;
     RECT  6.372 85.517 8.262 85.771 ;
     RECT  2.415 85.379 2.79 85.819 ;
     RECT  6.372 85.771 8.334 85.829 ;
     RECT  91.296 85.531 95.958 85.919 ;
     RECT  3.672 85.517 5.598 85.949 ;
     RECT  95.508 85.919 95.958 85.955 ;
     RECT  34.815 50.423 35.097 85.963 ;
     RECT  90.54 85.109 90.558 85.963 ;
     RECT  91.296 85.919 94.59 85.963 ;
     RECT  3.672 85.949 5.397 85.997 ;
     RECT  74.952 85.459 77.274 86.011 ;
     RECT  78.015 84.137 78.297 86.011 ;
     RECT  95.616 85.955 95.958 86.027 ;
     RECT  39.276 85.487 43.074 86.059 ;
     RECT  85.752 84.721 89.097 86.059 ;
     RECT  85.752 86.059 89.802 86.071 ;
     RECT  90.54 85.963 94.59 86.071 ;
     RECT  85.752 86.071 94.59 86.093 ;
     RECT  3.78 85.997 5.397 86.141 ;
     RECT  90.72 86.093 94.59 86.141 ;
     RECT  85.752 86.093 89.946 86.189 ;
     RECT  95.616 86.027 95.922 86.189 ;
     RECT  10.515 82.049 10.797 86.197 ;
     RECT  85.752 86.189 89.802 86.225 ;
     RECT  10.515 86.197 10.818 86.297 ;
     RECT  6.372 85.829 8.262 86.305 ;
     RECT  2.304 85.819 2.79 86.369 ;
     RECT  39.276 86.059 43.11 86.4 ;
     RECT  72.972 85.963 72.99 86.4 ;
     RECT  74.952 86.011 78.297 86.4 ;
     RECT  34.776 85.963 35.097 86.567 ;
     RECT  6.264 86.305 8.262 86.621 ;
     RECT  2.415 86.369 2.79 86.729 ;
     RECT  3.78 86.141 4.194 86.881 ;
     RECT  4.932 86.141 5.397 86.881 ;
     RECT  39.276 86.4 78.297 86.881 ;
     RECT  95.76 86.189 95.922 86.999 ;
     RECT  3.78 86.881 5.397 87.007 ;
     RECT  95.76 86.999 95.778 87.035 ;
     RECT  3.636 87.007 5.397 87.115 ;
     RECT  3.564 87.115 5.397 87.211 ;
     RECT  6.264 86.621 8.226 87.211 ;
     RECT  90.72 86.141 94.497 87.259 ;
     RECT  3.564 87.211 8.226 87.385 ;
     RECT  39.24 86.881 78.297 87.385 ;
     RECT  2.415 86.729 2.697 87.403 ;
     RECT  38.772 87.385 78.297 87.403 ;
     RECT  10.515 86.297 10.797 87.421 ;
     RECT  2.304 87.403 2.697 87.449 ;
     RECT  38.772 87.403 78.678 87.581 ;
     RECT  85.752 86.225 89.097 87.595 ;
     RECT  10.515 87.421 10.818 87.611 ;
     RECT  3.564 87.385 8.298 87.691 ;
     RECT  82.656 87.547 82.674 87.809 ;
     RECT  38.772 87.581 78.297 87.869 ;
     RECT  2.415 87.449 2.697 87.889 ;
     RECT  3.564 87.691 8.55 87.889 ;
     RECT  2.415 87.889 8.55 87.917 ;
     RECT  38.772 87.869 76.374 87.965 ;
     RECT  0.108 86.395 0.126 88.123 ;
     RECT  85.5 87.595 89.097 88.157 ;
     RECT  0.108 88.123 0.342 88.301 ;
     RECT  4.392 87.917 8.55 88.349 ;
     RECT  38.772 87.965 76.338 88.349 ;
     RECT  85.5 88.157 88.074 88.465 ;
     RECT  90.648 87.259 94.497 88.501 ;
     RECT  84.888 88.465 88.074 88.529 ;
     RECT  4.392 88.349 8.334 88.619 ;
     RECT  90.468 88.501 94.497 88.619 ;
     RECT  4.392 88.619 8.226 88.655 ;
     RECT  9.216 88.591 9.234 88.691 ;
     RECT  90.648 88.619 94.497 88.733 ;
     RECT  2.415 87.917 3.438 88.747 ;
     RECT  38.772 88.349 76.158 88.763 ;
     RECT  84.888 88.529 84.906 88.781 ;
     RECT  0.108 88.301 0.198 88.799 ;
     RECT  2.415 88.747 3.582 88.861 ;
     RECT  4.392 88.655 8.097 88.861 ;
     RECT  0.18 88.799 0.198 88.877 ;
     RECT  77.22 87.869 78.297 88.939 ;
     RECT  10.515 87.611 10.797 89.005 ;
     RECT  2.415 88.861 8.097 89.131 ;
     RECT  2.304 89.131 8.097 89.159 ;
     RECT  90.648 88.733 92.934 89.159 ;
     RECT  2.304 89.159 2.862 89.168 ;
     RECT  3.96 89.159 8.097 89.195 ;
     RECT  86.004 88.529 88.074 89.213 ;
     RECT  2.415 89.168 2.862 89.261 ;
     RECT  10.515 89.005 10.818 89.267 ;
     RECT  87.48 89.213 88.074 89.309 ;
     RECT  3.96 89.195 3.978 89.339 ;
     RECT  4.896 89.195 8.097 89.429 ;
     RECT  39.06 88.763 76.158 89.429 ;
     RECT  39.276 89.429 76.158 89.473 ;
     RECT  4.896 89.429 5.994 89.609 ;
     RECT  7.452 89.429 8.097 89.609 ;
     RECT  4.896 89.609 5.397 89.699 ;
     RECT  7.524 89.609 8.097 89.699 ;
     RECT  87.48 89.309 87.498 89.741 ;
     RECT  77.22 88.939 78.678 89.755 ;
     RECT  84.852 89.707 84.87 89.779 ;
     RECT  86.004 89.213 86.742 89.789 ;
     RECT  84.852 89.779 84.906 89.851 ;
     RECT  86.115 89.789 86.742 89.879 ;
     RECT  90.648 89.159 92.862 89.899 ;
     RECT  93.852 88.733 94.497 89.899 ;
     RECT  77.22 89.755 78.75 89.981 ;
     RECT  90.648 89.899 94.497 89.981 ;
     RECT  84.78 89.851 84.906 90.077 ;
     RECT  90.648 89.981 92.862 90.239 ;
     RECT  90.648 90.239 92.214 90.269 ;
     RECT  84.78 90.077 84.87 90.317 ;
     RECT  84.852 90.317 84.87 90.365 ;
     RECT  80.715 83.831 80.997 90.379 ;
     RECT  81.756 85.801 81.774 90.379 ;
     RECT  80.715 90.379 81.774 90.419 ;
     RECT  81.756 90.419 81.774 90.557 ;
     RECT  77.22 89.981 78.39 90.763 ;
     RECT  86.115 89.879 86.397 90.763 ;
     RECT  90.36 90.391 90.378 90.845 ;
     RECT  77.22 90.763 78.678 90.893 ;
     RECT  86.115 90.763 86.67 90.893 ;
     RECT  93.852 89.981 94.497 90.895 ;
     RECT  39.276 89.473 76.266 90.941 ;
     RECT  39.276 90.941 41.562 91.133 ;
     RECT  42.444 90.941 76.266 91.229 ;
     RECT  42.444 91.229 75.438 91.325 ;
     RECT  76.248 91.229 76.266 91.471 ;
     RECT  39.456 91.133 41.562 91.613 ;
     RECT  42.444 91.325 75.402 91.613 ;
     RECT  76.248 91.471 76.338 91.705 ;
     RECT  76.248 91.705 76.374 92.011 ;
     RECT  77.22 90.893 78.297 92.011 ;
     RECT  76.248 92.011 78.297 92.189 ;
     RECT  42.444 91.613 75.192 92.407 ;
     RECT  76.248 92.189 76.41 92.407 ;
     RECT  42.444 92.407 76.41 92.669 ;
     RECT  42.48 92.669 76.41 93.053 ;
     RECT  39.528 91.613 41.562 93.325 ;
     RECT  42.48 93.053 75.192 93.341 ;
     RECT  39.024 93.325 41.562 93.631 ;
     RECT  24.015 2.413 24.297 93.739 ;
     RECT  23.832 93.739 24.297 93.785 ;
     RECT  21.315 40.733 21.597 93.901 ;
     RECT  76.392 93.053 76.41 93.901 ;
     RECT  43.056 93.341 75.192 94.027 ;
     RECT  76.32 93.901 76.41 94.027 ;
     RECT  21.315 93.901 22.302 94.061 ;
     RECT  37.515 84.037 37.926 94.063 ;
     RECT  38.88 93.631 41.562 94.063 ;
     RECT  37.515 94.063 41.562 94.333 ;
     RECT  43.056 94.027 76.41 94.459 ;
     RECT  43.056 94.459 76.446 94.595 ;
     RECT  37.515 94.333 42.21 94.603 ;
     RECT  37.515 94.603 42.246 94.939 ;
     RECT  43.056 94.595 76.41 94.939 ;
     RECT  93.744 90.895 94.497 94.939 ;
     RECT  95.904 95.071 95.922 95.131 ;
     RECT  95.76 95.131 95.922 95.341 ;
     RECT  37.515 94.939 76.41 95.357 ;
     RECT  95.364 95.341 95.922 95.639 ;
     RECT  77.22 92.189 78.297 95.783 ;
     RECT  93.744 94.939 94.626 95.791 ;
     RECT  95.364 95.639 95.778 95.791 ;
     RECT  76.392 95.357 76.41 95.995 ;
     RECT  93.744 95.791 95.778 96.077 ;
     RECT  92.988 96.061 93.006 96.179 ;
     RECT  91.224 90.269 92.214 96.283 ;
     RECT  93.744 96.077 95.742 96.421 ;
     RECT  88.815 88.157 89.097 96.427 ;
     RECT  37.515 95.357 75.192 96.475 ;
     RECT  76.392 95.995 76.446 96.475 ;
     RECT  88.815 96.427 89.694 96.485 ;
     RECT  86.115 90.893 86.397 96.529 ;
     RECT  37.515 96.475 76.446 96.571 ;
     RECT  77.472 95.783 78.297 96.667 ;
     RECT  37.515 96.571 76.662 96.719 ;
     RECT  93.492 96.421 95.742 96.835 ;
     RECT  93.492 96.835 95.778 96.961 ;
     RECT  93.492 96.961 95.814 96.997 ;
     RECT  93.384 96.997 95.814 97.231 ;
     RECT  90.324 96.907 90.342 97.243 ;
     RECT  90.144 97.243 90.342 97.259 ;
     RECT  90.144 97.259 90.162 97.295 ;
     RECT  97.452 97.051 97.47 97.331 ;
     RECT  86.115 96.529 86.67 97.439 ;
     RECT  91.224 96.283 92.574 97.501 ;
     RECT  93.384 97.231 95.922 97.501 ;
     RECT  37.515 96.719 39.402 97.915 ;
     RECT  37.476 97.915 39.402 97.979 ;
     RECT  91.224 97.501 95.922 98.059 ;
     RECT  37.515 97.979 39.402 98.069 ;
     RECT  37.515 98.069 39.366 98.213 ;
     RECT  79.956 83.831 79.974 98.339 ;
     RECT  86.115 97.439 86.397 98.383 ;
     RECT  97.452 98.203 97.47 98.411 ;
     RECT  86.115 98.383 86.67 98.519 ;
     RECT  90.756 98.059 95.922 98.761 ;
     RECT  90.432 98.761 95.922 98.879 ;
     RECT  90.432 98.879 95.85 98.951 ;
     RECT  91.224 98.951 95.85 99.149 ;
     RECT  91.224 99.149 95.778 99.245 ;
     RECT  22.572 99.643 22.59 99.661 ;
     RECT  22.356 99.661 22.59 99.689 ;
     RECT  90.252 99.571 90.27 99.689 ;
     RECT  90.108 99.691 90.126 99.731 ;
     RECT  22.356 99.689 22.374 99.773 ;
     RECT  97.452 99.643 97.47 99.787 ;
     RECT  91.224 99.245 95.526 99.841 ;
     RECT  91.044 99.841 95.526 100.075 ;
     RECT  91.044 100.075 95.634 100.111 ;
     RECT  97.308 99.787 97.47 100.301 ;
     RECT  97.452 100.301 97.47 100.571 ;
     RECT  90.288 100.645 90.306 100.651 ;
     RECT  91.044 100.111 95.922 100.651 ;
     RECT  90.288 100.651 95.922 100.685 ;
     RECT  90.432 100.685 95.922 100.841 ;
     RECT  90.432 100.841 92.538 100.877 ;
     RECT  91.044 100.877 92.538 101.039 ;
     RECT  93.492 100.841 95.922 101.075 ;
     RECT  93.492 101.075 95.85 101.309 ;
     RECT  93.492 101.309 95.814 101.345 ;
     RECT  95.724 101.345 95.814 101.579 ;
     RECT  95.796 101.579 95.814 101.597 ;
     RECT  40.14 96.719 76.662 101.615 ;
     RECT  40.14 101.615 76.23 103.704 ;
     RECT  77.4 96.667 78.297 103.775 ;
     RECT  93.492 101.345 94.914 103.805 ;
     RECT  91.044 101.039 92.322 103.883 ;
     RECT  75.24 103.704 76.23 104.153 ;
     RECT  93.492 103.805 94.497 104.423 ;
     RECT  40.14 103.704 43.146 104.459 ;
     RECT  40.14 104.459 41.922 104.549 ;
     RECT  91.044 103.883 92.25 104.549 ;
     RECT  75.24 104.153 76.194 104.621 ;
     RECT  40.215 104.549 41.922 104.927 ;
     RECT  91.515 104.549 92.25 104.927 ;
     RECT  91.515 104.927 92.178 105.161 ;
     RECT  49.104 105.133 49.122 105.169 ;
     RECT  75.24 104.621 76.122 105.197 ;
     RECT  42.696 104.459 43.146 105.439 ;
     RECT  49.104 105.169 49.41 105.637 ;
     RECT  42.696 105.439 43.182 105.665 ;
     RECT  88.815 96.485 89.097 105.739 ;
     RECT  42.732 105.665 43.182 105.809 ;
     RECT  48.132 105.673 48.15 105.823 ;
     RECT  49.104 105.637 49.878 105.823 ;
     RECT  65.16 105.451 65.178 105.823 ;
     RECT  88.74 105.739 89.097 105.871 ;
     RECT  48.132 105.823 49.878 105.899 ;
     RECT  88.416 105.871 89.097 105.917 ;
     RECT  46.8 105.709 46.818 105.971 ;
     RECT  37.515 98.213 38.97 106.043 ;
     RECT  79.488 98.383 79.794 106.043 ;
     RECT  64.515 105.823 65.178 106.051 ;
     RECT  42.915 105.809 43.182 106.093 ;
     RECT  45.615 105.823 45.705 106.093 ;
     RECT  51.015 105.823 51.105 106.093 ;
     RECT  53.715 105.823 53.805 106.093 ;
     RECT  56.415 105.823 56.505 106.093 ;
     RECT  59.115 105.823 59.205 106.093 ;
     RECT  61.815 105.823 61.905 106.093 ;
     RECT  67.215 105.823 67.305 106.093 ;
     RECT  69.915 105.823 70.005 106.093 ;
     RECT  72.615 105.823 72.705 106.093 ;
     RECT  75.24 105.197 75.474 106.093 ;
     RECT  88.74 105.917 89.097 106.169 ;
     RECT  64.515 106.051 65.466 106.205 ;
     RECT  67.215 106.093 67.497 106.312 ;
     RECT  66.708 106.312 67.497 106.349 ;
     RECT  75.24 106.093 75.597 107.015 ;
     RECT  42.915 106.093 43.197 107.275 ;
     RECT  42.915 107.275 43.254 107.671 ;
     RECT  64.515 106.205 64.797 107.752 ;
     RECT  64.515 107.752 65.106 107.941 ;
     RECT  64.515 107.941 65.43 108.317 ;
     RECT  42.915 107.671 43.542 108.509 ;
     RECT  42.915 108.509 43.398 108.557 ;
     RECT  86.115 98.519 86.397 111.403 ;
     RECT  86.115 111.403 86.67 111.581 ;
     RECT  83.415 84.569 83.697 111.643 ;
     RECT  86.115 111.581 86.598 111.677 ;
     RECT  36.324 111.685 36.342 111.919 ;
     RECT  34.815 86.567 35.097 111.955 ;
     RECT  36.324 111.919 36.378 111.955 ;
     RECT  34.815 111.955 36.378 111.991 ;
     RECT  37.515 106.043 38.43 111.991 ;
     RECT  83.34 111.643 83.697 112.019 ;
     RECT  34.815 111.991 38.43 112.793 ;
     RECT  37.512 112.793 38.43 112.927 ;
     RECT  37.512 112.927 38.97 113.269 ;
     RECT  37.512 113.269 39.114 113.459 ;
     RECT  37.512 113.459 38.97 113.531 ;
     RECT  37.512 113.531 38.934 113.539 ;
     RECT  34.815 112.793 36.594 113.611 ;
     RECT  37.476 113.539 38.934 113.611 ;
     RECT  83.415 112.019 83.697 113.701 ;
     RECT  34.815 113.611 38.934 113.729 ;
     RECT  79.488 106.043 79.506 113.729 ;
     RECT  34.815 113.729 38.826 113.765 ;
     RECT  40.215 104.927 41.562 113.995 ;
     RECT  83.232 113.701 83.697 114.511 ;
     RECT  85.212 114.475 85.23 114.523 ;
     RECT  40.215 113.995 41.778 114.539 ;
     RECT  84.636 114.523 85.23 114.539 ;
     RECT  34.815 113.765 38.25 114.547 ;
     RECT  84.636 114.539 84.654 114.809 ;
     RECT  83.232 114.511 83.754 114.853 ;
     RECT  83.232 114.853 84.33 114.881 ;
     RECT  86.115 111.677 86.397 115.051 ;
     RECT  83.415 114.881 84.33 115.133 ;
     RECT  29.415 40.733 29.697 115.321 ;
     RECT  27.72 115.147 27.738 115.339 ;
     RECT  27.72 115.339 27.81 115.349 ;
     RECT  29.268 115.321 29.697 115.373 ;
     RECT  34.815 114.547 38.286 115.627 ;
     RECT  27.792 115.349 27.81 115.661 ;
     RECT  34.815 115.627 39.15 115.771 ;
     RECT  34.815 115.771 39.294 116.239 ;
     RECT  34.815 116.239 39.402 117.625 ;
     RECT  40.215 114.539 41.562 117.625 ;
     RECT  42.915 108.557 43.197 118.561 ;
     RECT  42.915 118.561 43.254 119.713 ;
     RECT  42.804 119.713 43.254 120.091 ;
     RECT  34.815 117.625 41.562 120.487 ;
     RECT  34.815 120.487 41.742 120.571 ;
     RECT  42.768 120.091 43.254 120.571 ;
     RECT  34.815 120.571 43.254 120.749 ;
     RECT  5.115 89.699 5.397 120.991 ;
     RECT  34.815 120.749 42.174 121.099 ;
     RECT  4.752 120.991 5.397 121.171 ;
     RECT  75.315 107.015 75.597 121.171 ;
     RECT  2.415 89.261 2.697 121.261 ;
     RECT  3.996 121.171 5.397 121.261 ;
     RECT  6.84 121.171 6.858 121.261 ;
     RECT  34.776 121.099 42.174 121.397 ;
     RECT  3.996 121.261 5.49 121.441 ;
     RECT  74.376 121.063 74.394 121.441 ;
     RECT  75.24 121.171 75.597 121.441 ;
     RECT  2.415 121.261 2.934 121.531 ;
     RECT  34.815 121.397 42.174 121.531 ;
     RECT  42.915 120.749 43.254 121.531 ;
     RECT  3.96 121.441 5.49 121.639 ;
     RECT  78.015 103.775 78.297 121.675 ;
     RECT  7.815 89.699 8.097 121.801 ;
     RECT  3.96 121.639 5.598 121.829 ;
     RECT  2.304 121.531 2.934 121.945 ;
     RECT  74.376 121.441 75.597 121.945 ;
     RECT  2.304 121.945 3.438 122.009 ;
     RECT  0.108 121.243 0.126 122.107 ;
     RECT  74.16 121.945 75.597 122.107 ;
     RECT  0.108 122.107 0.198 122.143 ;
     RECT  4.212 121.829 5.598 122.179 ;
     RECT  6.372 121.261 6.858 122.179 ;
     RECT  7.815 121.801 8.37 122.179 ;
     RECT  0.108 122.143 0.27 122.189 ;
     RECT  77.292 121.675 78.297 122.189 ;
     RECT  73.908 122.107 75.597 122.251 ;
     RECT  0.108 122.189 0.198 122.279 ;
     RECT  2.34 122.009 3.438 122.279 ;
     RECT  0.108 122.279 0.162 122.288 ;
     RECT  73.908 122.251 75.726 122.587 ;
     RECT  2.415 122.279 3.438 122.611 ;
     RECT  4.212 122.179 8.37 122.611 ;
     RECT  34.815 121.531 43.254 122.639 ;
     RECT  73.656 122.587 75.726 122.639 ;
     RECT  2.415 122.611 8.37 122.647 ;
     RECT  0.144 122.288 0.162 122.669 ;
     RECT  2.415 122.647 8.586 122.717 ;
     RECT  45.615 106.093 45.897 122.791 ;
     RECT  73.764 122.639 75.726 122.791 ;
     RECT  2.415 122.717 5.778 122.813 ;
     RECT  45.615 122.791 46.854 122.861 ;
     RECT  34.815 122.639 43.197 122.881 ;
     RECT  2.415 122.813 4.23 122.909 ;
     RECT  9.36 122.449 9.378 122.909 ;
     RECT  73.764 122.791 75.942 122.945 ;
     RECT  46.836 122.861 46.854 122.957 ;
     RECT  34.776 122.881 43.197 123.089 ;
     RECT  2.415 122.909 3.222 123.115 ;
     RECT  2.304 123.115 3.222 123.179 ;
     RECT  4.14 122.909 4.158 123.251 ;
     RECT  74.16 122.945 75.942 123.331 ;
     RECT  5.004 122.813 5.778 123.529 ;
     RECT  6.696 122.717 8.586 123.529 ;
     RECT  2.415 123.179 3.222 123.691 ;
     RECT  5.004 123.529 8.586 123.691 ;
     RECT  74.16 123.331 76.338 123.691 ;
     RECT  2.415 123.691 3.294 123.871 ;
     RECT  30.852 123.799 30.87 123.899 ;
     RECT  4.968 123.691 8.586 124.069 ;
     RECT  72.615 106.093 72.897 124.075 ;
     RECT  74.016 123.691 76.338 124.075 ;
     RECT  4.968 124.069 9.126 124.105 ;
     RECT  4.536 124.105 9.126 124.133 ;
     RECT  0.144 124.027 0.162 124.157 ;
     RECT  9.108 124.133 9.126 124.169 ;
     RECT  2.415 123.871 3.474 124.259 ;
     RECT  4.536 124.133 8.298 124.259 ;
     RECT  4.536 124.259 5.397 124.267 ;
     RECT  4.104 124.267 5.397 124.529 ;
     RECT  6.264 124.259 8.298 124.529 ;
     RECT  0.108 124.411 0.126 124.589 ;
     RECT  72.615 124.075 76.338 124.681 ;
     RECT  6.408 124.529 8.298 124.709 ;
     RECT  56.415 106.093 56.697 124.771 ;
     RECT  56.415 124.771 56.718 124.829 ;
     RECT  55.152 124.795 55.278 124.843 ;
     RECT  55.08 124.843 55.278 125.069 ;
     RECT  2.415 124.259 3.33 125.213 ;
     RECT  72.615 124.681 76.59 125.213 ;
     RECT  6.408 124.709 6.822 125.249 ;
     RECT  33.12 125.185 33.138 125.339 ;
     RECT  4.392 124.529 5.397 125.717 ;
     RECT  72.615 125.213 76.482 125.761 ;
     RECT  7.815 124.709 8.298 125.789 ;
     RECT  72.468 125.761 76.482 125.851 ;
     RECT  6.408 125.249 6.426 126.023 ;
     RECT  72.288 125.851 76.482 126.029 ;
     RECT  72.396 126.029 76.482 126.031 ;
     RECT  55.188 126.265 55.206 126.301 ;
     RECT  78.015 122.189 78.297 126.499 ;
     RECT  55.152 126.301 55.206 126.523 ;
     RECT  56.415 124.829 56.697 126.523 ;
     RECT  69.915 106.093 70.197 126.571 ;
     RECT  72.396 126.031 76.626 126.661 ;
     RECT  34.815 123.089 43.197 126.763 ;
     RECT  72.396 126.661 76.698 126.805 ;
     RECT  69.915 126.571 70.722 126.869 ;
     RECT  71.964 126.805 76.698 126.995 ;
     RECT  72.615 126.995 76.698 127.075 ;
     RECT  77.508 126.499 78.297 127.075 ;
     RECT  46.62 127.075 46.638 127.099 ;
     RECT  55.152 126.523 56.697 127.099 ;
     RECT  83.415 115.133 83.862 127.103 ;
     RECT  55.116 127.099 56.697 127.133 ;
     RECT  45.615 122.861 45.897 127.187 ;
     RECT  48.315 105.899 48.597 127.187 ;
     RECT  51.015 106.093 51.297 127.187 ;
     RECT  53.715 106.093 53.997 127.187 ;
     RECT  56.415 127.133 56.697 127.187 ;
     RECT  59.115 106.093 59.397 127.187 ;
     RECT  61.815 106.093 62.097 127.187 ;
     RECT  64.515 108.317 64.797 127.187 ;
     RECT  67.215 106.349 67.497 127.187 ;
     RECT  69.915 126.869 70.197 127.187 ;
     RECT  34.815 126.763 43.866 127.229 ;
     RECT  55.116 127.133 55.422 127.229 ;
     RECT  72.615 127.075 78.297 127.265 ;
     RECT  34.815 127.229 43.794 127.277 ;
     RECT  46.62 127.099 46.818 127.277 ;
     RECT  55.404 127.229 55.422 127.277 ;
     RECT  46.62 127.277 46.71 127.373 ;
     RECT  73.584 127.265 78.297 127.373 ;
     RECT  46.62 127.373 46.638 127.379 ;
     RECT  45.615 127.187 45.705 127.457 ;
     RECT  48.315 127.187 48.405 127.457 ;
     RECT  51.015 127.187 51.105 127.457 ;
     RECT  53.715 127.187 53.805 127.457 ;
     RECT  56.415 127.187 56.505 127.457 ;
     RECT  59.115 127.187 59.205 127.457 ;
     RECT  61.815 127.187 61.905 127.457 ;
     RECT  64.515 127.187 64.605 127.457 ;
     RECT  67.215 127.187 67.305 127.457 ;
     RECT  69.915 127.187 70.005 127.457 ;
     RECT  72.615 127.265 72.705 127.457 ;
     RECT  74.16 127.373 76.482 127.499 ;
     RECT  74.412 127.499 76.482 127.571 ;
     RECT  74.7 127.571 76.482 128.461 ;
     RECT  77.508 127.373 78.297 128.461 ;
     RECT  74.7 128.461 78.297 128.776 ;
     RECT  34.815 127.277 43.074 129.155 ;
     RECT  41.76 129.155 43.074 129.451 ;
     RECT  74.664 128.776 78.297 129.541 ;
     RECT  41.76 129.451 43.11 129.6 ;
     RECT  74.664 129.541 78.39 129.6 ;
     RECT  34.815 129.155 41.022 130.235 ;
     RECT  41.76 129.6 78.39 130.351 ;
     RECT  36 130.235 41.022 130.843 ;
     RECT  41.76 130.351 78.426 130.843 ;
     RECT  36 130.843 78.426 131.009 ;
     RECT  36 131.009 36.018 131.045 ;
     RECT  36.972 131.009 78.426 131.069 ;
     RECT  37.44 131.069 78.426 131.279 ;
     RECT  37.515 131.279 78.426 131.431 ;
     RECT  37.515 131.431 78.714 131.453 ;
     RECT  77.4 131.453 78.714 131.621 ;
     RECT  37.515 131.453 76.338 131.819 ;
     RECT  41.832 131.819 76.338 131.837 ;
     RECT  41.94 131.837 76.338 131.933 ;
     RECT  37.515 131.819 40.986 132.089 ;
     RECT  41.976 131.933 76.338 132.331 ;
     RECT  41.976 132.331 76.41 132.509 ;
     RECT  77.4 131.621 78.462 132.601 ;
     RECT  41.976 132.509 76.338 132.605 ;
     RECT  42.084 132.605 76.338 132.797 ;
     RECT  77.4 132.601 78.894 132.899 ;
     RECT  42.12 132.797 76.338 132.989 ;
     RECT  42.336 132.989 76.338 133.085 ;
     RECT  42.66 133.085 76.338 133.277 ;
     RECT  43.2 133.277 76.338 133.435 ;
     RECT  77.4 132.899 78.822 133.435 ;
     RECT  43.2 133.435 78.822 133.439 ;
     RECT  79.56 133.321 79.578 133.583 ;
     RECT  79.812 134.011 79.83 134.131 ;
     RECT  80.715 90.419 80.997 134.131 ;
     RECT  43.2 133.439 78.678 134.249 ;
     RECT  79.812 134.131 80.997 134.249 ;
     RECT  77.436 134.249 78.678 134.671 ;
     RECT  77.436 134.671 78.714 134.861 ;
     RECT  43.2 134.249 76.446 134.933 ;
     RECT  77.436 134.861 78.318 135.635 ;
     RECT  77.436 135.635 78.297 135.779 ;
     RECT  43.2 134.933 76.41 136.021 ;
     RECT  77.58 135.779 78.297 136.061 ;
     RECT  83.415 127.103 83.697 136.267 ;
     RECT  85.716 115.051 86.397 136.381 ;
     RECT  84.528 136.411 84.546 136.451 ;
     RECT  82.98 136.267 83.697 136.493 ;
     RECT  85.716 136.381 86.634 136.493 ;
     RECT  37.515 132.089 40.95 136.561 ;
     RECT  42.768 136.021 76.41 136.651 ;
     RECT  77.616 136.061 78.297 136.651 ;
     RECT  85.716 136.493 86.598 136.679 ;
     RECT  85.716 136.679 86.397 136.715 ;
     RECT  77.616 136.651 78.678 136.781 ;
     RECT  83.052 136.493 83.697 136.781 ;
     RECT  85.788 136.715 86.397 136.823 ;
     RECT  77.616 136.781 78.297 137.117 ;
     RECT  42.192 136.651 76.41 137.405 ;
     RECT  37.515 136.561 41.022 137.641 ;
     RECT  42.192 137.405 42.21 137.641 ;
     RECT  76.392 137.405 76.41 137.659 ;
     RECT  76.392 137.659 76.446 137.795 ;
     RECT  77.652 137.117 78.297 137.839 ;
     RECT  37.515 137.641 42.21 137.981 ;
     RECT  95.724 138.139 95.742 138.145 ;
     RECT  77.616 137.839 78.297 138.307 ;
     RECT  95.616 138.145 95.742 138.379 ;
     RECT  77.58 138.307 78.297 138.427 ;
     RECT  95.616 138.379 95.922 138.479 ;
     RECT  95.616 138.479 95.778 138.541 ;
     RECT  94.215 104.423 94.497 138.721 ;
     RECT  95.364 138.541 95.778 138.721 ;
     RECT  91.515 105.161 91.797 138.763 ;
     RECT  94.215 138.721 95.778 138.811 ;
     RECT  90.792 138.763 91.797 138.839 ;
     RECT  76.392 137.795 76.41 138.875 ;
     RECT  94.176 138.811 95.778 138.883 ;
     RECT  92.772 129.235 92.79 138.955 ;
     RECT  93.6 138.883 95.778 138.955 ;
     RECT  91.476 138.839 91.797 138.991 ;
     RECT  92.772 138.955 95.778 138.991 ;
     RECT  43.056 137.405 75.192 139.003 ;
     RECT  37.515 137.981 42.174 139.189 ;
     RECT  43.02 139.003 75.192 139.189 ;
     RECT  77.436 138.427 78.297 139.195 ;
     RECT  88.815 106.169 89.097 139.351 ;
     RECT  89.928 139.261 89.946 139.351 ;
     RECT  88.815 139.351 89.946 139.423 ;
     RECT  91.476 138.991 95.778 139.435 ;
     RECT  77.4 139.195 78.297 139.459 ;
     RECT  88.815 139.423 90.306 139.661 ;
     RECT  77.22 139.459 78.297 139.675 ;
     RECT  86.115 136.823 86.397 139.801 ;
     RECT  90.252 139.661 90.306 139.801 ;
     RECT  76.968 139.675 78.297 139.867 ;
     RECT  86.115 139.801 86.67 139.891 ;
     RECT  90.252 139.801 90.702 139.919 ;
     RECT  37.515 139.189 75.192 139.963 ;
     RECT  86.115 139.891 86.706 139.991 ;
     RECT  90.648 139.919 90.702 140 ;
     RECT  86.115 139.991 86.67 140.099 ;
     RECT  90.648 140 90.666 140.099 ;
     RECT  88.815 139.661 89.226 140.141 ;
     RECT  91.476 139.435 95.814 140.189 ;
     RECT  93.816 140.189 95.814 140.203 ;
     RECT  37.515 139.963 75.582 140.467 ;
     RECT  93.816 140.203 95.922 140.729 ;
     RECT  91.476 140.189 93.042 140.881 ;
     RECT  37.515 140.467 75.654 140.971 ;
     RECT  91.26 140.881 93.042 140.971 ;
     RECT  90.648 140.971 93.042 141.007 ;
     RECT  93.816 140.729 95.742 141.007 ;
     RECT  37.515 140.971 75.726 141.179 ;
     RECT  90.648 141.007 95.742 141.179 ;
     RECT  88.815 140.141 89.097 141.241 ;
     RECT  91.044 141.179 95.742 141.269 ;
     RECT  91.188 141.269 95.742 141.293 ;
     RECT  88.815 141.241 89.262 141.341 ;
     RECT  42.192 141.179 75.726 141.547 ;
     RECT  76.68 139.867 78.297 141.547 ;
     RECT  97.452 140.251 97.47 141.611 ;
     RECT  91.368 141.293 95.742 141.691 ;
     RECT  91.368 141.691 95.778 141.88 ;
     RECT  42.192 141.547 78.297 141.881 ;
     RECT  91.368 141.88 95.886 141.917 ;
     RECT  91.368 141.917 95.85 142.051 ;
     RECT  90.036 141.241 90.054 142.195 ;
     RECT  42.444 141.881 78.297 142.349 ;
     RECT  90 142.195 90.054 142.349 ;
     RECT  90.936 142.051 95.85 143.131 ;
     RECT  90.936 143.131 95.922 143.339 ;
     RECT  95.76 143.339 95.922 143.735 ;
     RECT  95.904 143.735 95.922 143.741 ;
     RECT  42.444 142.349 77.238 144.661 ;
     RECT  42.192 144.661 77.238 146.904 ;
     RECT  90.936 143.339 94.59 147.119 ;
     RECT  70.704 146.904 70.722 147.197 ;
     RECT  42.192 146.904 43.218 147.245 ;
     RECT  74.664 146.904 77.238 147.317 ;
     RECT  74.664 147.317 75.726 147.353 ;
     RECT  76.644 147.317 77.238 147.479 ;
     RECT  74.664 147.353 75.654 147.515 ;
     RECT  93.816 147.119 94.59 147.659 ;
     RECT  37.515 141.179 41.454 147.749 ;
     RECT  90.936 147.119 92.97 147.749 ;
     RECT  42.48 147.245 43.218 147.821 ;
     RECT  37.515 147.749 40.95 147.857 ;
     RECT  90.936 147.749 92.646 147.857 ;
     RECT  37.515 147.857 40.662 147.893 ;
     RECT  77.22 147.479 77.238 147.893 ;
     RECT  91.515 147.857 92.646 147.893 ;
     RECT  90.036 142.349 90.054 148.469 ;
     RECT  43.056 147.821 43.218 148.901 ;
     RECT  48.456 148.441 48.474 148.981 ;
     RECT  50.004 148.945 50.022 148.981 ;
     RECT  74.664 147.515 75.33 148.981 ;
     RECT  74.664 148.981 75.474 149.009 ;
     RECT  43.056 148.901 43.197 149.023 ;
     RECT  48.456 148.981 48.582 149.023 ;
     RECT  50.868 148.873 50.886 149.023 ;
     RECT  49.932 148.981 50.022 149.099 ;
     RECT  50.868 149.023 51.105 149.099 ;
     RECT  74.736 149.009 75.474 149.099 ;
     RECT  93.816 147.659 94.497 149.099 ;
     RECT  75.06 149.099 75.474 149.135 ;
     RECT  54.684 149.071 54.702 149.279 ;
     RECT  45.615 149.023 45.705 149.293 ;
     RECT  48.315 149.023 48.582 149.293 ;
     RECT  51.015 149.099 51.105 149.293 ;
     RECT  53.715 149.023 53.805 149.293 ;
     RECT  56.415 149.023 56.505 149.293 ;
     RECT  59.115 149.023 59.205 149.293 ;
     RECT  61.815 149.023 61.905 149.293 ;
     RECT  64.515 149.023 64.605 149.293 ;
     RECT  67.215 149.023 67.305 149.293 ;
     RECT  69.915 149.023 70.005 149.293 ;
     RECT  72.615 149.023 72.705 149.293 ;
     RECT  75.276 149.135 75.474 149.293 ;
     RECT  75.276 149.293 75.597 149.909 ;
     RECT  37.515 147.893 40.497 166.109 ;
     RECT  37.515 166.109 39.438 167.341 ;
     RECT  40.215 166.109 40.497 167.341 ;
     RECT  37.515 167.341 40.497 167.531 ;
     RECT  37.515 167.531 39.258 167.729 ;
     RECT  2.415 125.213 2.697 168.227 ;
     RECT  5.115 125.717 5.397 168.227 ;
     RECT  7.815 125.789 8.097 168.227 ;
     RECT  10.515 89.267 10.797 168.227 ;
     RECT  13.215 75.725 13.497 168.227 ;
     RECT  15.915 2.413 16.197 168.227 ;
     RECT  18.615 2.413 18.897 168.227 ;
     RECT  21.315 94.061 21.597 168.227 ;
     RECT  24.015 93.785 24.297 168.227 ;
     RECT  26.715 2.413 26.997 168.227 ;
     RECT  29.415 115.373 29.697 168.227 ;
     RECT  32.115 2.413 32.397 168.227 ;
     RECT  34.815 130.235 35.097 168.227 ;
     RECT  40.215 167.531 40.497 168.227 ;
     RECT  42.915 149.023 43.197 168.227 ;
     RECT  45.615 149.293 45.897 168.227 ;
     RECT  48.315 149.293 48.597 168.227 ;
     RECT  51.015 149.293 51.297 168.227 ;
     RECT  53.715 149.293 53.997 168.227 ;
     RECT  56.415 149.293 56.697 168.227 ;
     RECT  59.115 149.293 59.397 168.227 ;
     RECT  61.815 149.293 62.097 168.227 ;
     RECT  64.515 149.293 64.797 168.227 ;
     RECT  67.215 149.293 67.497 168.227 ;
     RECT  69.915 149.293 70.197 168.227 ;
     RECT  72.615 149.293 72.897 168.227 ;
     RECT  75.315 149.909 75.597 168.227 ;
     RECT  78.015 142.349 78.297 168.227 ;
     RECT  80.715 134.249 80.997 168.227 ;
     RECT  83.415 136.781 83.697 168.227 ;
     RECT  86.115 140.099 86.397 168.227 ;
     RECT  88.815 141.341 89.097 168.227 ;
     RECT  91.515 147.893 91.797 168.227 ;
     RECT  94.215 149.099 94.497 168.227 ;
     RECT  2.415 168.227 2.505 168.497 ;
     RECT  5.115 168.227 5.205 168.497 ;
     RECT  7.815 168.227 7.905 168.497 ;
     RECT  10.515 168.227 10.605 168.497 ;
     RECT  13.215 168.227 13.305 168.497 ;
     RECT  15.915 168.227 16.005 168.497 ;
     RECT  18.615 168.227 18.705 168.497 ;
     RECT  21.315 168.227 21.405 168.497 ;
     RECT  24.015 168.227 24.105 168.497 ;
     RECT  26.715 168.227 26.805 168.497 ;
     RECT  29.415 168.227 29.505 168.497 ;
     RECT  32.115 168.227 32.205 168.497 ;
     RECT  34.815 168.227 34.905 168.497 ;
     RECT  37.515 167.729 39.006 168.497 ;
     RECT  40.215 168.227 40.305 168.497 ;
     RECT  42.915 168.227 43.005 168.497 ;
     RECT  45.615 168.227 45.705 168.497 ;
     RECT  48.315 168.227 48.405 168.497 ;
     RECT  51.015 168.227 51.105 168.497 ;
     RECT  53.715 168.227 53.805 168.497 ;
     RECT  56.415 168.227 56.505 168.497 ;
     RECT  59.115 168.227 59.205 168.497 ;
     RECT  61.815 168.227 61.905 168.497 ;
     RECT  64.515 168.227 64.605 168.497 ;
     RECT  67.215 168.227 67.305 168.497 ;
     RECT  69.915 168.227 70.005 168.497 ;
     RECT  72.615 168.227 72.705 168.497 ;
     RECT  75.315 168.227 75.405 168.497 ;
     RECT  78.015 168.227 78.105 168.497 ;
     RECT  80.715 168.227 80.805 168.497 ;
     RECT  83.415 168.227 83.505 168.497 ;
     RECT  86.115 168.227 86.205 168.497 ;
     RECT  88.815 168.227 88.905 168.497 ;
     RECT  91.515 168.227 91.605 168.497 ;
     RECT  94.215 168.227 94.305 168.497 ;
     RECT  38.124 168.497 39.006 170.395 ;
     RECT  37.836 170.395 39.006 170.603 ;
     RECT  37.836 170.603 37.908 170.609 ;
     RECT  37.926 170.603 38.016 170.609 ;
     RECT  38.034 170.603 38.124 170.609 ;
     RECT  38.142 170.603 38.232 170.609 ;
     RECT  38.25 170.603 38.34 170.609 ;
     RECT  38.358 170.603 38.448 170.609 ;
     RECT  38.466 170.603 38.556 170.609 ;
     RECT  38.574 170.603 38.664 170.609 ;
     RECT  38.682 170.603 38.772 170.609 ;
     RECT  38.79 170.603 38.88 170.609 ;
     RECT  38.898 170.603 38.988 170.609 ;
     RECT  37.926 170.609 38.016 170.621 ;
     RECT  38.034 170.609 38.124 170.621 ;
     RECT  38.142 170.609 38.232 170.621 ;
     RECT  38.25 170.609 38.34 170.621 ;
     RECT  38.358 170.609 38.448 170.621 ;
     RECT  38.466 170.609 38.556 170.621 ;
     RECT  38.574 170.609 38.664 170.621 ;
     RECT  38.682 170.609 38.772 170.621 ;
     RECT  38.79 170.609 38.88 170.621 ;
     RECT  38.898 170.609 38.988 170.621 ;
    LAYER M4 ;
     RECT  0.084 31.68 0.097 31.704 ;
     RECT  0.06 31.704 0.097 31.824 ;
     RECT  0.084 31.824 0.097 31.848 ;
     RECT  0.06 31.848 0.097 31.968 ;
     RECT  0.084 31.968 0.097 31.992 ;
     RECT  0.06 31.992 0.097 32.112 ;
     RECT  0.084 32.112 0.097 32.136 ;
     RECT  0.06 32.136 0.097 32.256 ;
     RECT  0.084 32.256 0.097 32.28 ;
     RECT  0.06 32.28 0.097 32.4 ;
     RECT  0.084 32.4 0.097 32.424 ;
     RECT  0.06 32.424 0.097 32.544 ;
     RECT  0.084 32.544 0.097 32.568 ;
     RECT  0.06 32.568 0.097 32.688 ;
     RECT  0.084 32.688 0.097 32.712 ;
     RECT  0.06 32.712 0.097 32.832 ;
     RECT  0.084 32.832 0.097 32.856 ;
     RECT  0.06 32.856 0.097 32.976 ;
     RECT  0.084 32.976 0.097 33 ;
     RECT  0.06 33 0.097 33.12 ;
     RECT  0.084 33.12 0.097 33.144 ;
     RECT  0.06 33.144 0.097 33.264 ;
     RECT  0.084 33.264 0.097 33.288 ;
     RECT  0.06 33.288 0.097 33.408 ;
     RECT  0.084 33.408 0.097 33.432 ;
     RECT  0.06 33.432 0.097 33.552 ;
     RECT  0.084 33.552 0.097 33.576 ;
     RECT  0.06 33.576 0.097 33.696 ;
     RECT  0.084 33.696 0.097 33.72 ;
     RECT  0.06 33.72 0.097 33.84 ;
     RECT  0.084 33.84 0.097 33.864 ;
     RECT  0.06 33.864 0.097 33.984 ;
     RECT  0.084 33.984 0.097 34.008 ;
     RECT  0.06 34.008 0.097 34.128 ;
     RECT  0.084 34.128 0.097 34.152 ;
     RECT  0.06 34.152 0.097 34.272 ;
     RECT  0.084 34.272 0.097 34.296 ;
     RECT  0.06 34.296 0.097 34.416 ;
     RECT  0.084 34.416 0.097 34.44 ;
     RECT  0.06 34.44 0.097 34.56 ;
     RECT  0.084 34.56 0.097 34.584 ;
     RECT  0.06 34.584 0.097 34.704 ;
     RECT  0.084 34.704 0.097 34.728 ;
     RECT  0.06 34.728 0.097 34.848 ;
     RECT  0.084 34.848 0.097 34.872 ;
     RECT  0.06 34.872 0.097 34.992 ;
     RECT  0.084 34.992 0.097 35.016 ;
     RECT  0.06 35.016 0.097 35.136 ;
     RECT  0.084 35.136 0.097 35.16 ;
     RECT  0.06 35.16 0.097 35.28 ;
     RECT  0.084 35.28 0.097 35.304 ;
     RECT  0.06 35.304 0.097 35.424 ;
     RECT  0.084 35.424 0.097 35.448 ;
     RECT  0.06 35.448 0.097 35.568 ;
     RECT  0.084 35.568 0.097 35.592 ;
     RECT  0.06 35.592 0.097 35.712 ;
     RECT  0.084 35.712 0.097 35.736 ;
     RECT  0.06 35.736 0.097 35.856 ;
     RECT  0.084 35.856 0.097 35.88 ;
     RECT  0.06 35.88 0.097 36 ;
     RECT  0.084 36 0.097 36.024 ;
     RECT  0.06 36.024 0.097 36.144 ;
     RECT  0.084 36.144 0.097 36.168 ;
     RECT  0.084 121.248 0.097 121.272 ;
     RECT  0.06 121.272 0.097 121.392 ;
     RECT  0.084 121.392 0.097 121.416 ;
     RECT  0.06 121.416 0.097 121.536 ;
     RECT  0.084 121.536 0.097 121.56 ;
     RECT  0.06 121.56 0.097 121.68 ;
     RECT  0.084 121.68 0.097 121.704 ;
     RECT  0.06 121.704 0.097 121.824 ;
     RECT  0.084 121.824 0.097 121.848 ;
     RECT  0.06 121.848 0.097 121.968 ;
     RECT  0.084 121.968 0.097 121.992 ;
     RECT  0.06 121.992 0.097 122.112 ;
     RECT  0.084 122.112 0.097 122.136 ;
     RECT  0.06 122.136 0.097 122.256 ;
     RECT  0.084 122.256 0.097 122.28 ;
     RECT  0.06 122.28 0.097 122.4 ;
     RECT  0.084 122.4 0.097 122.424 ;
     RECT  0.06 122.424 0.097 122.544 ;
     RECT  0.084 122.544 0.097 122.568 ;
     RECT  0.06 122.568 0.097 122.688 ;
     RECT  0.084 122.688 0.097 122.712 ;
     RECT  0.06 122.712 0.097 122.832 ;
     RECT  0.084 122.832 0.097 122.856 ;
     RECT  0.06 122.856 0.097 122.976 ;
     RECT  0.084 122.976 0.097 123 ;
     RECT  0.06 123 0.097 123.12 ;
     RECT  0.084 123.12 0.097 123.144 ;
     RECT  0.06 123.144 0.097 123.264 ;
     RECT  0.084 123.264 0.097 123.288 ;
     RECT  0.06 123.288 0.097 123.408 ;
     RECT  0.084 123.408 0.097 123.432 ;
     RECT  0.06 123.432 0.097 123.552 ;
     RECT  0.084 123.552 0.097 123.576 ;
     RECT  0.06 123.576 0.097 123.696 ;
     RECT  0.084 123.696 0.097 123.72 ;
     RECT  0.06 123.72 0.097 123.84 ;
     RECT  0.084 123.84 0.097 123.864 ;
     RECT  0.06 123.864 0.097 123.984 ;
     RECT  0.084 123.984 0.097 124.008 ;
     RECT  0.06 124.008 0.097 124.128 ;
     RECT  0.084 124.128 0.097 124.152 ;
     RECT  0.06 124.152 0.097 124.272 ;
     RECT  0.084 124.272 0.097 124.296 ;
     RECT  0.06 124.296 0.097 124.416 ;
     RECT  0.084 124.416 0.097 124.44 ;
     RECT  0.084 40.896 0.137 40.92 ;
     RECT  0.06 40.92 0.137 41.04 ;
     RECT  0.084 41.04 0.137 41.064 ;
     RECT  0.06 41.064 0.137 41.184 ;
     RECT  0.084 41.184 0.137 41.208 ;
     RECT  0.06 41.208 0.137 41.328 ;
     RECT  0.084 41.328 0.137 41.352 ;
     RECT  0.06 41.352 0.137 41.472 ;
     RECT  0.084 41.472 0.137 41.496 ;
     RECT  0.06 41.496 0.137 41.616 ;
     RECT  0.084 41.616 0.137 41.64 ;
     RECT  0.06 41.64 0.137 41.76 ;
     RECT  0.084 41.76 0.137 41.784 ;
     RECT  0.06 41.784 0.137 41.904 ;
     RECT  0.084 41.904 0.137 41.928 ;
     RECT  0.06 41.928 0.137 42.048 ;
     RECT  0.084 42.048 0.137 42.072 ;
     RECT  0.06 42.072 0.137 42.192 ;
     RECT  0.084 42.192 0.137 42.216 ;
     RECT  0.06 42.216 0.137 42.336 ;
     RECT  0.084 42.336 0.137 42.36 ;
     RECT  0.06 42.36 0.137 42.48 ;
     RECT  0.084 42.48 0.137 42.504 ;
     RECT  0.06 42.504 0.137 42.624 ;
     RECT  0.084 42.624 0.137 42.648 ;
     RECT  0.06 42.648 0.137 42.768 ;
     RECT  0.084 42.768 0.137 42.792 ;
     RECT  0.06 42.792 0.137 42.912 ;
     RECT  0.084 42.912 0.137 42.936 ;
     RECT  0.06 42.936 0.137 43.056 ;
     RECT  0.084 43.056 0.137 43.08 ;
     RECT  0.06 43.08 0.137 43.2 ;
     RECT  0.084 43.2 0.137 43.224 ;
     RECT  0.06 43.224 0.137 43.344 ;
     RECT  0.084 43.344 0.137 43.368 ;
     RECT  0.06 43.368 0.137 43.488 ;
     RECT  0.084 43.488 0.137 43.512 ;
     RECT  0.06 43.512 0.137 43.632 ;
     RECT  0.084 43.632 0.137 43.656 ;
     RECT  0.06 43.656 0.137 43.776 ;
     RECT  0.084 43.776 0.137 43.8 ;
     RECT  0.06 43.8 0.137 43.92 ;
     RECT  0.084 43.92 0.137 43.944 ;
     RECT  0.06 43.944 0.137 44.064 ;
     RECT  0.084 44.064 0.137 44.088 ;
     RECT  0.06 44.088 0.137 44.208 ;
     RECT  0.084 44.208 0.137 44.232 ;
     RECT  0.06 44.232 0.137 44.352 ;
     RECT  0.084 44.352 0.137 44.376 ;
     RECT  0.06 44.376 0.137 44.496 ;
     RECT  0.084 44.496 0.137 44.52 ;
     RECT  0.06 44.52 0.137 44.64 ;
     RECT  0.084 44.64 0.137 44.664 ;
     RECT  0.06 44.664 0.137 44.784 ;
     RECT  0.084 44.784 0.137 44.808 ;
     RECT  0.06 44.808 0.137 44.928 ;
     RECT  0.084 44.928 0.137 44.952 ;
     RECT  0.06 44.952 0.137 45.072 ;
     RECT  0.084 45.072 0.137 45.096 ;
     RECT  0.06 45.096 0.137 45.216 ;
     RECT  0.084 45.216 0.137 45.24 ;
     RECT  0.06 45.24 0.137 45.36 ;
     RECT  0.084 45.36 0.137 45.384 ;
     RECT  0.097 121.248 0.137 124.584 ;
     RECT  0.084 78.912 0.17 78.936 ;
     RECT  0.06 78.936 0.17 79.056 ;
     RECT  0.084 79.056 0.17 79.08 ;
     RECT  0.06 79.08 0.17 79.2 ;
     RECT  0.084 79.2 0.17 79.224 ;
     RECT  0.06 79.224 0.17 79.344 ;
     RECT  0.084 79.344 0.17 79.368 ;
     RECT  0.06 79.368 0.17 79.488 ;
     RECT  0.084 79.488 0.17 79.512 ;
     RECT  0.06 79.512 0.17 79.632 ;
     RECT  0.084 79.632 0.17 79.656 ;
     RECT  0.06 79.656 0.17 79.776 ;
     RECT  0.084 79.776 0.17 79.8 ;
     RECT  0.06 79.8 0.17 79.92 ;
     RECT  0.084 79.92 0.17 79.944 ;
     RECT  0.06 79.944 0.17 80.064 ;
     RECT  0.084 80.064 0.17 80.088 ;
     RECT  0.06 80.088 0.17 80.208 ;
     RECT  0.084 80.208 0.17 80.232 ;
     RECT  0.06 80.232 0.17 80.352 ;
     RECT  0.084 80.352 0.17 80.376 ;
     RECT  0.06 80.376 0.17 80.496 ;
     RECT  0.084 80.496 0.17 80.52 ;
     RECT  0.06 80.52 0.17 80.64 ;
     RECT  0.084 80.64 0.17 80.664 ;
     RECT  0.06 80.664 0.17 80.784 ;
     RECT  0.084 80.784 0.17 80.808 ;
     RECT  0.06 80.808 0.17 80.928 ;
     RECT  0.084 80.928 0.17 80.952 ;
     RECT  0.06 80.952 0.17 81.072 ;
     RECT  0.084 81.072 0.17 81.096 ;
     RECT  0.06 81.096 0.17 81.216 ;
     RECT  0.084 81.216 0.17 81.24 ;
     RECT  0.06 81.24 0.17 81.36 ;
     RECT  0.084 81.36 0.17 81.384 ;
     RECT  0.06 81.384 0.17 81.504 ;
     RECT  0.084 81.504 0.17 81.528 ;
     RECT  0.06 81.528 0.17 81.648 ;
     RECT  0.084 81.648 0.17 81.672 ;
     RECT  0.06 81.672 0.17 81.792 ;
     RECT  0.084 81.792 0.17 81.816 ;
     RECT  0.06 81.816 0.17 81.936 ;
     RECT  0.084 81.936 0.17 81.96 ;
     RECT  0.06 81.96 0.17 82.08 ;
     RECT  0.084 82.08 0.17 82.104 ;
     RECT  0.06 82.104 0.17 82.224 ;
     RECT  0.084 82.224 0.17 82.248 ;
     RECT  0.06 82.248 0.17 82.368 ;
     RECT  0.084 82.368 0.17 82.392 ;
     RECT  0.06 82.392 0.17 82.512 ;
     RECT  0.084 82.512 0.17 82.536 ;
     RECT  0.06 82.536 0.17 82.656 ;
     RECT  0.084 82.656 0.17 82.68 ;
     RECT  0.06 82.68 0.17 82.8 ;
     RECT  0.084 82.8 0.17 82.824 ;
     RECT  0.06 82.824 0.17 82.944 ;
     RECT  0.084 82.944 0.17 82.968 ;
     RECT  0.06 82.968 0.17 83.088 ;
     RECT  0.084 83.088 0.17 83.112 ;
     RECT  0.06 83.112 0.17 83.232 ;
     RECT  0.084 83.232 0.17 83.256 ;
     RECT  0.06 83.256 0.17 83.376 ;
     RECT  0.084 83.376 0.17 83.4 ;
     RECT  0.097 31.68 0.569 36.264 ;
     RECT  0.569 31.824 2.293 36.264 ;
     RECT  2.293 31.728 2.408 36.264 ;
     RECT  0.137 41.04 2.408 45.384 ;
     RECT  0.17 78.912 2.408 83.352 ;
     RECT  0.084 84.672 2.408 84.696 ;
     RECT  0.06 84.696 2.408 84.816 ;
     RECT  0.084 84.816 2.408 84.84 ;
     RECT  0.06 84.84 2.408 84.96 ;
     RECT  0.084 84.96 2.408 84.984 ;
     RECT  0.06 84.984 2.408 85.104 ;
     RECT  0.084 85.104 2.408 85.128 ;
     RECT  0.06 85.128 2.408 85.248 ;
     RECT  0.084 85.248 2.408 85.272 ;
     RECT  0.06 85.272 2.408 85.392 ;
     RECT  0.084 85.392 2.408 85.416 ;
     RECT  0.06 85.416 2.408 85.536 ;
     RECT  0.084 85.536 2.408 85.56 ;
     RECT  0.06 85.56 2.408 85.68 ;
     RECT  0.084 85.68 2.408 85.704 ;
     RECT  0.06 85.704 2.408 85.824 ;
     RECT  0.084 85.824 2.408 85.848 ;
     RECT  0.06 85.848 2.408 85.968 ;
     RECT  0.084 85.968 2.408 85.992 ;
     RECT  0.06 85.992 2.408 86.112 ;
     RECT  0.084 86.112 2.408 86.136 ;
     RECT  0.06 86.136 2.408 86.256 ;
     RECT  0.084 86.256 2.408 86.28 ;
     RECT  0.06 86.28 2.408 86.4 ;
     RECT  0.084 86.4 2.408 86.424 ;
     RECT  0.06 86.424 2.408 86.544 ;
     RECT  0.084 86.544 2.408 86.568 ;
     RECT  0.06 86.568 2.408 86.688 ;
     RECT  0.084 86.688 2.408 86.712 ;
     RECT  0.06 86.712 2.408 86.832 ;
     RECT  0.084 86.832 2.408 86.856 ;
     RECT  0.06 86.856 2.408 86.976 ;
     RECT  0.084 86.976 2.408 87 ;
     RECT  0.06 87 2.408 87.12 ;
     RECT  0.084 87.12 2.408 87.144 ;
     RECT  0.06 87.144 2.408 87.264 ;
     RECT  0.084 87.264 2.408 87.288 ;
     RECT  0.06 87.288 2.408 87.408 ;
     RECT  0.084 87.408 2.408 87.432 ;
     RECT  0.06 87.432 2.408 87.552 ;
     RECT  0.084 87.552 2.408 87.576 ;
     RECT  0.06 87.576 2.408 87.696 ;
     RECT  0.084 87.696 2.408 87.72 ;
     RECT  0.06 87.72 2.408 87.84 ;
     RECT  0.084 87.84 2.408 87.864 ;
     RECT  0.06 87.864 2.408 87.984 ;
     RECT  0.084 87.984 2.408 88.008 ;
     RECT  0.06 88.008 2.408 88.128 ;
     RECT  0.084 88.128 2.408 88.152 ;
     RECT  0.06 88.152 2.408 88.272 ;
     RECT  0.084 88.272 2.408 88.296 ;
     RECT  0.06 88.296 2.408 88.416 ;
     RECT  0.084 88.416 2.408 88.44 ;
     RECT  0.06 88.44 2.408 88.56 ;
     RECT  0.084 88.56 2.408 88.584 ;
     RECT  0.06 88.584 2.408 88.704 ;
     RECT  0.084 88.704 2.408 88.728 ;
     RECT  0.06 88.728 2.408 88.848 ;
     RECT  0.084 88.848 2.408 88.872 ;
     RECT  0.06 88.872 2.408 88.992 ;
     RECT  0.084 88.992 2.408 89.016 ;
     RECT  0.06 89.016 2.408 89.136 ;
     RECT  0.084 89.136 2.408 89.16 ;
     RECT  0.137 121.392 2.408 124.584 ;
     RECT  2.408 2.148 2.512 168.492 ;
     RECT  2.512 2.418 2.704 168.222 ;
     RECT  2.704 84.672 3.449 89.256 ;
     RECT  2.704 121.392 4.025 124.584 ;
     RECT  4.025 121.536 4.061 124.584 ;
     RECT  2.704 41.088 4.165 45.432 ;
     RECT  4.165 40.368 4.46 45.432 ;
     RECT  2.704 31.728 5.108 36.744 ;
     RECT  4.46 40.224 5.108 45.432 ;
     RECT  2.704 79.152 5.108 83.496 ;
     RECT  3.449 84.816 5.108 89.256 ;
     RECT  4.061 121.68 5.108 124.584 ;
     RECT  5.108 2.148 5.212 168.492 ;
     RECT  5.212 2.418 5.404 168.222 ;
     RECT  5.404 35.52 5.501 36.264 ;
     RECT  5.404 41.904 5.501 44.904 ;
     RECT  5.404 80.688 5.501 83.256 ;
     RECT  5.501 82.032 5.555 83.256 ;
     RECT  5.501 41.904 5.573 42.744 ;
     RECT  5.404 85.344 5.573 89.256 ;
     RECT  5.404 32.976 5.609 34.008 ;
     RECT  5.404 31.728 5.645 31.752 ;
     RECT  5.404 122.208 5.717 124.104 ;
     RECT  5.404 40.272 5.747 40.392 ;
     RECT  5.717 122.448 5.825 122.712 ;
     RECT  5.501 44.016 5.861 44.904 ;
     RECT  5.573 85.344 5.969 89.016 ;
     RECT  5.861 44.016 6.077 44.472 ;
     RECT  5.609 32.976 6.149 33 ;
     RECT  5.404 37.584 6.265 37.608 ;
     RECT  5.969 85.344 6.293 86.616 ;
     RECT  5.717 123.696 6.293 124.104 ;
     RECT  5.555 82.224 6.371 83.256 ;
     RECT  6.293 85.344 6.371 86.28 ;
     RECT  5.501 80.688 6.649 80.712 ;
     RECT  5.501 35.52 6.721 35.64 ;
     RECT  6.649 80.352 6.757 80.712 ;
     RECT  5.609 33.984 6.833 34.008 ;
     RECT  6.721 35.28 6.853 35.64 ;
     RECT  5.825 122.688 6.865 122.712 ;
     RECT  6.293 123.696 6.865 123.72 ;
     RECT  6.757 79.824 6.937 80.712 ;
     RECT  6.865 122.688 7.117 123.72 ;
     RECT  6.371 85.92 7.765 86.28 ;
     RECT  6.853 35.28 7.808 36.168 ;
     RECT  7.093 37.488 7.808 37.512 ;
     RECT  5.747 40.272 7.808 40.296 ;
     RECT  6.901 41.616 7.808 41.64 ;
     RECT  5.573 42.72 7.808 42.744 ;
     RECT  6.077 44.448 7.808 44.472 ;
     RECT  7.801 45.696 7.808 45.72 ;
     RECT  6.937 79.44 7.808 80.712 ;
     RECT  6.371 82.224 7.808 82.248 ;
     RECT  5.404 84.288 7.808 84.312 ;
     RECT  7.765 85.776 7.808 86.28 ;
     RECT  5.969 88.368 7.808 89.016 ;
     RECT  5.404 115.632 7.808 115.656 ;
     RECT  7.117 122.64 7.808 123.72 ;
     RECT  7.808 2.148 7.912 168.492 ;
     RECT  7.912 2.418 8.104 168.222 ;
     RECT  8.104 82.224 8.165 82.248 ;
     RECT  8.104 122.64 8.165 122.664 ;
     RECT  8.104 44.976 8.243 45.72 ;
     RECT  8.104 79.44 8.273 80.376 ;
     RECT  8.104 34.752 8.281 35.352 ;
     RECT  8.104 83.76 8.281 87.24 ;
     RECT  8.281 83.76 8.284 86.616 ;
     RECT  8.104 43.536 8.291 43.56 ;
     RECT  8.284 83.76 8.345 85.8 ;
     RECT  8.104 42.144 8.381 42.168 ;
     RECT  8.243 44.976 8.381 45 ;
     RECT  8.104 36.432 8.483 36.456 ;
     RECT  8.104 40.272 8.483 41.112 ;
     RECT  8.273 80.352 8.525 80.376 ;
     RECT  8.345 83.76 8.531 85.512 ;
     RECT  8.531 84.144 8.597 84.792 ;
     RECT  8.483 40.272 10.508 40.584 ;
     RECT  8.597 84.144 10.508 84.168 ;
     RECT  8.104 115.632 10.508 115.656 ;
     RECT  10.508 2.148 10.612 168.492 ;
     RECT  10.612 2.418 10.804 168.222 ;
     RECT  10.804 40.272 12.517 40.584 ;
     RECT  12.517 40.272 13.208 40.632 ;
     RECT  12.229 75.696 13.208 75.72 ;
     RECT  10.804 84.288 13.208 84.312 ;
     RECT  10.804 115.632 13.208 115.656 ;
     RECT  13.208 2.148 13.312 168.492 ;
     RECT  13.312 2.418 13.504 168.222 ;
     RECT  13.504 75.456 13.817 75.72 ;
     RECT  13.504 40.608 14.861 40.728 ;
     RECT  14.861 40.608 15.908 40.632 ;
     RECT  13.817 75.456 15.908 75.48 ;
     RECT  13.504 115.632 15.908 115.656 ;
     RECT  15.908 2.148 16.012 168.492 ;
     RECT  16.012 2.418 16.204 168.222 ;
     RECT  16.204 40.608 18.608 40.632 ;
     RECT  16.204 75.456 18.608 75.48 ;
     RECT  16.204 115.632 18.608 115.656 ;
     RECT  18.608 2.148 18.712 168.492 ;
     RECT  18.712 2.418 18.904 168.222 ;
     RECT  18.904 40.608 21.308 40.632 ;
     RECT  18.904 75.456 21.308 75.48 ;
     RECT  18.904 115.632 21.308 115.656 ;
     RECT  21.308 2.148 21.412 168.492 ;
     RECT  21.412 2.418 21.604 168.222 ;
     RECT  21.604 40.608 21.701 40.728 ;
     RECT  21.604 99.648 22.385 99.768 ;
     RECT  21.604 94.032 22.499 94.056 ;
     RECT  22.385 99.648 22.601 99.672 ;
     RECT  21.701 40.704 22.813 40.728 ;
     RECT  22.813 40.608 22.853 40.728 ;
     RECT  21.604 115.632 23.845 115.656 ;
     RECT  22.853 40.608 24.008 40.632 ;
     RECT  21.604 75.456 24.008 75.48 ;
     RECT  23.804 93.744 24.008 93.768 ;
     RECT  23.845 115.152 24.008 115.656 ;
     RECT  21.604 142.896 24.008 142.92 ;
     RECT  24.008 2.148 24.112 168.492 ;
     RECT  24.112 2.418 24.304 168.222 ;
     RECT  24.304 40.608 26.708 40.632 ;
     RECT  24.304 115.152 26.708 115.656 ;
     RECT  24.304 142.896 26.708 142.92 ;
     RECT  26.708 2.148 26.812 168.492 ;
     RECT  26.812 2.418 27.004 168.222 ;
     RECT  27.004 115.152 27.749 115.656 ;
     RECT  27.749 115.344 27.821 115.656 ;
     RECT  27.004 40.608 29.408 40.632 ;
     RECT  27.821 115.344 29.408 115.368 ;
     RECT  27.004 142.896 29.408 142.92 ;
     RECT  29.408 2.148 29.512 168.492 ;
     RECT  29.512 2.418 29.704 168.222 ;
     RECT  29.704 40.608 29.801 40.728 ;
     RECT  29.801 40.704 30.769 40.728 ;
     RECT  30.769 40.608 30.809 40.728 ;
     RECT  30.809 40.608 32.108 40.632 ;
     RECT  29.704 115.344 32.108 115.368 ;
     RECT  29.704 142.896 32.108 142.92 ;
     RECT  32.108 2.148 32.212 168.492 ;
     RECT  32.212 2.418 32.404 168.222 ;
     RECT  32.404 40.608 34.765 40.632 ;
     RECT  34.765 40.608 34.808 40.872 ;
     RECT  32.404 115.344 34.808 115.368 ;
     RECT  34.765 122.928 34.808 122.952 ;
     RECT  32.404 142.896 34.808 142.92 ;
     RECT  34.808 2.148 34.912 168.492 ;
     RECT  34.912 2.418 35.104 168.222 ;
     RECT  35.104 116.832 35.219 124.296 ;
     RECT  35.219 122.496 35.525 124.296 ;
     RECT  35.525 124.176 35.555 124.296 ;
     RECT  35.104 128.784 35.561 129.384 ;
     RECT  35.555 124.272 35.777 124.296 ;
     RECT  35.525 122.496 35.849 122.952 ;
     RECT  35.219 116.832 35.987 121.464 ;
     RECT  35.104 130.56 36.029 130.584 ;
     RECT  35.561 129.36 36.065 129.384 ;
     RECT  35.987 117.408 36.083 121.464 ;
     RECT  36.083 120.672 36.173 121.464 ;
     RECT  35.849 122.496 36.173 122.664 ;
     RECT  36.083 117.408 36.317 119.688 ;
     RECT  35.104 114.528 36.461 115.368 ;
     RECT  36.317 117.408 36.508 118.344 ;
     RECT  36.173 120.816 36.533 121.368 ;
     RECT  35.104 125.472 36.533 126.456 ;
     RECT  35.104 127.68 36.925 127.704 ;
     RECT  36.925 127.632 37.199 127.704 ;
     RECT  37.069 129.264 37.199 129.288 ;
     RECT  36.508 117.408 37.285 118.2 ;
     RECT  36.317 119.664 37.285 119.688 ;
     RECT  36.173 122.544 37.321 122.664 ;
     RECT  37.177 123.648 37.321 123.672 ;
     RECT  37.285 117.36 37.34 118.2 ;
     RECT  35.104 113.184 37.349 113.4 ;
     RECT  37.321 122.544 37.357 123.672 ;
     RECT  37.357 122.496 37.381 124.296 ;
     RECT  36.533 125.472 37.381 125.736 ;
     RECT  37.199 127.632 37.381 129.288 ;
     RECT  37.141 134.352 37.381 134.376 ;
     RECT  35.104 40.848 37.508 40.872 ;
     RECT  37.465 97.92 37.508 97.944 ;
     RECT  37.349 113.184 37.508 113.976 ;
     RECT  36.461 115.344 37.508 115.368 ;
     RECT  37.34 116.4 37.508 118.2 ;
     RECT  37.285 119.664 37.508 120.264 ;
     RECT  36.533 121.344 37.508 121.368 ;
     RECT  37.381 122.496 37.508 125.736 ;
     RECT  37.381 126.768 37.508 129.288 ;
     RECT  36.961 131.04 37.508 131.064 ;
     RECT  37.381 134.352 37.508 135.144 ;
     RECT  35.104 142.896 37.508 142.92 ;
     RECT  37.508 2.148 37.612 168.492 ;
     RECT  37.612 2.418 37.804 168.222 ;
     RECT  37.804 97.392 37.955 97.944 ;
     RECT  37.825 170.4 37.957 170.424 ;
     RECT  37.955 97.392 37.996 97.416 ;
     RECT  37.804 132.768 38.003 132.792 ;
     RECT  37.804 116.832 38.009 119.016 ;
     RECT  37.804 142.896 38.009 143.112 ;
     RECT  37.957 170.4 38.044 170.52 ;
     RECT  38.009 118.128 38.099 119.016 ;
     RECT  37.804 120.192 38.099 125.736 ;
     RECT  37.804 113.184 38.147 113.208 ;
     RECT  37.804 114.72 38.147 115.368 ;
     RECT  37.804 147.216 38.147 147.672 ;
     RECT  37.804 165.312 38.147 166.44 ;
     RECT  38.044 170.4 38.147 170.424 ;
     RECT  37.804 134.352 38.153 137.352 ;
     RECT  37.804 131.088 38.188 131.544 ;
     RECT  37.804 161.904 38.189 162.888 ;
     RECT  38.147 147.552 38.195 147.672 ;
     RECT  38.147 165.312 38.195 165.912 ;
     RECT  38.099 120.192 38.225 120.216 ;
     RECT  37.804 138.336 38.225 140.232 ;
     RECT  38.225 138.336 38.243 139.032 ;
     RECT  38.195 147.552 38.243 147.576 ;
     RECT  38.189 161.904 38.291 162.216 ;
     RECT  38.195 165.792 38.305 165.912 ;
     RECT  38.243 138.336 38.339 138.456 ;
     RECT  37.804 157.44 38.339 157.896 ;
     RECT  38.099 118.128 38.369 118.152 ;
     RECT  38.291 161.904 38.377 161.928 ;
     RECT  38.153 134.352 38.387 135.192 ;
     RECT  38.153 136.416 38.387 137.352 ;
     RECT  38.339 138.336 38.387 138.36 ;
     RECT  38.009 116.832 38.405 116.856 ;
     RECT  38.387 134.592 38.428 135.192 ;
     RECT  38.305 165.84 38.483 165.912 ;
     RECT  38.225 140.208 38.579 140.232 ;
     RECT  37.804 144.24 38.585 144.6 ;
     RECT  38.585 144.576 38.627 144.6 ;
     RECT  37.804 153.12 38.627 153.336 ;
     RECT  37.804 163.92 38.627 163.944 ;
     RECT  37.804 148.8 38.665 150.504 ;
     RECT  38.339 157.44 38.665 157.464 ;
     RECT  38.483 165.84 38.668 165.864 ;
     RECT  38.627 153.12 38.701 153.144 ;
     RECT  38.009 142.896 38.729 143.064 ;
     RECT  38.665 149.328 38.771 150.504 ;
     RECT  37.804 52.464 38.801 53.016 ;
     RECT  37.804 167.472 38.801 167.64 ;
     RECT  38.099 124.8 38.819 125.736 ;
     RECT  37.804 94.08 38.869 94.104 ;
     RECT  38.869 93.696 38.909 94.104 ;
     RECT  38.099 121.344 38.981 123.672 ;
     RECT  38.801 167.472 38.981 167.496 ;
     RECT  37.804 129.936 39.052 129.96 ;
     RECT  39.052 129.936 39.053 130.008 ;
     RECT  37.804 126.768 39.085 126.792 ;
     RECT  37.804 49.824 39.157 49.848 ;
     RECT  39.116 75.792 39.157 75.816 ;
     RECT  39.157 75.264 39.203 75.816 ;
     RECT  39.121 54.096 39.205 54.12 ;
     RECT  39.085 126.768 39.212 127.656 ;
     RECT  37.804 48.48 39.229 48.504 ;
     RECT  39.157 49.584 39.229 49.848 ;
     RECT  39.157 96.336 39.241 96.36 ;
     RECT  39.229 48.48 39.265 49.848 ;
     RECT  38.797 50.832 39.265 50.856 ;
     RECT  38.428 134.592 39.373 135.144 ;
     RECT  39.265 91.104 39.445 91.128 ;
     RECT  39.373 134.544 39.445 135.144 ;
     RECT  38.909 93.696 39.517 93.72 ;
     RECT  37.804 47.232 39.553 47.256 ;
     RECT  38.801 52.464 39.553 52.488 ;
     RECT  39.265 139.392 39.553 139.416 ;
     RECT  39.212 126.768 39.589 127.752 ;
     RECT  39.085 128.784 39.589 128.808 ;
     RECT  39.553 47.04 39.697 47.256 ;
     RECT  39.265 48.48 39.697 50.856 ;
     RECT  39.445 91.104 39.697 91.608 ;
     RECT  39.517 92.784 39.697 93.72 ;
     RECT  39.661 84.864 39.733 84.888 ;
     RECT  37.804 40.848 39.829 40.872 ;
     RECT  39.409 137.904 39.829 137.928 ;
     RECT  39.553 139.392 39.829 140.184 ;
     RECT  39.053 129.984 39.913 130.008 ;
     RECT  38.819 124.8 39.949 124.872 ;
     RECT  39.949 124.752 39.973 124.872 ;
     RECT  38.981 121.344 39.985 123.144 ;
     RECT  39.409 89.472 40.028 89.496 ;
     RECT  39.697 91.104 40.028 93.72 ;
     RECT  39.697 47.04 40.057 50.856 ;
     RECT  37.804 83.04 40.069 83.064 ;
     RECT  39.733 84.096 40.069 84.888 ;
     RECT  39.013 109.392 40.069 109.416 ;
     RECT  39.985 120.864 40.069 123.144 ;
     RECT  39.973 124.464 40.093 124.872 ;
     RECT  39.829 40.56 40.208 40.872 ;
     RECT  39.481 44.448 40.208 44.472 ;
     RECT  39.805 45.552 40.208 45.576 ;
     RECT  40.057 46.848 40.208 50.856 ;
     RECT  39.553 51.888 40.208 52.488 ;
     RECT  39.203 75.264 40.208 75.288 ;
     RECT  40.069 83.04 40.208 84.888 ;
     RECT  40.028 88.848 40.208 93.72 ;
     RECT  40.069 109.392 40.208 109.752 ;
     RECT  38.147 115.344 40.208 115.368 ;
     RECT  40.069 120.576 40.208 123.144 ;
     RECT  40.093 124.464 40.208 124.92 ;
     RECT  39.589 126.768 40.208 128.808 ;
     RECT  39.913 129.984 40.208 130.056 ;
     RECT  38.188 131.088 40.208 131.112 ;
     RECT  39.913 133.2 40.208 133.224 ;
     RECT  39.445 134.544 40.208 135.24 ;
     RECT  39.829 137.904 40.208 140.184 ;
     RECT  38.729 143.04 40.208 143.064 ;
     RECT  38.771 149.904 40.208 149.928 ;
     RECT  40.208 2.148 40.312 168.492 ;
     RECT  40.312 2.418 40.504 168.222 ;
     RECT  40.504 44.352 40.825 54.12 ;
     RECT  40.504 58.128 40.835 58.152 ;
     RECT  40.504 103.104 40.931 103.8 ;
     RECT  40.504 122.544 41.027 125.448 ;
     RECT  40.504 142.512 41.033 142.536 ;
     RECT  41.027 122.928 41.075 125.448 ;
     RECT  41.075 122.928 41.321 123.672 ;
     RECT  40.504 114.528 41.465 114.552 ;
     RECT  41.321 122.928 41.465 123.336 ;
     RECT  40.825 44.352 41.497 53.784 ;
     RECT  40.504 137.664 41.533 138.36 ;
     RECT  40.504 139.488 41.533 139.992 ;
     RECT  41.075 124.848 41.557 125.448 ;
     RECT  40.504 126.768 41.557 127.272 ;
     RECT  40.504 91.008 41.569 94.2 ;
     RECT  40.504 130.56 41.569 130.68 ;
     RECT  40.504 89.472 41.605 89.496 ;
     RECT  40.504 83.04 41.677 83.064 ;
     RECT  40.504 84.096 41.677 84.12 ;
     RECT  41.557 124.848 41.681 127.272 ;
     RECT  41.677 83.04 41.713 84.12 ;
     RECT  41.605 89.472 41.713 89.784 ;
     RECT  41.569 91.008 41.749 94.392 ;
     RECT  40.504 96 41.749 96.984 ;
     RECT  41.569 130.56 41.749 130.872 ;
     RECT  41.749 91.008 41.785 96.984 ;
     RECT  40.504 87.456 41.821 87.96 ;
     RECT  41.713 89.088 41.821 89.784 ;
     RECT  41.749 130.56 41.821 131.256 ;
     RECT  41.749 114 41.833 114.024 ;
     RECT  41.821 87.456 41.857 89.784 ;
     RECT  41.857 87.456 41.893 89.88 ;
     RECT  41.785 90.912 41.893 96.984 ;
     RECT  41.821 130.56 41.929 131.832 ;
     RECT  41.929 130.56 41.965 131.928 ;
     RECT  41.893 87.456 42.001 96.984 ;
     RECT  41.965 130.56 42.073 132.6 ;
     RECT  42.073 130.56 42.109 132.792 ;
     RECT  41.533 137.664 42.145 139.992 ;
     RECT  42.145 137.664 42.181 140.184 ;
     RECT  42.109 130.56 42.325 132.984 ;
     RECT  40.504 86.016 42.389 86.04 ;
     RECT  42.001 87.36 42.389 96.984 ;
     RECT  41.465 122.928 42.469 123.24 ;
     RECT  41.569 80.88 42.613 80.904 ;
     RECT  42.325 130.56 42.649 133.08 ;
     RECT  41.497 44.16 42.661 53.784 ;
     RECT  42.613 64.416 42.661 64.536 ;
     RECT  41.713 82.608 42.709 84.12 ;
     RECT  42.649 130.56 42.709 133.272 ;
     RECT  42.661 64.416 42.757 64.632 ;
     RECT  40.504 40.56 42.908 40.584 ;
     RECT  42.757 64.416 42.908 64.728 ;
     RECT  42.613 80.352 42.908 80.904 ;
     RECT  42.709 82.608 42.908 84.36 ;
     RECT  42.709 107.28 42.908 108.216 ;
     RECT  40.504 120.576 42.908 121.368 ;
     RECT  42.469 122.928 42.908 123.72 ;
     RECT  41.681 124.848 42.908 125.448 ;
     RECT  41.681 126.768 42.908 127.272 ;
     RECT  42.908 2.148 43.012 41.052 ;
     RECT  42.908 62.628 43.012 84.36 ;
     RECT  42.908 105.828 43.012 127.452 ;
     RECT  42.908 149.028 43.012 168.492 ;
     RECT  42.709 130.368 43.081 133.272 ;
     RECT  43.081 129.456 43.2 133.272 ;
     RECT  42.181 137.28 43.2 140.184 ;
     RECT  43.012 2.418 43.204 40.782 ;
     RECT  43.012 62.898 43.204 84.36 ;
     RECT  43.012 106.098 43.204 127.368 ;
     RECT  43.012 149.298 43.204 168.222 ;
     RECT  43.204 107.28 43.265 108.552 ;
     RECT  42.661 43.968 43.272 53.784 ;
     RECT  40.504 60.576 43.272 61.08 ;
     RECT  42.389 86.016 43.272 96.984 ;
     RECT  40.931 103.776 43.272 103.8 ;
     RECT  43.2 129.456 43.272 140.184 ;
     RECT  40.504 147.072 43.272 147.144 ;
     RECT  43.272 129.456 43.331 147.144 ;
     RECT  43.265 107.808 43.409 108.552 ;
     RECT  43.204 64.608 43.553 64.968 ;
     RECT  43.204 84.048 43.553 84.36 ;
     RECT  43.204 126.768 43.877 127.368 ;
     RECT  43.204 83.04 44.732 83.064 ;
     RECT  43.553 84.048 44.732 84.12 ;
     RECT  43.204 40.56 45.608 40.584 ;
     RECT  43.553 64.944 45.608 64.968 ;
     RECT  44.732 83.04 45.608 84.12 ;
     RECT  43.409 107.808 45.608 107.832 ;
     RECT  43.204 121.344 45.608 121.368 ;
     RECT  43.204 122.928 45.608 122.952 ;
     RECT  43.204 124.848 45.608 124.872 ;
     RECT  43.877 127.248 45.608 127.368 ;
     RECT  45.608 2.148 45.712 41.052 ;
     RECT  45.608 62.628 45.712 84.252 ;
     RECT  45.608 105.828 45.712 127.452 ;
     RECT  45.608 149.028 45.712 168.492 ;
     RECT  45.712 2.418 45.904 40.872 ;
     RECT  45.712 62.898 45.904 84.12 ;
     RECT  45.712 106.098 45.904 127.368 ;
     RECT  45.712 149.298 45.904 168.222 ;
     RECT  45.904 122.832 46.547 122.952 ;
     RECT  45.904 127.104 46.649 127.368 ;
     RECT  45.904 84.048 46.753 84.12 ;
     RECT  46.753 84.048 46.793 84.168 ;
     RECT  46.649 127.104 46.829 127.272 ;
     RECT  46.547 122.928 46.865 122.952 ;
     RECT  45.904 40.56 46.901 40.872 ;
     RECT  46.901 40.848 48.308 40.872 ;
     RECT  45.904 83.04 48.308 83.064 ;
     RECT  46.793 84.096 48.308 84.168 ;
     RECT  45.904 121.344 48.308 121.368 ;
     RECT  45.904 124.848 48.308 124.872 ;
     RECT  46.829 127.248 48.308 127.272 ;
     RECT  48.308 2.148 48.412 41.052 ;
     RECT  48.308 62.628 48.412 84.252 ;
     RECT  48.308 105.828 48.412 127.452 ;
     RECT  48.308 149.028 48.412 168.492 ;
     RECT  48.412 2.418 48.604 40.872 ;
     RECT  48.412 62.898 48.604 84.168 ;
     RECT  48.412 106.098 48.604 127.272 ;
     RECT  48.412 149.298 48.604 168.222 ;
     RECT  48.604 83.04 48.892 84.168 ;
     RECT  48.604 40.848 51.008 40.872 ;
     RECT  48.892 83.04 51.008 83.064 ;
     RECT  48.892 84.048 51.008 84.168 ;
     RECT  49.741 105.744 51.008 105.768 ;
     RECT  48.604 121.344 51.008 121.368 ;
     RECT  48.604 124.848 51.008 124.872 ;
     RECT  48.604 127.248 51.008 127.272 ;
     RECT  51.008 2.148 51.112 41.052 ;
     RECT  51.008 62.628 51.112 84.252 ;
     RECT  51.008 105.744 51.112 127.452 ;
     RECT  51.008 149.028 51.112 168.492 ;
     RECT  51.112 2.418 51.304 40.872 ;
     RECT  51.112 62.898 51.304 84.168 ;
     RECT  51.112 105.744 51.304 127.272 ;
     RECT  51.112 149.298 51.304 168.222 ;
     RECT  51.304 40.848 53.708 40.872 ;
     RECT  51.304 83.04 53.708 83.064 ;
     RECT  51.304 84.048 53.708 84.168 ;
     RECT  51.304 105.744 53.708 105.768 ;
     RECT  51.304 121.344 53.708 121.368 ;
     RECT  51.304 124.848 53.708 124.872 ;
     RECT  51.304 127.248 53.708 127.272 ;
     RECT  53.708 2.148 53.812 41.052 ;
     RECT  53.708 62.628 53.812 84.252 ;
     RECT  53.708 105.744 53.812 127.452 ;
     RECT  53.708 149.028 53.812 168.492 ;
     RECT  53.812 2.418 54.004 40.872 ;
     RECT  53.812 62.898 54.004 84.168 ;
     RECT  53.812 105.744 54.004 127.272 ;
     RECT  53.812 149.298 54.004 168.222 ;
     RECT  54.004 83.04 54.209 84.168 ;
     RECT  54.004 124.848 55.1 124.872 ;
     RECT  54.004 127.248 55.105 127.272 ;
     RECT  55.1 124.8 55.109 124.872 ;
     RECT  55.105 127.104 55.433 127.272 ;
     RECT  55.433 127.104 55.709 127.128 ;
     RECT  54.004 121.344 55.813 121.368 ;
     RECT  54.004 40.848 56.408 40.872 ;
     RECT  54.209 83.04 56.408 84.072 ;
     RECT  54.004 105.744 56.408 105.768 ;
     RECT  55.813 121.104 56.408 121.368 ;
     RECT  55.109 124.8 56.408 124.824 ;
     RECT  55.709 126.528 56.408 127.128 ;
     RECT  56.408 2.148 56.512 41.052 ;
     RECT  56.408 62.628 56.512 84.252 ;
     RECT  56.408 105.744 56.512 127.452 ;
     RECT  56.408 149.028 56.512 168.492 ;
     RECT  56.512 2.418 56.704 40.872 ;
     RECT  56.512 62.898 56.704 84.072 ;
     RECT  56.512 105.744 56.704 127.182 ;
     RECT  56.512 149.298 56.704 168.222 ;
     RECT  56.704 40.752 57.517 40.872 ;
     RECT  57.517 40.752 59.108 40.92 ;
     RECT  56.704 83.04 59.108 84.072 ;
     RECT  56.704 105.744 59.108 105.768 ;
     RECT  56.704 121.104 59.108 121.128 ;
     RECT  56.704 124.8 59.108 124.824 ;
     RECT  59.108 2.148 59.212 41.052 ;
     RECT  59.108 62.628 59.212 84.252 ;
     RECT  59.108 105.744 59.212 127.452 ;
     RECT  59.108 149.028 59.212 168.492 ;
     RECT  59.212 2.418 59.404 40.92 ;
     RECT  59.212 62.898 59.404 84.072 ;
     RECT  59.212 105.744 59.404 127.182 ;
     RECT  59.212 149.298 59.404 168.222 ;
     RECT  59.404 40.848 61.808 40.92 ;
     RECT  59.404 83.04 61.808 84.072 ;
     RECT  59.404 105.744 61.808 105.768 ;
     RECT  59.404 121.104 61.808 121.128 ;
     RECT  59.404 124.8 61.808 124.824 ;
     RECT  61.808 2.148 61.912 41.052 ;
     RECT  61.808 62.628 61.912 84.252 ;
     RECT  61.808 105.744 61.912 127.452 ;
     RECT  61.808 149.028 61.912 168.492 ;
     RECT  61.912 2.418 62.104 40.92 ;
     RECT  61.912 62.898 62.104 84.072 ;
     RECT  61.912 105.744 62.104 127.182 ;
     RECT  61.912 149.298 62.104 168.222 ;
     RECT  62.104 83.04 64.501 84.072 ;
     RECT  62.104 40.848 64.508 40.92 ;
     RECT  64.501 83.04 64.508 84.168 ;
     RECT  62.104 105.744 64.508 105.768 ;
     RECT  62.104 121.104 64.508 121.128 ;
     RECT  62.104 124.8 64.508 124.824 ;
     RECT  64.508 2.148 64.612 41.052 ;
     RECT  64.508 62.628 64.612 84.252 ;
     RECT  64.508 105.744 64.612 127.452 ;
     RECT  64.508 149.028 64.612 168.492 ;
     RECT  64.612 2.418 64.804 40.92 ;
     RECT  64.612 62.898 64.804 84.168 ;
     RECT  64.612 105.744 64.804 127.182 ;
     RECT  64.612 149.298 64.804 168.222 ;
     RECT  64.804 120.864 65.027 121.128 ;
     RECT  64.804 82.656 65.117 84.168 ;
     RECT  64.804 105.744 65.149 106.344 ;
     RECT  64.804 107.76 65.161 108.312 ;
     RECT  64.804 40.752 65.267 40.92 ;
     RECT  65.149 105.456 65.363 106.344 ;
     RECT  65.161 108.288 65.485 108.312 ;
     RECT  65.117 82.656 65.555 82.68 ;
     RECT  64.804 79.248 65.729 79.272 ;
     RECT  65.117 83.712 66.125 84.168 ;
     RECT  65.267 40.848 67.208 40.92 ;
     RECT  64.804 65.712 67.208 65.736 ;
     RECT  64.804 75.456 67.208 75.48 ;
     RECT  66.589 78.624 67.208 78.648 ;
     RECT  66.125 83.712 67.208 84.072 ;
     RECT  65.363 105.744 67.208 106.344 ;
     RECT  65.027 120.864 67.208 120.888 ;
     RECT  64.804 124.8 67.208 124.824 ;
     RECT  67.208 2.148 67.312 41.052 ;
     RECT  67.208 62.628 67.312 84.252 ;
     RECT  67.208 105.744 67.312 127.452 ;
     RECT  67.208 149.028 67.312 168.492 ;
     RECT  67.312 2.418 67.504 40.92 ;
     RECT  67.312 62.898 67.504 84.072 ;
     RECT  67.312 105.744 67.504 127.182 ;
     RECT  67.312 149.298 67.504 168.222 ;
     RECT  67.504 40.848 69.908 40.92 ;
     RECT  67.504 65.712 69.908 65.736 ;
     RECT  67.504 75.456 69.908 75.48 ;
     RECT  67.504 83.808 69.908 84.072 ;
     RECT  67.504 105.744 69.908 105.768 ;
     RECT  67.504 120.864 69.908 120.888 ;
     RECT  67.504 124.8 69.908 124.824 ;
     RECT  69.908 2.148 70.012 41.052 ;
     RECT  69.908 62.628 70.012 84.252 ;
     RECT  69.908 105.744 70.012 127.452 ;
     RECT  69.908 149.028 70.012 168.492 ;
     RECT  70.012 2.418 70.204 40.92 ;
     RECT  70.012 62.898 70.204 84.12 ;
     RECT  70.012 105.744 70.204 127.182 ;
     RECT  70.012 149.298 70.204 168.222 ;
     RECT  70.204 83.712 70.691 84.12 ;
     RECT  43.331 129.6 70.691 147.144 ;
     RECT  70.204 124.8 72.229 124.824 ;
     RECT  72.229 125.856 72.277 125.88 ;
     RECT  70.204 40.848 72.608 40.92 ;
     RECT  70.204 65.712 72.608 65.736 ;
     RECT  70.204 75.456 72.608 75.48 ;
     RECT  70.691 83.808 72.608 84.12 ;
     RECT  70.204 105.744 72.608 105.768 ;
     RECT  70.204 120.864 72.608 120.888 ;
     RECT  72.229 124.08 72.608 124.824 ;
     RECT  72.277 125.856 72.608 126.024 ;
     RECT  72.608 2.148 72.712 41.052 ;
     RECT  72.608 62.628 72.712 84.252 ;
     RECT  72.608 105.744 72.712 127.452 ;
     RECT  72.608 149.028 72.712 168.492 ;
     RECT  72.712 2.418 72.904 40.92 ;
     RECT  72.712 62.898 72.904 84.12 ;
     RECT  72.712 105.744 72.904 127.182 ;
     RECT  72.712 149.298 72.904 168.222 ;
     RECT  72.904 124.08 73.829 124.872 ;
     RECT  72.904 122.592 73.868 122.616 ;
     RECT  73.868 122.256 73.897 122.616 ;
     RECT  73.829 124.08 73.909 124.392 ;
     RECT  72.904 125.904 73.909 125.928 ;
     RECT  73.909 125.904 74.005 126.024 ;
     RECT  73.909 123.696 74.045 124.392 ;
     RECT  72.904 120.864 74.365 120.888 ;
     RECT  73.897 122.112 74.365 122.616 ;
     RECT  70.691 129.6 74.653 147.192 ;
     RECT  74.653 129.504 74.689 147.192 ;
     RECT  74.045 123.936 74.869 124.392 ;
     RECT  72.904 83.808 75.049 84.12 ;
     RECT  74.005 125.904 75.085 126.744 ;
     RECT  43.272 43.2 75.12 61.08 ;
     RECT  43.272 86.016 75.12 103.8 ;
     RECT  74.689 128.784 75.12 147.192 ;
     RECT  75.049 83.808 75.121 84.408 ;
     RECT  72.904 40.848 75.157 40.92 ;
     RECT  75.12 103.776 75.157 103.8 ;
     RECT  72.904 105.744 75.203 105.768 ;
     RECT  75.121 83.808 75.269 84.984 ;
     RECT  75.12 87.168 75.305 96.984 ;
     RECT  75.157 40.848 75.308 41.16 ;
     RECT  72.904 65.712 75.308 65.736 ;
     RECT  72.904 75.456 75.308 75.48 ;
     RECT  75.269 83.808 75.308 84.408 ;
     RECT  74.365 120.864 75.308 122.616 ;
     RECT  74.869 123.936 75.308 124.68 ;
     RECT  75.085 125.904 75.308 127.272 ;
     RECT  75.12 43.968 75.341 53.88 ;
     RECT  75.308 62.628 75.341 84.408 ;
     RECT  75.12 128.784 75.341 140.184 ;
     RECT  75.308 2.148 75.412 41.16 ;
     RECT  75.341 62.628 75.412 84.252 ;
     RECT  75.308 105.828 75.412 127.452 ;
     RECT  75.308 149.028 75.412 168.492 ;
     RECT  75.341 43.968 75.413 53.784 ;
     RECT  75.157 103.776 75.413 103.848 ;
     RECT  75.341 128.784 75.413 139.992 ;
     RECT  75.12 147.072 75.413 147.192 ;
     RECT  75.412 106.098 75.445 127.452 ;
     RECT  75.305 87.264 75.485 96.984 ;
     RECT  75.413 130.464 75.485 139.992 ;
     RECT  75.485 130.464 75.521 139.896 ;
     RECT  75.413 147.12 75.521 147.192 ;
     RECT  75.412 2.418 75.604 41.16 ;
     RECT  75.412 62.898 75.604 84.168 ;
     RECT  75.445 106.098 75.604 127.56 ;
     RECT  75.412 149.298 75.604 168.222 ;
     RECT  75.604 124.656 75.665 127.56 ;
     RECT  75.413 128.784 75.701 129.432 ;
     RECT  75.604 40.848 75.731 41.16 ;
     RECT  75.665 125.04 75.731 127.56 ;
     RECT  75.731 125.04 75.773 127.464 ;
     RECT  75.701 128.784 75.827 128.856 ;
     RECT  75.604 75.456 75.917 75.576 ;
     RECT  75.773 125.04 75.989 127.368 ;
     RECT  75.989 125.04 76.025 127.08 ;
     RECT  76.025 125.088 76.067 127.08 ;
     RECT  76.067 125.088 76.097 126.84 ;
     RECT  76.097 126.816 76.133 126.84 ;
     RECT  75.521 147.168 76.133 147.192 ;
     RECT  75.413 43.968 76.169 53.496 ;
     RECT  76.097 125.664 76.169 125.688 ;
     RECT  75.521 130.512 76.169 139.896 ;
     RECT  75.917 75.552 76.259 75.576 ;
     RECT  76.169 130.56 76.313 139.896 ;
     RECT  76.313 131.232 76.349 139.896 ;
     RECT  76.349 131.232 76.421 133.656 ;
     RECT  76.349 134.88 76.457 139.896 ;
     RECT  75.604 73.296 76.709 73.32 ;
     RECT  76.457 135.456 76.709 139.896 ;
     RECT  75.604 120.864 77.281 121.128 ;
     RECT  75.604 122.112 77.281 122.184 ;
     RECT  76.421 131.424 77.425 133.656 ;
     RECT  77.425 131.424 77.461 134.04 ;
     RECT  77.461 130.512 77.749 134.04 ;
     RECT  75.731 40.848 78.008 40.92 ;
     RECT  76.169 44.064 78.008 53.496 ;
     RECT  75.12 60.576 78.008 61.08 ;
     RECT  75.604 65.712 78.008 65.736 ;
     RECT  77.461 70.656 78.008 70.68 ;
     RECT  77.461 73.2 78.008 73.224 ;
     RECT  75.604 82.992 78.008 84.168 ;
     RECT  75.12 86.016 78.008 86.04 ;
     RECT  75.485 87.264 78.008 96.696 ;
     RECT  75.12 98.688 78.008 98.712 ;
     RECT  75.413 103.776 78.008 103.8 ;
     RECT  77.281 120.864 78.008 122.184 ;
     RECT  75.827 128.832 78.008 128.856 ;
     RECT  77.749 130.512 78.008 134.376 ;
     RECT  76.709 135.456 78.008 139.8 ;
     RECT  78.008 2.148 78.112 168.492 ;
     RECT  78.112 2.418 78.304 168.222 ;
     RECT  78.304 133.344 78.419 134.376 ;
     RECT  78.304 135.6 78.419 135.624 ;
     RECT  78.419 133.344 78.617 134.04 ;
     RECT  78.304 67.824 78.659 68.232 ;
     RECT  78.304 70.128 78.689 70.152 ;
     RECT  78.304 136.656 78.689 136.776 ;
     RECT  78.304 65.712 79.057 66.12 ;
     RECT  78.659 67.824 79.265 67.848 ;
     RECT  78.304 44.064 79.441 47.688 ;
     RECT  78.304 40.848 79.523 40.92 ;
     RECT  78.617 134.016 80.06 134.04 ;
     RECT  78.689 136.752 80.101 136.776 ;
     RECT  79.523 40.848 80.708 40.872 ;
     RECT  79.441 44.064 80.708 47.88 ;
     RECT  78.304 60.576 80.708 61.176 ;
     RECT  79.057 65.712 80.708 65.736 ;
     RECT  78.304 82.992 80.708 84.168 ;
     RECT  78.304 85.392 80.708 85.416 ;
     RECT  78.304 87.264 80.708 90.888 ;
     RECT  78.304 98.688 80.708 98.712 ;
     RECT  78.304 103.776 80.708 103.8 ;
     RECT  78.304 120.864 80.708 121.704 ;
     RECT  80.06 134.016 80.708 134.184 ;
     RECT  80.101 136.272 80.708 136.776 ;
     RECT  80.708 2.148 80.812 168.492 ;
     RECT  80.812 2.418 81.004 168.222 ;
     RECT  83.269 111.84 83.329 111.864 ;
     RECT  81.004 40.848 83.408 40.872 ;
     RECT  81.004 44.064 83.408 47.88 ;
     RECT  81.004 60.576 83.408 61.176 ;
     RECT  81.004 65.712 83.408 65.736 ;
     RECT  82.885 77.952 83.408 77.976 ;
     RECT  81.004 82.992 83.408 84.168 ;
     RECT  81.004 85.392 83.408 85.416 ;
     RECT  81.004 87.264 83.408 90.888 ;
     RECT  81.004 98.688 83.408 98.712 ;
     RECT  81.004 103.776 83.408 103.8 ;
     RECT  83.329 111.648 83.408 111.864 ;
     RECT  81.004 120.864 83.408 121.704 ;
     RECT  81.004 136.272 83.408 136.776 ;
     RECT  83.408 2.148 83.512 168.492 ;
     RECT  83.512 2.418 83.704 168.222 ;
     RECT  83.704 120.864 84.371 121.704 ;
     RECT  83.704 114.528 84.385 115.128 ;
     RECT  84.385 114.528 84.665 114.552 ;
     RECT  83.704 40.848 86.108 40.872 ;
     RECT  83.704 44.064 86.108 47.88 ;
     RECT  83.704 60.576 86.108 61.176 ;
     RECT  83.704 65.712 86.108 65.736 ;
     RECT  83.704 77.952 86.108 77.976 ;
     RECT  83.704 82.992 86.108 85.416 ;
     RECT  83.704 87.264 86.108 90.888 ;
     RECT  83.704 98.688 86.108 98.712 ;
     RECT  83.704 103.776 86.108 103.8 ;
     RECT  85.189 105.984 86.108 106.008 ;
     RECT  83.704 111.648 86.108 111.816 ;
     RECT  85.189 114.48 86.108 114.504 ;
     RECT  84.371 121.68 86.108 121.704 ;
     RECT  83.704 136.416 86.108 136.776 ;
     RECT  86.108 2.148 86.212 168.492 ;
     RECT  86.212 2.418 86.404 168.222 ;
     RECT  86.404 111.408 86.609 111.672 ;
     RECT  86.609 111.408 86.681 111.576 ;
     RECT  86.404 83.04 87.617 85.416 ;
     RECT  88.225 74.304 88.297 74.328 ;
     RECT  86.404 77.952 88.597 77.976 ;
     RECT  86.404 105.888 88.693 105.912 ;
     RECT  88.297 74.064 88.765 74.328 ;
     RECT  86.404 40.848 88.808 40.872 ;
     RECT  86.404 44.064 88.808 47.88 ;
     RECT  86.404 60.576 88.808 61.176 ;
     RECT  86.404 65.712 88.808 65.736 ;
     RECT  88.765 73.248 88.808 74.328 ;
     RECT  88.597 77.664 88.808 77.976 ;
     RECT  87.617 83.04 88.808 85.176 ;
     RECT  86.404 87.264 88.808 90.888 ;
     RECT  86.404 98.688 88.808 98.712 ;
     RECT  88.693 100.272 88.808 100.296 ;
     RECT  86.404 103.776 88.808 103.8 ;
     RECT  88.693 105.744 88.808 105.912 ;
     RECT  86.681 111.408 88.808 111.432 ;
     RECT  86.404 136.416 88.808 136.488 ;
     RECT  88.808 2.148 88.912 168.492 ;
     RECT  88.912 2.418 89.104 168.222 ;
     RECT  89.104 44.064 89.219 47.88 ;
     RECT  89.104 52.704 89.219 53.256 ;
     RECT  89.104 141.264 89.219 141.336 ;
     RECT  89.104 139.632 89.26 140.136 ;
     RECT  89.104 136.416 89.267 136.488 ;
     RECT  89.219 141.312 89.507 141.336 ;
     RECT  89.104 96.432 89.747 97.272 ;
     RECT  89.104 77.52 90.083 77.976 ;
     RECT  89.104 100.272 90.097 100.296 ;
     RECT  89.219 44.064 90.101 47.448 ;
     RECT  89.104 55.536 90.169 56.424 ;
     RECT  89.104 57.648 90.169 57.672 ;
     RECT  89.104 40.416 90.205 40.872 ;
     RECT  90.097 99.696 90.236 100.296 ;
     RECT  90.229 38.4 90.241 38.424 ;
     RECT  90.205 39.888 90.241 40.872 ;
     RECT  89.104 42.192 90.241 42.216 ;
     RECT  89.26 139.632 90.241 139.656 ;
     RECT  90.083 77.52 90.323 77.688 ;
     RECT  90.236 99.696 90.323 100.68 ;
     RECT  89.104 111.408 90.323 111.432 ;
     RECT  90.323 100.272 90.421 100.68 ;
     RECT  90.101 44.352 90.425 47.448 ;
     RECT  90.169 55.536 90.425 57.672 ;
     RECT  90.241 139.632 90.469 139.704 ;
     RECT  90.469 138.768 90.515 139.704 ;
     RECT  90.421 100.272 90.565 100.872 ;
     RECT  89.747 96.912 90.745 97.272 ;
     RECT  89.104 98.688 90.745 98.712 ;
     RECT  89.104 82.128 90.901 86.088 ;
     RECT  89.104 87.264 90.901 90.888 ;
     RECT  90.241 38.4 91.177 40.872 ;
     RECT  90.241 42.192 91.177 42.6 ;
     RECT  90.425 44.352 91.285 45.24 ;
     RECT  90.745 96.912 91.285 98.712 ;
     RECT  90.901 82.128 91.393 90.888 ;
     RECT  90.479 55.248 91.429 55.272 ;
     RECT  90.425 56.352 91.429 57.672 ;
     RECT  91.285 96.912 91.501 98.904 ;
     RECT  90.565 100.272 91.501 101.688 ;
     RECT  91.177 38.4 91.508 42.6 ;
     RECT  91.285 43.68 91.508 45.24 ;
     RECT  90.425 46.224 91.508 47.448 ;
     RECT  89.219 53.232 91.508 53.256 ;
     RECT  91.429 55.248 91.508 57.672 ;
     RECT  89.104 60.576 91.508 61.176 ;
     RECT  89.104 65.712 91.508 65.736 ;
     RECT  89.104 73.248 91.508 73.272 ;
     RECT  89.104 74.304 91.508 74.328 ;
     RECT  90.323 77.664 91.508 77.688 ;
     RECT  91.393 81.648 91.508 90.888 ;
     RECT  90.565 95.904 91.508 95.928 ;
     RECT  91.501 96.912 91.508 101.688 ;
     RECT  89.104 103.776 91.508 103.8 ;
     RECT  89.267 136.464 91.508 136.488 ;
     RECT  90.515 138.768 91.508 139.416 ;
     RECT  91.177 141.264 91.508 141.288 ;
     RECT  89.104 142.32 91.508 143.256 ;
     RECT  91.508 2.148 91.612 168.492 ;
     RECT  91.612 2.418 91.804 168.222 ;
     RECT  91.804 37.968 91.901 44.712 ;
     RECT  91.901 42.144 92.045 44.712 ;
     RECT  91.804 87.792 92.045 90.648 ;
     RECT  92.045 90.624 92.153 90.648 ;
     RECT  92.045 87.792 92.161 89.496 ;
     RECT  92.161 88.08 92.261 89.496 ;
     RECT  91.804 73.248 92.291 73.272 ;
     RECT  91.901 37.968 92.339 41.016 ;
     RECT  91.804 47.04 92.369 47.448 ;
     RECT  92.261 88.416 92.369 89.496 ;
     RECT  92.339 39.6 92.387 41.016 ;
     RECT  91.804 74.304 92.723 74.328 ;
     RECT  91.804 141.264 92.821 143.256 ;
     RECT  91.804 52.992 92.869 53.016 ;
     RECT  91.804 54.048 92.869 55.464 ;
     RECT  91.804 98.448 92.869 101.688 ;
     RECT  91.804 139.392 92.869 139.56 ;
     RECT  92.821 140.736 92.869 143.256 ;
     RECT  92.369 47.424 92.873 47.448 ;
     RECT  92.369 88.704 92.909 89.496 ;
     RECT  92.387 39.6 92.945 40.968 ;
     RECT  92.045 42.144 92.945 44.376 ;
     RECT  92.945 40.944 92.981 40.968 ;
     RECT  92.945 42.144 92.981 44.088 ;
     RECT  92.869 138.144 93.013 139.56 ;
     RECT  92.869 140.592 93.013 143.256 ;
     RECT  91.804 77.664 93.337 77.688 ;
     RECT  91.804 95.904 93.373 96.84 ;
     RECT  92.869 97.824 93.373 101.688 ;
     RECT  93.157 89.904 93.452 89.928 ;
     RECT  92.869 52.992 93.548 55.464 ;
     RECT  93.445 47.808 93.589 47.832 ;
     RECT  93.337 77.664 93.625 78.024 ;
     RECT  93.625 77.664 93.913 78.072 ;
     RECT  91.804 56.928 93.925 57.672 ;
     RECT  91.804 65.712 93.925 65.736 ;
     RECT  92.909 88.704 93.98 88.728 ;
     RECT  93.452 89.904 93.98 89.976 ;
     RECT  93.589 47.808 94.021 47.88 ;
     RECT  93.373 95.904 94.021 101.688 ;
     RECT  92.945 39.6 94.057 39.624 ;
     RECT  92.981 42.192 94.057 44.088 ;
     RECT  94.057 39.6 94.093 39.768 ;
     RECT  94.057 41.232 94.093 44.088 ;
     RECT  92.339 37.968 94.208 38.424 ;
     RECT  94.093 39.6 94.208 44.088 ;
     RECT  94.021 47.808 94.208 48.456 ;
     RECT  93.548 52.656 94.208 55.464 ;
     RECT  93.925 56.928 94.208 57.864 ;
     RECT  91.804 60.576 94.208 61.176 ;
     RECT  93.925 65.568 94.208 65.736 ;
     RECT  93.913 77.664 94.208 78.168 ;
     RECT  91.804 81.456 94.208 86.376 ;
     RECT  93.98 88.704 94.208 89.976 ;
     RECT  94.021 94.944 94.208 101.688 ;
     RECT  91.804 103.776 94.208 103.8 ;
     RECT  93.013 138.144 94.208 143.256 ;
     RECT  94.208 2.148 94.312 168.492 ;
     RECT  94.312 2.418 94.504 168.222 ;
     RECT  94.504 94.944 94.637 101.592 ;
     RECT  94.504 103.776 94.925 103.8 ;
     RECT  94.504 37.968 95.213 44.088 ;
     RECT  95.213 37.968 95.393 43.224 ;
     RECT  94.504 52.704 95.653 55.896 ;
     RECT  94.504 56.928 95.653 58.44 ;
     RECT  95.653 52.704 95.749 58.44 ;
     RECT  94.504 80.928 95.749 86.136 ;
     RECT  94.504 138.144 95.753 143.736 ;
     RECT  94.637 95.088 95.825 101.592 ;
     RECT  95.749 52.56 95.843 58.68 ;
     RECT  95.749 80.928 95.843 86.664 ;
     RECT  95.825 95.088 95.861 101.064 ;
     RECT  95.861 95.088 95.891 100.824 ;
     RECT  95.393 38.112 95.933 43.224 ;
     RECT  95.843 52.56 95.933 58.44 ;
     RECT  95.843 81.264 95.933 86.664 ;
     RECT  95.891 95.088 95.933 95.112 ;
     RECT  95.753 138.384 95.933 143.736 ;
     RECT  95.933 52.56 96.227 58.248 ;
     RECT  96.227 52.56 96.275 57.72 ;
     RECT  95.933 81.36 96.275 86.664 ;
     RECT  95.933 139.104 96.275 143.256 ;
     RECT  96.275 52.56 96.323 57.624 ;
     RECT  96.275 139.104 96.323 143.112 ;
     RECT  95.933 38.736 98.196 38.76 ;
     RECT  95.933 38.76 98.22 38.88 ;
     RECT  95.933 38.88 98.196 38.904 ;
     RECT  95.933 38.904 98.22 39.024 ;
     RECT  95.933 39.024 98.196 39.048 ;
     RECT  95.933 39.048 98.22 39.168 ;
     RECT  95.933 39.168 98.196 39.192 ;
     RECT  95.933 39.192 98.22 39.312 ;
     RECT  95.933 39.312 98.196 39.336 ;
     RECT  95.933 39.336 98.22 39.456 ;
     RECT  95.933 39.456 98.196 39.48 ;
     RECT  95.933 39.48 98.22 39.6 ;
     RECT  95.933 39.6 98.196 39.624 ;
     RECT  95.933 39.624 98.22 39.744 ;
     RECT  95.933 39.744 98.196 39.768 ;
     RECT  95.933 39.768 98.22 39.888 ;
     RECT  95.933 39.888 98.196 39.912 ;
     RECT  95.933 39.912 98.22 40.032 ;
     RECT  95.933 40.032 98.196 40.056 ;
     RECT  95.933 40.056 98.22 40.176 ;
     RECT  95.933 40.176 98.196 40.2 ;
     RECT  95.933 40.2 98.22 40.32 ;
     RECT  95.933 40.32 98.196 40.344 ;
     RECT  95.933 40.344 98.22 40.464 ;
     RECT  95.933 40.464 98.196 40.488 ;
     RECT  95.933 40.488 98.22 40.608 ;
     RECT  95.933 40.608 98.196 40.632 ;
     RECT  95.933 40.632 98.22 40.752 ;
     RECT  95.933 40.752 98.196 40.776 ;
     RECT  95.933 40.776 98.22 40.896 ;
     RECT  95.933 40.896 98.196 40.92 ;
     RECT  95.933 40.92 98.22 41.04 ;
     RECT  95.933 41.04 98.196 41.064 ;
     RECT  95.933 41.064 98.22 41.184 ;
     RECT  95.933 41.184 98.196 41.208 ;
     RECT  95.933 41.208 98.22 41.328 ;
     RECT  95.933 41.328 98.196 41.352 ;
     RECT  95.933 41.352 98.22 41.472 ;
     RECT  95.933 41.472 98.196 41.496 ;
     RECT  95.933 41.496 98.22 41.616 ;
     RECT  95.933 41.616 98.196 41.64 ;
     RECT  95.933 41.64 98.22 41.76 ;
     RECT  95.933 41.76 98.196 41.784 ;
     RECT  95.933 41.784 98.22 41.904 ;
     RECT  95.933 41.904 98.196 41.928 ;
     RECT  95.933 41.928 98.22 42.048 ;
     RECT  95.933 42.048 98.196 42.072 ;
     RECT  95.933 42.072 98.22 42.192 ;
     RECT  95.933 42.192 98.196 42.216 ;
     RECT  95.933 42.216 98.22 42.336 ;
     RECT  95.933 42.336 98.196 42.36 ;
     RECT  95.933 42.36 98.22 42.48 ;
     RECT  95.933 42.48 98.196 42.504 ;
     RECT  95.933 42.504 98.22 42.624 ;
     RECT  95.933 42.624 98.196 42.648 ;
     RECT  95.933 42.648 98.22 42.768 ;
     RECT  95.933 42.768 98.196 42.792 ;
     RECT  95.933 42.792 98.22 42.912 ;
     RECT  95.933 42.912 98.196 42.936 ;
     RECT  95.933 42.936 98.22 43.056 ;
     RECT  95.933 43.056 98.196 43.08 ;
     RECT  95.933 43.08 98.22 43.2 ;
     RECT  95.933 43.2 98.196 43.224 ;
     RECT  96.323 52.56 98.196 52.584 ;
     RECT  96.323 52.584 98.22 52.704 ;
     RECT  96.323 52.704 98.196 52.728 ;
     RECT  96.323 52.728 98.22 52.848 ;
     RECT  96.323 52.848 98.196 52.872 ;
     RECT  96.323 52.872 98.22 52.992 ;
     RECT  96.323 52.992 98.196 53.016 ;
     RECT  96.323 53.016 98.22 53.136 ;
     RECT  96.323 53.136 98.196 53.16 ;
     RECT  96.323 53.16 98.22 53.28 ;
     RECT  96.323 53.28 98.196 53.304 ;
     RECT  96.323 53.304 98.22 53.424 ;
     RECT  96.323 53.424 98.196 53.448 ;
     RECT  96.323 53.448 98.22 53.568 ;
     RECT  96.323 53.568 98.196 53.592 ;
     RECT  96.323 53.592 98.22 53.712 ;
     RECT  96.323 53.712 98.196 53.736 ;
     RECT  96.323 53.736 98.22 53.856 ;
     RECT  96.323 53.856 98.196 53.88 ;
     RECT  96.323 53.88 98.22 54 ;
     RECT  96.323 54 98.196 54.024 ;
     RECT  96.323 54.024 98.22 54.144 ;
     RECT  96.323 54.144 98.196 54.168 ;
     RECT  96.323 54.168 98.22 54.288 ;
     RECT  96.323 54.288 98.196 54.312 ;
     RECT  96.323 54.312 98.22 54.432 ;
     RECT  96.323 54.432 98.196 54.456 ;
     RECT  96.323 54.456 98.22 54.576 ;
     RECT  96.323 54.576 98.196 54.6 ;
     RECT  96.323 54.6 98.22 54.72 ;
     RECT  96.323 54.72 98.196 54.744 ;
     RECT  96.323 54.744 98.22 54.864 ;
     RECT  96.323 54.864 98.196 54.888 ;
     RECT  96.323 54.888 98.22 55.008 ;
     RECT  96.323 55.008 98.196 55.032 ;
     RECT  96.323 55.032 98.22 55.152 ;
     RECT  96.323 55.152 98.196 55.176 ;
     RECT  96.323 55.176 98.22 55.296 ;
     RECT  96.323 55.296 98.196 55.32 ;
     RECT  96.323 55.32 98.22 55.44 ;
     RECT  96.323 55.44 98.196 55.464 ;
     RECT  96.323 55.464 98.22 55.584 ;
     RECT  96.323 55.584 98.196 55.608 ;
     RECT  96.323 55.608 98.22 55.728 ;
     RECT  96.323 55.728 98.196 55.752 ;
     RECT  96.323 55.752 98.22 55.872 ;
     RECT  96.323 55.872 98.196 55.896 ;
     RECT  96.323 55.896 98.22 56.016 ;
     RECT  96.323 56.016 98.196 56.04 ;
     RECT  96.323 56.04 98.22 56.16 ;
     RECT  96.323 56.16 98.196 56.184 ;
     RECT  96.323 56.184 98.22 56.304 ;
     RECT  96.323 56.304 98.196 56.328 ;
     RECT  96.323 56.328 98.22 56.448 ;
     RECT  96.323 56.448 98.196 56.472 ;
     RECT  96.323 56.472 98.22 56.592 ;
     RECT  96.323 56.592 98.196 56.616 ;
     RECT  96.323 56.616 98.22 56.736 ;
     RECT  96.323 56.736 98.196 56.76 ;
     RECT  96.323 56.76 98.22 56.88 ;
     RECT  96.323 56.88 98.196 56.904 ;
     RECT  96.323 56.904 98.22 57.024 ;
     RECT  96.323 57.024 98.196 57.048 ;
     RECT  96.275 81.36 98.196 81.384 ;
     RECT  96.275 81.384 98.22 81.504 ;
     RECT  96.275 81.504 98.196 81.528 ;
     RECT  96.275 81.528 98.22 81.648 ;
     RECT  96.275 81.648 98.196 81.672 ;
     RECT  96.275 81.672 98.22 81.792 ;
     RECT  96.275 81.792 98.196 81.816 ;
     RECT  96.275 81.816 98.22 81.936 ;
     RECT  96.275 81.936 98.196 81.96 ;
     RECT  96.275 81.96 98.22 82.08 ;
     RECT  96.275 82.08 98.196 82.104 ;
     RECT  96.275 82.104 98.22 82.224 ;
     RECT  96.275 82.224 98.196 82.248 ;
     RECT  96.275 82.248 98.22 82.368 ;
     RECT  96.275 82.368 98.196 82.392 ;
     RECT  96.275 82.392 98.22 82.512 ;
     RECT  96.275 82.512 98.196 82.536 ;
     RECT  96.275 82.536 98.22 82.656 ;
     RECT  96.275 82.656 98.196 82.68 ;
     RECT  96.275 82.68 98.22 82.8 ;
     RECT  96.275 82.8 98.196 82.824 ;
     RECT  96.275 82.824 98.22 82.944 ;
     RECT  96.275 82.944 98.196 82.968 ;
     RECT  96.275 82.968 98.22 83.088 ;
     RECT  96.275 83.088 98.196 83.112 ;
     RECT  96.275 83.112 98.22 83.232 ;
     RECT  96.275 83.232 98.196 83.256 ;
     RECT  96.275 83.256 98.22 83.376 ;
     RECT  96.275 83.376 98.196 83.4 ;
     RECT  96.275 83.4 98.22 83.52 ;
     RECT  96.275 83.52 98.196 83.544 ;
     RECT  96.275 83.544 98.22 83.664 ;
     RECT  96.275 83.664 98.196 83.688 ;
     RECT  96.275 83.688 98.22 83.808 ;
     RECT  96.275 83.808 98.196 83.832 ;
     RECT  96.275 83.832 98.22 83.952 ;
     RECT  96.275 83.952 98.196 83.976 ;
     RECT  96.275 83.976 98.22 84.096 ;
     RECT  96.275 84.096 98.196 84.12 ;
     RECT  96.275 84.12 98.22 84.24 ;
     RECT  96.275 84.24 98.196 84.264 ;
     RECT  96.275 84.264 98.22 84.384 ;
     RECT  96.275 84.384 98.196 84.408 ;
     RECT  96.275 84.408 98.22 84.528 ;
     RECT  96.275 84.528 98.196 84.552 ;
     RECT  96.275 84.552 98.22 84.672 ;
     RECT  96.275 84.672 98.196 84.696 ;
     RECT  96.275 84.696 98.22 84.816 ;
     RECT  96.275 84.816 98.196 84.84 ;
     RECT  96.275 84.84 98.22 84.96 ;
     RECT  96.275 84.96 98.196 84.984 ;
     RECT  96.275 84.984 98.22 85.104 ;
     RECT  96.275 85.104 98.196 85.128 ;
     RECT  96.275 85.128 98.22 85.248 ;
     RECT  96.275 85.248 98.196 85.272 ;
     RECT  96.275 85.272 98.22 85.392 ;
     RECT  96.275 85.392 98.196 85.416 ;
     RECT  96.275 85.416 98.22 85.536 ;
     RECT  96.275 85.536 98.196 85.56 ;
     RECT  96.275 85.56 98.22 85.68 ;
     RECT  96.275 85.68 98.196 85.704 ;
     RECT  96.275 85.704 98.22 85.824 ;
     RECT  96.275 85.824 98.196 85.848 ;
     RECT  95.891 96.336 98.196 96.36 ;
     RECT  95.891 96.36 98.22 96.48 ;
     RECT  95.891 96.48 98.196 96.504 ;
     RECT  95.891 96.504 98.22 96.624 ;
     RECT  95.891 96.624 98.196 96.648 ;
     RECT  95.891 96.648 98.22 96.768 ;
     RECT  95.891 96.768 98.196 96.792 ;
     RECT  95.891 96.792 98.22 96.912 ;
     RECT  95.891 96.912 98.196 96.936 ;
     RECT  95.891 96.936 98.22 97.056 ;
     RECT  95.891 97.056 98.196 97.08 ;
     RECT  95.891 97.08 98.22 97.2 ;
     RECT  95.891 97.2 98.196 97.224 ;
     RECT  95.891 97.224 98.22 97.344 ;
     RECT  95.891 97.344 98.196 97.368 ;
     RECT  95.891 97.368 98.22 97.488 ;
     RECT  95.891 97.488 98.196 97.512 ;
     RECT  95.891 97.512 98.22 97.632 ;
     RECT  95.891 97.632 98.196 97.656 ;
     RECT  95.891 97.656 98.22 97.776 ;
     RECT  95.891 97.776 98.196 97.8 ;
     RECT  95.891 97.8 98.22 97.92 ;
     RECT  95.891 97.92 98.196 97.944 ;
     RECT  95.891 97.944 98.22 98.064 ;
     RECT  95.891 98.064 98.196 98.088 ;
     RECT  95.891 98.088 98.22 98.208 ;
     RECT  95.891 98.208 98.196 98.232 ;
     RECT  95.891 98.232 98.22 98.352 ;
     RECT  95.891 98.352 98.196 98.376 ;
     RECT  95.891 98.376 98.22 98.496 ;
     RECT  95.891 98.496 98.196 98.52 ;
     RECT  95.891 98.52 98.22 98.64 ;
     RECT  95.891 98.64 98.196 98.664 ;
     RECT  95.891 98.664 98.22 98.784 ;
     RECT  95.891 98.784 98.196 98.808 ;
     RECT  95.891 98.808 98.22 98.928 ;
     RECT  95.891 98.928 98.196 98.952 ;
     RECT  95.891 98.952 98.22 99.072 ;
     RECT  95.891 99.072 98.196 99.096 ;
     RECT  95.891 99.096 98.22 99.216 ;
     RECT  95.891 99.216 98.196 99.24 ;
     RECT  95.891 99.24 98.22 99.36 ;
     RECT  95.891 99.36 98.196 99.384 ;
     RECT  95.891 99.384 98.22 99.504 ;
     RECT  95.891 99.504 98.196 99.528 ;
     RECT  95.891 99.528 98.22 99.648 ;
     RECT  95.891 99.648 98.196 99.672 ;
     RECT  95.891 99.672 98.22 99.792 ;
     RECT  95.891 99.792 98.196 99.816 ;
     RECT  95.891 99.816 98.22 99.936 ;
     RECT  95.891 99.936 98.196 99.96 ;
     RECT  95.891 99.96 98.22 100.08 ;
     RECT  95.891 100.08 98.196 100.104 ;
     RECT  95.891 100.104 98.22 100.224 ;
     RECT  95.891 100.224 98.196 100.248 ;
     RECT  95.891 100.248 98.22 100.368 ;
     RECT  95.891 100.368 98.196 100.392 ;
     RECT  95.891 100.392 98.22 100.512 ;
     RECT  95.891 100.512 98.196 100.536 ;
     RECT  95.891 100.536 98.22 100.656 ;
     RECT  95.891 100.656 98.196 100.68 ;
     RECT  95.891 100.68 98.22 100.8 ;
     RECT  95.891 100.8 98.196 100.824 ;
     RECT  96.323 139.104 98.196 139.128 ;
     RECT  96.323 139.128 98.22 139.248 ;
     RECT  96.323 139.248 98.196 139.272 ;
     RECT  96.323 139.272 98.22 139.392 ;
     RECT  96.323 139.392 98.196 139.416 ;
     RECT  96.323 139.416 98.22 139.536 ;
     RECT  96.323 139.536 98.196 139.56 ;
     RECT  96.323 139.56 98.22 139.68 ;
     RECT  96.323 139.68 98.196 139.704 ;
     RECT  96.323 139.704 98.22 139.824 ;
     RECT  96.323 139.824 98.196 139.848 ;
     RECT  96.323 139.848 98.22 139.968 ;
     RECT  96.323 139.968 98.196 139.992 ;
     RECT  96.323 139.992 98.22 140.112 ;
     RECT  96.323 140.112 98.196 140.136 ;
     RECT  96.323 140.136 98.22 140.256 ;
     RECT  96.323 140.256 98.196 140.28 ;
     RECT  96.323 140.28 98.22 140.4 ;
     RECT  96.323 140.4 98.196 140.424 ;
     RECT  96.323 140.424 98.22 140.544 ;
     RECT  96.323 140.544 98.196 140.568 ;
     RECT  96.323 140.568 98.22 140.688 ;
     RECT  96.323 140.688 98.196 140.712 ;
     RECT  96.323 140.712 98.22 140.832 ;
     RECT  96.323 140.832 98.196 140.856 ;
     RECT  96.323 140.856 98.22 140.976 ;
     RECT  96.323 140.976 98.196 141 ;
     RECT  96.323 141 98.22 141.12 ;
     RECT  96.323 141.12 98.196 141.144 ;
     RECT  96.323 141.144 98.22 141.264 ;
     RECT  96.323 141.264 98.196 141.288 ;
     RECT  96.323 141.288 98.22 141.408 ;
     RECT  96.323 141.408 98.196 141.432 ;
     RECT  96.323 141.432 98.22 141.552 ;
     RECT  96.323 141.552 98.196 141.576 ;
     RECT  96.323 141.576 98.22 141.696 ;
     RECT  96.323 141.696 98.196 141.72 ;
     RECT  96.323 141.72 98.22 141.84 ;
     RECT  96.323 141.84 98.196 141.864 ;
     RECT  96.323 141.864 98.22 141.984 ;
     RECT  96.323 141.984 98.196 142.008 ;
     RECT  96.323 142.008 98.22 142.128 ;
     RECT  96.323 142.128 98.196 142.152 ;
     RECT  96.323 142.152 98.22 142.272 ;
     RECT  96.323 142.272 98.196 142.296 ;
     RECT  98.22 53.616 98.273 53.64 ;
    LAYER M5 ;
     RECT  2.4 2.137 2.52 2.151 ;
     RECT  5.1 2.137 5.22 2.151 ;
     RECT  7.8 2.137 7.92 2.151 ;
     RECT  10.5 2.137 10.62 2.151 ;
     RECT  13.2 2.137 13.32 2.151 ;
     RECT  15.9 2.137 16.02 2.151 ;
     RECT  18.6 2.137 18.72 2.151 ;
     RECT  21.3 2.137 21.42 2.151 ;
     RECT  24 2.137 24.12 2.151 ;
     RECT  26.7 2.137 26.82 2.151 ;
     RECT  29.4 2.137 29.52 2.151 ;
     RECT  32.1 2.137 32.22 2.151 ;
     RECT  34.8 2.137 34.92 2.151 ;
     RECT  37.5 2.137 37.62 2.151 ;
     RECT  40.2 2.137 40.32 2.151 ;
     RECT  42.9 2.137 43.02 2.151 ;
     RECT  45.6 2.137 45.72 2.151 ;
     RECT  48.3 2.137 48.42 2.151 ;
     RECT  51 2.137 51.12 2.151 ;
     RECT  53.7 2.137 53.82 2.151 ;
     RECT  56.4 2.137 56.52 2.151 ;
     RECT  59.1 2.137 59.22 2.151 ;
     RECT  61.8 2.137 61.92 2.151 ;
     RECT  64.5 2.137 64.62 2.151 ;
     RECT  67.2 2.137 67.32 2.151 ;
     RECT  69.9 2.137 70.02 2.151 ;
     RECT  72.6 2.137 72.72 2.151 ;
     RECT  75.3 2.137 75.42 2.151 ;
     RECT  78 2.137 78.12 2.151 ;
     RECT  80.7 2.137 80.82 2.151 ;
     RECT  83.4 2.137 83.52 2.151 ;
     RECT  86.1 2.137 86.22 2.151 ;
     RECT  88.8 2.137 88.92 2.151 ;
     RECT  91.5 2.137 91.62 2.151 ;
     RECT  94.2 2.137 94.32 2.151 ;
     RECT  2.4 2.151 2.712 31.717 ;
     RECT  2.304 31.717 2.712 31.859 ;
     RECT  2.4 31.859 2.712 31.861 ;
     RECT  7.8 2.151 8.112 34.741 ;
     RECT  7.8 34.741 8.232 35.269 ;
     RECT  6.864 35.269 8.232 35.363 ;
     RECT  6.864 35.363 8.112 36.179 ;
     RECT  2.4 31.861 3.336 36.227 ;
     RECT  7.104 36.179 8.112 36.421 ;
     RECT  5.1 2.151 5.412 36.709 ;
     RECT  4.512 36.709 5.412 37.573 ;
     RECT  7.104 36.421 8.472 37.573 ;
     RECT  91.5 2.151 91.812 37.957 ;
     RECT  94.2 2.151 94.512 38.101 ;
     RECT  94.2 38.101 95.16 38.149 ;
     RECT  94.2 38.149 95.784 38.533 ;
     RECT  91.5 37.957 92.328 38.819 ;
     RECT  90.24 38.389 90.264 39.301 ;
     RECT  91.5 38.819 91.812 39.301 ;
     RECT  94.2 38.533 95.832 39.491 ;
     RECT  95.808 39.491 95.832 39.635 ;
     RECT  90.24 39.301 91.812 39.923 ;
     RECT  4.512 37.573 8.472 40.307 ;
     RECT  4.512 40.307 5.736 40.403 ;
     RECT  13.2 2.151 13.512 40.405 ;
     RECT  40.2 2.151 40.512 40.549 ;
     RECT  12.24 40.405 13.512 40.597 ;
     RECT  12.24 40.597 14.232 40.739 ;
     RECT  64.5 2.151 64.812 40.741 ;
     RECT  39.84 40.549 40.512 40.837 ;
     RECT  90.528 39.923 91.812 40.981 ;
     RECT  7.104 40.307 8.472 41.123 ;
     RECT  75.3 2.151 75.612 41.125 ;
     RECT  94.2 39.491 94.68 41.267 ;
     RECT  4.512 40.403 5.412 41.605 ;
     RECT  7.104 41.123 8.112 41.651 ;
     RECT  95.712 40.885 95.736 41.651 ;
     RECT  3.984 41.605 5.412 41.891 ;
     RECT  7.8 41.651 8.112 42.133 ;
     RECT  90.528 40.981 92.376 42.179 ;
     RECT  88.8 2.151 89.112 42.181 ;
     RECT  5.1 41.891 5.412 42.709 ;
     RECT  3.984 41.891 4.008 42.995 ;
     RECT  94.2 41.267 94.512 43.189 ;
     RECT  94.2 43.189 95.16 43.429 ;
     RECT  7.8 42.133 8.28 43.571 ;
     RECT  93.744 43.429 95.16 43.955 ;
     RECT  42.9 2.151 43.212 43.957 ;
     RECT  5.1 42.709 5.928 44.051 ;
     RECT  82.176 44.101 82.2 44.387 ;
     RECT  42.672 43.957 43.212 44.437 ;
     RECT  0.144 44.437 0.168 44.675 ;
     RECT  7.8 43.571 8.112 44.965 ;
     RECT  7.8 44.965 8.232 45.731 ;
     RECT  78 2.151 78.312 46.789 ;
     RECT  79.488 40.885 79.512 46.789 ;
     RECT  78 46.789 79.512 47.363 ;
     RECT  80.7 2.151 81.012 47.413 ;
     RECT  78 47.363 78.696 47.699 ;
     RECT  80.7 47.413 81.624 47.699 ;
     RECT  93.744 43.955 94.512 47.845 ;
     RECT  75.3 41.125 75.72 48.323 ;
     RECT  39.744 40.837 40.512 50.003 ;
     RECT  39.84 50.003 40.512 51.923 ;
     RECT  93.6 47.845 94.512 52.691 ;
     RECT  40.2 51.923 40.512 52.885 ;
     RECT  88.8 42.181 89.208 53.267 ;
     RECT  94.032 52.691 94.512 54.325 ;
     RECT  94.032 54.325 94.632 55.189 ;
     RECT  95.76 53.941 95.784 55.189 ;
     RECT  90.528 42.179 91.812 55.283 ;
     RECT  94.032 55.189 95.784 55.525 ;
     RECT  94.032 55.525 95.832 55.907 ;
     RECT  88.8 53.267 89.112 56.389 ;
     RECT  95.664 55.907 95.832 56.581 ;
     RECT  88.8 56.389 89.448 56.917 ;
     RECT  91.5 55.283 91.812 56.917 ;
     RECT  94.032 55.907 94.512 56.917 ;
     RECT  95.664 56.581 96.312 56.917 ;
     RECT  93.936 56.917 96.312 57.635 ;
     RECT  88.8 56.917 90.312 57.683 ;
     RECT  93.936 57.635 96.264 57.731 ;
     RECT  93.936 57.731 96.216 57.875 ;
     RECT  94.032 57.875 96.216 58.259 ;
     RECT  94.032 58.259 95.832 58.451 ;
     RECT  95.808 58.451 95.832 58.691 ;
     RECT  40.2 52.885 40.92 60.659 ;
     RECT  40.2 60.659 40.824 61.091 ;
     RECT  42.144 44.437 43.212 64.741 ;
     RECT  45.6 2.151 45.912 64.933 ;
     RECT  94.032 58.451 94.512 65.557 ;
     RECT  64.5 40.741 65.256 65.701 ;
     RECT  78 47.699 78.312 66.085 ;
     RECT  78 66.085 79.032 67.859 ;
     RECT  78 67.859 78.648 70.163 ;
     RECT  78 70.163 78.312 70.645 ;
     RECT  77.472 70.645 78.312 73.235 ;
     RECT  91.5 56.917 92.04 73.237 ;
     RECT  75.3 48.323 75.612 73.285 ;
     RECT  88.8 57.683 89.112 74.053 ;
     RECT  91.5 73.237 92.28 74.293 ;
     RECT  24 2.151 24.312 75.445 ;
     RECT  88.608 74.053 89.112 77.509 ;
     RECT  90.288 57.683 90.312 77.509 ;
     RECT  88.608 77.509 90.312 77.555 ;
     RECT  88.608 77.555 90.072 77.699 ;
     RECT  83.4 2.151 83.712 77.941 ;
     RECT  93.936 65.557 94.512 78.179 ;
     RECT  64.5 65.701 65.688 78.613 ;
     RECT  67.2 2.151 67.512 78.613 ;
     RECT  2.4 36.227 2.712 79.141 ;
     RECT  64.5 78.613 67.512 79.283 ;
     RECT  2.4 79.141 3.432 80.003 ;
     RECT  2.4 80.003 2.712 80.197 ;
     RECT  2.208 80.197 2.712 80.339 ;
     RECT  94.032 78.179 94.512 80.917 ;
     RECT  91.5 74.293 92.712 81.685 ;
     RECT  91.5 81.685 93.048 81.877 ;
     RECT  94.032 80.917 95.832 81.877 ;
     RECT  5.1 44.051 5.412 82.021 ;
     RECT  91.5 81.877 95.832 82.067 ;
     RECT  91.5 82.067 92.712 82.115 ;
     RECT  5.1 82.021 5.544 82.597 ;
     RECT  64.5 79.283 65.544 82.691 ;
     RECT  93.984 82.067 95.832 82.691 ;
     RECT  88.8 77.699 90.072 82.741 ;
     RECT  91.5 82.115 92.28 82.741 ;
     RECT  37.5 2.151 37.812 83.029 ;
     RECT  39.168 54.085 39.192 83.029 ;
     RECT  42.144 64.741 43.32 83.221 ;
     RECT  5.1 82.597 6.36 83.461 ;
     RECT  64.5 82.691 65.256 83.701 ;
     RECT  69.9 2.151 70.212 83.701 ;
     RECT  7.8 45.731 8.112 83.749 ;
     RECT  37.5 83.029 39.192 83.749 ;
     RECT  40.2 61.091 40.512 83.749 ;
     RECT  42.096 83.221 43.32 83.749 ;
     RECT  48.3 2.151 48.612 83.749 ;
     RECT  75.3 73.285 76.248 83.843 ;
     RECT  94.032 82.691 95.112 83.941 ;
     RECT  66.624 79.283 67.512 84.083 ;
     RECT  69.9 83.701 70.68 84.083 ;
     RECT  48.3 83.749 48.84 84.131 ;
     RECT  82.896 77.941 83.712 84.131 ;
     RECT  12.24 40.739 13.512 84.323 ;
     RECT  41.76 83.749 43.32 84.371 ;
     RECT  94.032 83.941 95.736 84.467 ;
     RECT  88.8 82.741 92.28 84.611 ;
     RECT  91.344 84.611 92.28 84.757 ;
     RECT  4.368 83.461 6.36 84.851 ;
     RECT  95.712 84.467 95.736 84.949 ;
     RECT  5.1 84.851 6.36 85.379 ;
     RECT  7.8 83.749 8.52 85.523 ;
     RECT  95.712 84.949 96.312 85.523 ;
     RECT  96.24 85.523 96.312 85.571 ;
     RECT  37.5 83.749 40.512 86.005 ;
     RECT  91.344 84.757 92.664 86.053 ;
     RECT  91.296 86.053 92.664 86.341 ;
     RECT  94.032 84.467 94.512 86.341 ;
     RECT  91.296 86.341 94.512 86.387 ;
     RECT  7.8 85.523 8.112 86.581 ;
     RECT  91.296 86.387 92.136 86.581 ;
     RECT  96.24 85.571 96.264 86.675 ;
     RECT  5.1 85.379 5.736 87.251 ;
     RECT  7.8 86.581 8.232 87.251 ;
     RECT  90.912 86.581 92.136 87.827 ;
     RECT  2.4 80.339 2.712 87.973 ;
     RECT  2.304 87.973 2.712 88.115 ;
     RECT  7.8 87.251 8.112 88.357 ;
     RECT  90.912 87.827 91.812 88.403 ;
     RECT  6.816 88.357 8.112 89.027 ;
     RECT  91.152 88.403 91.812 89.027 ;
     RECT  21.3 2.151 21.612 94.021 ;
     RECT  37.5 86.005 40.632 94.115 ;
     RECT  95.808 95.125 95.832 95.653 ;
     RECT  88.8 84.611 89.736 95.893 ;
     RECT  91.296 89.027 91.812 95.893 ;
     RECT  95.52 95.653 95.832 96.037 ;
     RECT  37.5 94.115 40.512 96.371 ;
     RECT  95.52 96.037 95.88 96.659 ;
     RECT  93.504 86.387 94.512 96.755 ;
     RECT  88.8 95.893 91.812 96.947 ;
     RECT  95.52 96.659 95.784 97.235 ;
     RECT  88.8 96.947 89.736 97.283 ;
     RECT  95.52 97.235 95.736 97.523 ;
     RECT  94.08 96.755 94.512 97.571 ;
     RECT  91.152 96.947 91.812 98.099 ;
     RECT  94.2 97.571 94.512 98.533 ;
     RECT  95.712 97.523 95.736 98.581 ;
     RECT  92.88 97.813 92.904 98.675 ;
     RECT  91.296 98.099 91.812 98.915 ;
     RECT  94.2 98.533 94.632 99.157 ;
     RECT  94.08 99.157 94.632 99.589 ;
     RECT  95.664 98.581 95.736 99.589 ;
     RECT  21.3 94.021 22.488 99.683 ;
     RECT  88.8 97.283 89.112 100.261 ;
     RECT  90.288 99.685 90.312 100.837 ;
     RECT  91.5 98.915 91.812 100.837 ;
     RECT  94.08 99.589 95.736 100.931 ;
     RECT  94.08 100.931 95.64 100.979 ;
     RECT  94.08 100.979 95.592 101.123 ;
     RECT  94.2 101.123 95.592 101.171 ;
     RECT  94.2 101.171 95.112 101.219 ;
     RECT  90.288 100.837 91.812 101.699 ;
     RECT  40.08 96.371 40.512 103.093 ;
     RECT  41.76 84.371 43.212 103.093 ;
     RECT  40.08 103.093 43.212 103.811 ;
     RECT  75.3 83.843 75.612 103.813 ;
     RECT  64.5 83.701 65.352 105.491 ;
     RECT  75.168 103.813 75.612 105.779 ;
     RECT  88.704 100.261 89.112 105.779 ;
     RECT  86.1 2.151 86.412 105.973 ;
     RECT  44.784 64.933 45.912 107.843 ;
     RECT  64.5 105.491 65.112 108.277 ;
     RECT  41.76 103.811 43.212 108.517 ;
     RECT  37.5 96.371 38.472 109.381 ;
     RECT  90.288 101.699 90.312 111.443 ;
     RECT  83.4 84.131 83.712 111.829 ;
     RECT  37.5 109.381 39.048 113.941 ;
     RECT  41.76 108.517 43.32 114.035 ;
     RECT  34.8 2.151 35.112 114.517 ;
     RECT  40.08 103.811 40.512 114.517 ;
     RECT  83.28 111.829 83.712 115.093 ;
     RECT  85.2 105.973 86.412 115.093 ;
     RECT  34.8 114.517 35.928 115.139 ;
     RECT  23.856 75.445 24.312 115.187 ;
     RECT  37.392 113.941 39.048 115.333 ;
     RECT  40.08 114.517 41.016 115.333 ;
     RECT  5.1 87.251 5.412 115.621 ;
     RECT  37.392 115.333 41.016 116.435 ;
     RECT  34.8 115.139 35.112 116.821 ;
     RECT  34.8 116.821 35.976 117.397 ;
     RECT  34.8 117.397 36.456 118.355 ;
     RECT  34.8 118.355 36.264 119.699 ;
     RECT  64.5 108.277 65.448 120.899 ;
     RECT  83.28 115.093 86.412 120.899 ;
     RECT  56.4 2.151 56.712 121.093 ;
     RECT  75.3 105.779 75.612 121.093 ;
     RECT  64.5 120.899 65.016 121.139 ;
     RECT  83.28 120.899 84.072 121.139 ;
     RECT  55.824 121.093 56.712 121.333 ;
     RECT  75.168 121.093 75.612 121.381 ;
     RECT  34.8 119.699 36.072 121.475 ;
     RECT  78 73.235 78.312 121.669 ;
     RECT  85.296 120.899 86.412 121.715 ;
     RECT  77.712 121.669 78.312 122.099 ;
     RECT  74.688 121.381 75.612 122.149 ;
     RECT  74.544 122.149 75.612 122.245 ;
     RECT  37.5 116.435 41.016 122.579 ;
     RECT  45.6 107.843 45.912 122.821 ;
     RECT  37.5 122.579 40.92 123.637 ;
     RECT  5.1 115.621 5.592 123.731 ;
     RECT  73.92 122.245 75.612 123.971 ;
     RECT  72.6 2.151 72.912 124.069 ;
     RECT  55.728 121.333 56.712 124.789 ;
     RECT  37.392 123.637 41.064 124.883 ;
     RECT  37.5 124.883 41.064 125.317 ;
     RECT  42.144 114.035 43.32 125.317 ;
     RECT  37.5 125.317 43.32 125.459 ;
     RECT  72.24 124.069 72.912 125.891 ;
     RECT  34.8 121.475 35.544 126.035 ;
     RECT  73.92 123.971 73.944 126.035 ;
     RECT  37.5 125.459 41.592 126.179 ;
     RECT  75.3 123.971 75.612 126.229 ;
     RECT  55.152 124.789 56.712 126.563 ;
     RECT  36.432 126.421 36.456 126.757 ;
     RECT  37.5 126.179 41.016 126.757 ;
     RECT  42.624 125.459 43.32 127.045 ;
     RECT  75.3 126.229 75.72 127.045 ;
     RECT  45.6 122.821 46.536 127.139 ;
     RECT  42.576 127.045 43.32 127.237 ;
     RECT  55.152 126.563 55.176 127.283 ;
     RECT  42.576 127.237 43.704 127.379 ;
     RECT  36.432 126.757 41.016 127.715 ;
     RECT  75.3 127.045 76.056 128.867 ;
     RECT  37.248 127.715 41.016 129.253 ;
     RECT  34.8 126.035 35.112 129.349 ;
     RECT  42.576 127.379 43.32 129.491 ;
     RECT  78 122.099 78.312 130.501 ;
     RECT  34.8 129.349 35.976 130.595 ;
     RECT  77.76 130.501 78.312 131.123 ;
     RECT  42.576 129.491 43.212 131.459 ;
     RECT  42.624 131.459 43.212 131.747 ;
     RECT  78 131.123 78.312 133.333 ;
     RECT  80.7 47.699 81.012 134.149 ;
     RECT  37.152 129.253 41.016 134.387 ;
     RECT  75.3 128.867 75.816 134.627 ;
     RECT  37.392 134.387 41.016 135.155 ;
     RECT  80.112 134.149 81.012 136.307 ;
     RECT  88.8 105.779 89.112 136.405 ;
     RECT  91.5 101.699 91.812 136.453 ;
     RECT  78 133.333 78.408 136.691 ;
     RECT  83.4 121.139 84.072 136.787 ;
     RECT  94.2 101.219 94.512 138.373 ;
     RECT  95.712 138.325 95.736 138.421 ;
     RECT  94.032 138.373 94.512 138.565 ;
     RECT  90.576 136.453 91.812 138.757 ;
     RECT  90.48 138.757 91.812 138.803 ;
     RECT  95.712 138.421 95.784 138.949 ;
     RECT  92.88 138.133 92.904 139.285 ;
     RECT  93.984 138.565 94.512 139.285 ;
     RECT  95.52 138.949 95.832 139.285 ;
     RECT  92.88 139.285 95.832 139.525 ;
     RECT  92.832 139.525 95.832 139.571 ;
     RECT  88.8 136.405 89.256 139.667 ;
     RECT  90.48 138.803 90.504 139.715 ;
     RECT  92.832 139.571 95.544 139.859 ;
     RECT  92.832 139.859 95.448 140.243 ;
     RECT  94.08 140.243 95.448 140.819 ;
     RECT  88.8 139.667 89.208 141.301 ;
     RECT  92.832 140.243 92.856 141.301 ;
     RECT  94.2 140.819 95.448 141.829 ;
     RECT  92.832 141.301 92.952 141.923 ;
     RECT  94.2 141.829 95.784 141.973 ;
     RECT  92.928 141.923 92.952 142.019 ;
     RECT  37.5 135.155 41.016 142.547 ;
     RECT  21.3 99.683 22.344 142.931 ;
     RECT  94.2 141.973 96.312 143.123 ;
     RECT  88.8 141.301 89.496 143.267 ;
     RECT  94.2 143.123 96.264 143.267 ;
     RECT  94.2 143.267 95.784 143.699 ;
     RECT  94.2 143.699 95.064 143.747 ;
     RECT  37.5 142.547 40.512 149.939 ;
     RECT  37.5 149.939 38.76 150.515 ;
     RECT  37.5 150.515 38.664 153.155 ;
     RECT  37.5 153.155 38.616 157.475 ;
     RECT  37.5 157.475 38.472 163.909 ;
     RECT  37.5 163.909 38.616 165.875 ;
     RECT  37.5 165.875 38.472 165.923 ;
     RECT  2.4 88.115 2.712 168.489 ;
     RECT  5.1 123.731 5.412 168.489 ;
     RECT  7.8 89.027 8.112 168.489 ;
     RECT  10.5 2.151 10.812 168.489 ;
     RECT  13.2 84.323 13.512 168.489 ;
     RECT  15.9 2.151 16.212 168.489 ;
     RECT  18.6 2.151 18.912 168.489 ;
     RECT  21.3 142.931 21.612 168.489 ;
     RECT  24 115.187 24.312 168.489 ;
     RECT  26.7 2.151 27.012 168.489 ;
     RECT  29.4 2.151 29.712 168.489 ;
     RECT  32.1 2.151 32.412 168.489 ;
     RECT  34.8 130.595 35.112 168.489 ;
     RECT  40.2 149.939 40.512 168.489 ;
     RECT  42.9 131.747 43.212 168.489 ;
     RECT  45.6 127.139 45.912 168.489 ;
     RECT  48.3 84.131 48.612 168.489 ;
     RECT  51 2.151 51.312 168.489 ;
     RECT  53.7 2.151 54.012 168.489 ;
     RECT  56.4 126.563 56.712 168.489 ;
     RECT  59.1 2.151 59.412 168.489 ;
     RECT  61.8 2.151 62.112 168.489 ;
     RECT  64.5 121.139 64.812 168.489 ;
     RECT  67.2 84.083 67.512 168.489 ;
     RECT  69.9 84.083 70.212 168.489 ;
     RECT  72.6 125.891 72.912 168.489 ;
     RECT  75.3 134.627 75.612 168.489 ;
     RECT  78 136.691 78.312 168.489 ;
     RECT  80.7 136.307 81.012 168.489 ;
     RECT  83.4 136.787 83.712 168.489 ;
     RECT  86.1 121.715 86.412 168.489 ;
     RECT  88.8 143.267 89.112 168.489 ;
     RECT  91.5 138.803 91.812 168.489 ;
     RECT  94.2 143.747 94.512 168.489 ;
     RECT  2.4 168.489 2.52 168.503 ;
     RECT  5.1 168.489 5.22 168.503 ;
     RECT  7.8 168.489 7.92 168.503 ;
     RECT  10.5 168.489 10.62 168.503 ;
     RECT  13.2 168.489 13.32 168.503 ;
     RECT  15.9 168.489 16.02 168.503 ;
     RECT  18.6 168.489 18.72 168.503 ;
     RECT  21.3 168.489 21.42 168.503 ;
     RECT  24 168.489 24.12 168.503 ;
     RECT  26.7 168.489 26.82 168.503 ;
     RECT  29.4 168.489 29.52 168.503 ;
     RECT  32.1 168.489 32.22 168.503 ;
     RECT  34.8 168.489 34.92 168.503 ;
     RECT  37.5 165.923 38.136 168.503 ;
     RECT  40.2 168.489 40.32 168.503 ;
     RECT  42.9 168.489 43.02 168.503 ;
     RECT  45.6 168.489 45.72 168.503 ;
     RECT  48.3 168.489 48.42 168.503 ;
     RECT  51 168.489 51.12 168.503 ;
     RECT  53.7 168.489 53.82 168.503 ;
     RECT  56.4 168.489 56.52 168.503 ;
     RECT  59.1 168.489 59.22 168.503 ;
     RECT  61.8 168.489 61.92 168.503 ;
     RECT  64.5 168.489 64.62 168.503 ;
     RECT  67.2 168.489 67.32 168.503 ;
     RECT  69.9 168.489 70.02 168.503 ;
     RECT  72.6 168.489 72.72 168.503 ;
     RECT  75.3 168.489 75.42 168.503 ;
     RECT  78 168.489 78.12 168.503 ;
     RECT  80.7 168.489 80.82 168.503 ;
     RECT  83.4 168.489 83.52 168.503 ;
     RECT  86.1 168.489 86.22 168.503 ;
     RECT  88.8 168.489 88.92 168.503 ;
     RECT  91.5 168.489 91.62 168.503 ;
     RECT  94.2 168.489 94.32 168.503 ;
     RECT  37.968 168.503 38.136 170.435 ;
     RECT  37.968 170.435 37.992 170.531 ;
     RECT  5.412 35.269 6.864 36.179 ;
     RECT  8.112 35.363 8.232 36.421 ;
     RECT  5.412 36.179 7.104 37.573 ;
     RECT  89.112 38.389 90.24 39.923 ;
     RECT  90.264 38.389 91.5 39.301 ;
     RECT  94.68 39.491 95.808 39.635 ;
     RECT  94.68 39.635 95.736 40.885 ;
     RECT  89.112 39.923 90.528 42.181 ;
     RECT  5.736 40.307 7.104 40.403 ;
     RECT  10.812 40.405 12.24 84.323 ;
     RECT  78.312 40.885 79.488 46.789 ;
     RECT  79.512 40.885 80.7 47.363 ;
     RECT  94.68 40.885 95.712 41.267 ;
     RECT  8.112 41.123 8.28 42.133 ;
     RECT  94.512 41.267 95.712 41.651 ;
     RECT  2.712 41.605 3.984 42.995 ;
     RECT  4.008 41.891 5.1 42.995 ;
     RECT  89.208 42.181 90.528 53.267 ;
     RECT  8.112 43.571 8.232 44.965 ;
     RECT  81.012 44.101 82.176 44.387 ;
     RECT  82.2 44.101 83.4 44.387 ;
     RECT  40.92 52.885 42.144 60.659 ;
     RECT  89.112 53.267 90.528 55.283 ;
     RECT  94.512 53.941 95.76 54.325 ;
     RECT  37.812 54.085 39.168 83.029 ;
     RECT  39.192 54.085 40.2 83.749 ;
     RECT  94.632 54.325 95.76 55.189 ;
     RECT  89.112 55.283 89.448 56.389 ;
     RECT  94.512 55.907 95.664 56.917 ;
     RECT  90.312 56.917 91.5 77.555 ;
     RECT  89.112 57.683 90.288 77.509 ;
     RECT  94.512 58.451 95.808 58.691 ;
     RECT  40.824 60.659 42.144 61.091 ;
     RECT  43.32 64.933 44.784 84.371 ;
     RECT  65.688 65.701 67.2 78.613 ;
     RECT  92.712 74.293 93.936 78.179 ;
     RECT  90.072 77.555 91.5 82.741 ;
     RECT  92.712 78.179 94.032 81.685 ;
     RECT  65.544 79.283 66.624 82.691 ;
     RECT  93.048 81.685 94.032 81.877 ;
     RECT  92.712 82.067 93.984 82.115 ;
     RECT  6.36 82.597 7.8 85.379 ;
     RECT  65.256 82.691 66.624 83.701 ;
     RECT  95.112 82.691 95.736 83.941 ;
     RECT  65.352 83.701 66.624 84.083 ;
     RECT  40.512 83.749 41.76 86.005 ;
     RECT  94.512 84.467 95.712 85.523 ;
     RECT  91.296 84.611 91.344 86.053 ;
     RECT  92.664 84.757 94.032 86.341 ;
     RECT  8.112 85.523 8.232 86.581 ;
     RECT  40.632 86.005 41.76 94.115 ;
     RECT  92.136 86.387 93.504 87.827 ;
     RECT  89.736 86.581 90.912 88.403 ;
     RECT  5.412 87.251 5.736 88.357 ;
     RECT  5.412 88.357 6.816 89.027 ;
     RECT  89.736 88.403 91.152 89.027 ;
     RECT  22.488 94.021 23.856 99.683 ;
     RECT  40.512 94.115 41.76 103.093 ;
     RECT  94.512 95.125 95.808 95.653 ;
     RECT  94.512 95.653 95.52 97.523 ;
     RECT  93.504 96.755 94.08 97.571 ;
     RECT  89.736 96.947 91.152 97.283 ;
     RECT  94.512 97.523 95.712 98.533 ;
     RECT  93.504 97.571 94.2 97.813 ;
     RECT  91.812 97.813 92.88 98.675 ;
     RECT  92.904 97.813 94.2 98.675 ;
     RECT  94.632 98.533 95.712 98.581 ;
     RECT  94.632 98.581 95.664 99.589 ;
     RECT  94.08 98.675 94.2 99.157 ;
     RECT  91.296 98.915 91.5 99.685 ;
     RECT  22.344 99.683 23.856 115.187 ;
     RECT  89.112 99.685 90.288 111.443 ;
     RECT  90.312 99.685 91.5 100.837 ;
     RECT  90.312 101.699 91.5 111.443 ;
     RECT  40.512 103.811 41.76 114.035 ;
     RECT  83.712 105.973 85.2 115.093 ;
     RECT  39.048 109.381 40.08 115.333 ;
     RECT  40.512 114.035 42.144 114.517 ;
     RECT  35.928 114.517 37.392 115.139 ;
     RECT  41.016 114.517 42.144 122.579 ;
     RECT  37.392 116.435 37.5 116.821 ;
     RECT  35.976 116.821 37.5 117.397 ;
     RECT  36.456 117.397 37.5 118.355 ;
     RECT  36.264 118.355 37.5 119.699 ;
     RECT  36.072 119.699 37.5 121.475 ;
     RECT  84.072 120.899 85.296 121.715 ;
     RECT  72.912 122.245 73.92 126.035 ;
     RECT  40.92 122.579 42.144 123.637 ;
     RECT  41.064 123.637 42.144 125.317 ;
     RECT  73.944 123.971 75.3 126.035 ;
     RECT  54.012 124.789 55.152 127.283 ;
     RECT  41.592 125.459 42.624 126.179 ;
     RECT  35.112 126.035 35.544 126.421 ;
     RECT  42.576 126.179 42.624 127.045 ;
     RECT  35.112 126.421 36.432 127.715 ;
     RECT  36.456 126.421 37.5 126.757 ;
     RECT  55.176 126.563 56.4 127.283 ;
     RECT  35.976 129.349 37.152 130.595 ;
     RECT  89.256 136.453 90.576 138.757 ;
     RECT  91.812 138.133 92.88 139.525 ;
     RECT  92.904 138.133 94.2 138.373 ;
     RECT  94.512 138.325 95.712 138.949 ;
     RECT  92.904 138.373 94.032 138.565 ;
     RECT  92.904 138.565 93.984 139.285 ;
     RECT  89.256 138.757 90.48 139.667 ;
     RECT  90.504 138.803 91.5 139.715 ;
     RECT  94.512 138.949 95.52 139.285 ;
     RECT  91.812 139.525 92.832 141.923 ;
     RECT  89.208 139.667 90.48 139.715 ;
     RECT  92.856 140.243 94.08 140.819 ;
     RECT  92.856 140.819 94.2 141.301 ;
     RECT  92.952 141.301 94.2 142.019 ;
     RECT  91.812 141.923 92.928 142.019 ;
     RECT  38.76 149.939 40.2 150.515 ;
  END
END qfd_landh0d8s_151_EW_98x171
END LIBRARY
